VERSION 5.8 ;
BUSBITCHARS "[]" ;
DIVIDERCHAR "/" ;
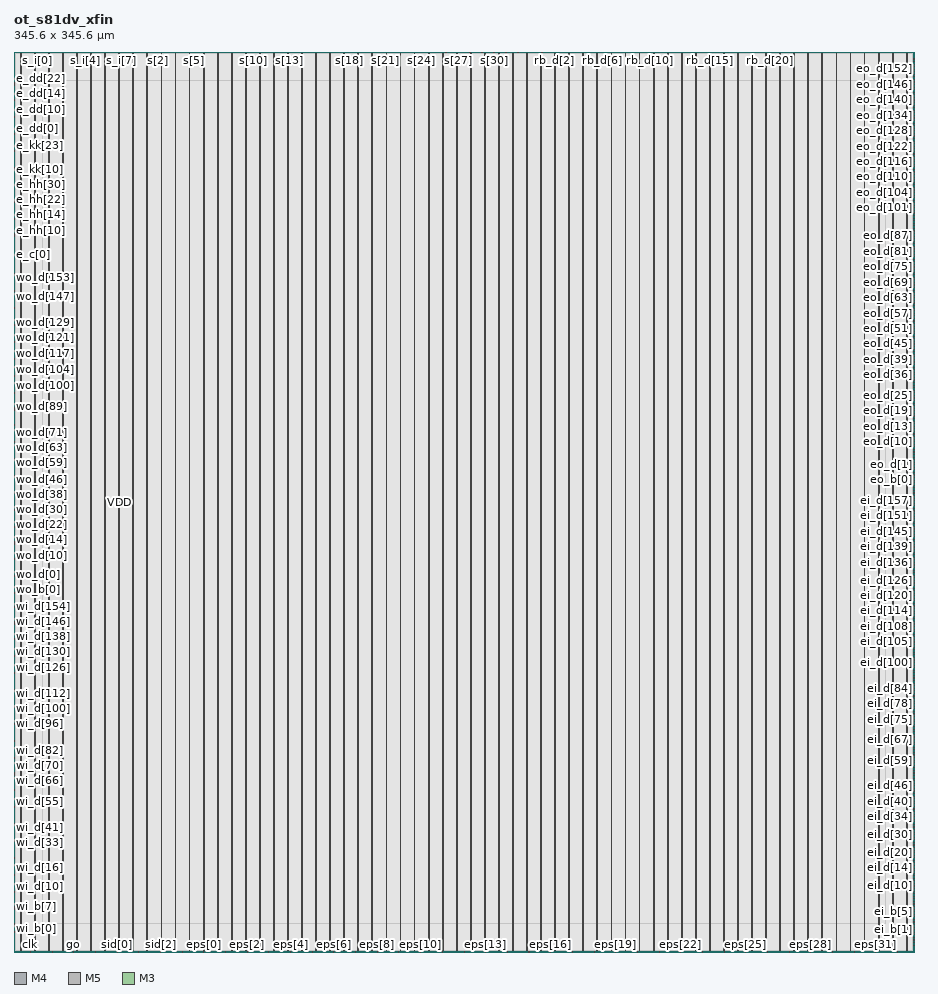
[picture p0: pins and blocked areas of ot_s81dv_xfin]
MACRO ot_s81dv_xfin
  CLASS BLOCK ;
  ORIGIN 0 0 ;
  FOREIGN ot_s81dv_xfin 0 0 ;
  SIZE 345.6 BY 345.6 ;
  SYMMETRY X Y ;
  PIN wi_v
    DIRECTION INPUT ;
    USE SIGNAL ;
    PORT
      LAYER M4 ;
        RECT 0.000 7.680 0.192 7.704 ;
    END
  END wi_v
  PIN wi_h[0]
    DIRECTION INPUT ;
    USE SIGNAL ;
    PORT
      LAYER M4 ;
        RECT 0.000 9.264 0.192 9.288 ;
    END
  END wi_h[0]
  PIN wi_h[1]
    DIRECTION INPUT ;
    USE SIGNAL ;
    PORT
      LAYER M4 ;
        RECT 0.000 10.032 0.192 10.056 ;
    END
  END wi_h[1]
  PIN wi_h[2]
    DIRECTION INPUT ;
    USE SIGNAL ;
    PORT
      LAYER M4 ;
        RECT 0.000 10.752 0.192 10.776 ;
    END
  END wi_h[2]
  PIN wi_h[3]
    DIRECTION INPUT ;
    USE SIGNAL ;
    PORT
      LAYER M4 ;
        RECT 0.000 11.472 0.192 11.496 ;
    END
  END wi_h[3]
  PIN wi_b[0]
    DIRECTION INPUT ;
    USE SIGNAL ;
    PORT
      LAYER M4 ;
        RECT 0.000 12.192 0.192 12.216 ;
    END
  END wi_b[0]
  PIN wi_b[1]
    DIRECTION INPUT ;
    USE SIGNAL ;
    PORT
      LAYER M4 ;
        RECT 0.000 12.912 0.192 12.936 ;
    END
  END wi_b[1]
  PIN wi_b[2]
    DIRECTION INPUT ;
    USE SIGNAL ;
    PORT
      LAYER M4 ;
        RECT 0.000 13.632 0.192 13.656 ;
    END
  END wi_b[2]
  PIN wi_b[3]
    DIRECTION INPUT ;
    USE SIGNAL ;
    PORT
      LAYER M4 ;
        RECT 0.000 14.352 0.192 14.376 ;
    END
  END wi_b[3]
  PIN wi_b[4]
    DIRECTION INPUT ;
    USE SIGNAL ;
    PORT
      LAYER M4 ;
        RECT 0.000 15.072 0.192 15.096 ;
    END
  END wi_b[4]
  PIN wi_b[5]
    DIRECTION INPUT ;
    USE SIGNAL ;
    PORT
      LAYER M4 ;
        RECT 0.000 15.792 0.192 15.816 ;
    END
  END wi_b[5]
  PIN wi_b[6]
    DIRECTION INPUT ;
    USE SIGNAL ;
    PORT
      LAYER M4 ;
        RECT 0.000 16.512 0.192 16.536 ;
    END
  END wi_b[6]
  PIN wi_b[7]
    DIRECTION INPUT ;
    USE SIGNAL ;
    PORT
      LAYER M4 ;
        RECT 0.000 17.280 0.192 17.304 ;
    END
  END wi_b[7]
  PIN wi_d[0]
    DIRECTION INPUT ;
    USE SIGNAL ;
    PORT
      LAYER M4 ;
        RECT 0.000 18.000 0.192 18.024 ;
    END
  END wi_d[0]
  PIN wi_d[1]
    DIRECTION INPUT ;
    USE SIGNAL ;
    PORT
      LAYER M4 ;
        RECT 0.000 18.720 0.192 18.744 ;
    END
  END wi_d[1]
  PIN wi_d[2]
    DIRECTION INPUT ;
    USE SIGNAL ;
    PORT
      LAYER M4 ;
        RECT 0.000 19.440 0.192 19.464 ;
    END
  END wi_d[2]
  PIN wi_d[3]
    DIRECTION INPUT ;
    USE SIGNAL ;
    PORT
      LAYER M4 ;
        RECT 0.000 20.160 0.192 20.184 ;
    END
  END wi_d[3]
  PIN wi_d[4]
    DIRECTION INPUT ;
    USE SIGNAL ;
    PORT
      LAYER M4 ;
        RECT 0.000 20.880 0.192 20.904 ;
    END
  END wi_d[4]
  PIN wi_d[5]
    DIRECTION INPUT ;
    USE SIGNAL ;
    PORT
      LAYER M4 ;
        RECT 0.000 21.600 0.192 21.624 ;
    END
  END wi_d[5]
  PIN wi_d[6]
    DIRECTION INPUT ;
    USE SIGNAL ;
    PORT
      LAYER M4 ;
        RECT 0.000 22.320 0.192 22.344 ;
    END
  END wi_d[6]
  PIN wi_d[7]
    DIRECTION INPUT ;
    USE SIGNAL ;
    PORT
      LAYER M4 ;
        RECT 0.000 23.040 0.192 23.064 ;
    END
  END wi_d[7]
  PIN wi_d[8]
    DIRECTION INPUT ;
    USE SIGNAL ;
    PORT
      LAYER M4 ;
        RECT 0.000 23.760 0.192 23.784 ;
    END
  END wi_d[8]
  PIN wi_d[9]
    DIRECTION INPUT ;
    USE SIGNAL ;
    PORT
      LAYER M4 ;
        RECT 0.000 24.528 0.192 24.552 ;
    END
  END wi_d[9]
  PIN wi_d[10]
    DIRECTION INPUT ;
    USE SIGNAL ;
    PORT
      LAYER M4 ;
        RECT 0.000 25.248 0.192 25.272 ;
    END
  END wi_d[10]
  PIN wi_d[11]
    DIRECTION INPUT ;
    USE SIGNAL ;
    PORT
      LAYER M4 ;
        RECT 0.000 25.968 0.192 25.992 ;
    END
  END wi_d[11]
  PIN wi_d[12]
    DIRECTION INPUT ;
    USE SIGNAL ;
    PORT
      LAYER M4 ;
        RECT 0.000 26.688 0.192 26.712 ;
    END
  END wi_d[12]
  PIN wi_d[13]
    DIRECTION INPUT ;
    USE SIGNAL ;
    PORT
      LAYER M4 ;
        RECT 0.000 27.408 0.192 27.432 ;
    END
  END wi_d[13]
  PIN wi_d[14]
    DIRECTION INPUT ;
    USE SIGNAL ;
    PORT
      LAYER M4 ;
        RECT 0.000 28.128 0.192 28.152 ;
    END
  END wi_d[14]
  PIN wi_d[15]
    DIRECTION INPUT ;
    USE SIGNAL ;
    PORT
      LAYER M4 ;
        RECT 0.000 28.848 0.192 28.872 ;
    END
  END wi_d[15]
  PIN wi_d[16]
    DIRECTION INPUT ;
    USE SIGNAL ;
    PORT
      LAYER M4 ;
        RECT 0.000 29.568 0.192 29.592 ;
    END
  END wi_d[16]
  PIN wi_d[17]
    DIRECTION INPUT ;
    USE SIGNAL ;
    PORT
      LAYER M4 ;
        RECT 0.000 30.288 0.192 30.312 ;
    END
  END wi_d[17]
  PIN wi_d[18]
    DIRECTION INPUT ;
    USE SIGNAL ;
    PORT
      LAYER M4 ;
        RECT 0.000 31.008 0.192 31.032 ;
    END
  END wi_d[18]
  PIN wi_d[19]
    DIRECTION INPUT ;
    USE SIGNAL ;
    PORT
      LAYER M4 ;
        RECT 0.000 31.776 0.192 31.800 ;
    END
  END wi_d[19]
  PIN wi_d[20]
    DIRECTION INPUT ;
    USE SIGNAL ;
    PORT
      LAYER M4 ;
        RECT 0.000 32.496 0.192 32.520 ;
    END
  END wi_d[20]
  PIN wi_d[21]
    DIRECTION INPUT ;
    USE SIGNAL ;
    PORT
      LAYER M4 ;
        RECT 0.000 33.216 0.192 33.240 ;
    END
  END wi_d[21]
  PIN wi_d[22]
    DIRECTION INPUT ;
    USE SIGNAL ;
    PORT
      LAYER M4 ;
        RECT 0.000 33.936 0.192 33.960 ;
    END
  END wi_d[22]
  PIN wi_d[23]
    DIRECTION INPUT ;
    USE SIGNAL ;
    PORT
      LAYER M4 ;
        RECT 0.000 34.656 0.192 34.680 ;
    END
  END wi_d[23]
  PIN wi_d[24]
    DIRECTION INPUT ;
    USE SIGNAL ;
    PORT
      LAYER M4 ;
        RECT 0.000 35.376 0.192 35.400 ;
    END
  END wi_d[24]
  PIN wi_d[25]
    DIRECTION INPUT ;
    USE SIGNAL ;
    PORT
      LAYER M4 ;
        RECT 0.000 36.096 0.192 36.120 ;
    END
  END wi_d[25]
  PIN wi_d[26]
    DIRECTION INPUT ;
    USE SIGNAL ;
    PORT
      LAYER M4 ;
        RECT 0.000 36.816 0.192 36.840 ;
    END
  END wi_d[26]
  PIN wi_d[27]
    DIRECTION INPUT ;
    USE SIGNAL ;
    PORT
      LAYER M4 ;
        RECT 0.000 37.536 0.192 37.560 ;
    END
  END wi_d[27]
  PIN wi_d[28]
    DIRECTION INPUT ;
    USE SIGNAL ;
    PORT
      LAYER M4 ;
        RECT 0.000 38.256 0.192 38.280 ;
    END
  END wi_d[28]
  PIN wi_d[29]
    DIRECTION INPUT ;
    USE SIGNAL ;
    PORT
      LAYER M4 ;
        RECT 0.000 38.976 0.192 39.000 ;
    END
  END wi_d[29]
  PIN wi_d[30]
    DIRECTION INPUT ;
    USE SIGNAL ;
    PORT
      LAYER M4 ;
        RECT 0.000 39.744 0.192 39.768 ;
    END
  END wi_d[30]
  PIN wi_d[31]
    DIRECTION INPUT ;
    USE SIGNAL ;
    PORT
      LAYER M4 ;
        RECT 0.000 40.464 0.192 40.488 ;
    END
  END wi_d[31]
  PIN wi_d[32]
    DIRECTION INPUT ;
    USE SIGNAL ;
    PORT
      LAYER M4 ;
        RECT 0.000 41.184 0.192 41.208 ;
    END
  END wi_d[32]
  PIN wi_d[33]
    DIRECTION INPUT ;
    USE SIGNAL ;
    PORT
      LAYER M4 ;
        RECT 0.000 41.904 0.192 41.928 ;
    END
  END wi_d[33]
  PIN wi_d[34]
    DIRECTION INPUT ;
    USE SIGNAL ;
    PORT
      LAYER M4 ;
        RECT 0.000 42.624 0.192 42.648 ;
    END
  END wi_d[34]
  PIN wi_d[35]
    DIRECTION INPUT ;
    USE SIGNAL ;
    PORT
      LAYER M4 ;
        RECT 0.000 43.344 0.192 43.368 ;
    END
  END wi_d[35]
  PIN wi_d[36]
    DIRECTION INPUT ;
    USE SIGNAL ;
    PORT
      LAYER M4 ;
        RECT 0.000 44.064 0.192 44.088 ;
    END
  END wi_d[36]
  PIN wi_d[37]
    DIRECTION INPUT ;
    USE SIGNAL ;
    PORT
      LAYER M4 ;
        RECT 0.000 44.784 0.192 44.808 ;
    END
  END wi_d[37]
  PIN wi_d[38]
    DIRECTION INPUT ;
    USE SIGNAL ;
    PORT
      LAYER M4 ;
        RECT 0.000 45.504 0.192 45.528 ;
    END
  END wi_d[38]
  PIN wi_d[39]
    DIRECTION INPUT ;
    USE SIGNAL ;
    PORT
      LAYER M4 ;
        RECT 0.000 46.224 0.192 46.248 ;
    END
  END wi_d[39]
  PIN wi_d[40]
    DIRECTION INPUT ;
    USE SIGNAL ;
    PORT
      LAYER M4 ;
        RECT 0.000 46.992 0.192 47.016 ;
    END
  END wi_d[40]
  PIN wi_d[41]
    DIRECTION INPUT ;
    USE SIGNAL ;
    PORT
      LAYER M4 ;
        RECT 0.000 47.712 0.192 47.736 ;
    END
  END wi_d[41]
  PIN wi_d[42]
    DIRECTION INPUT ;
    USE SIGNAL ;
    PORT
      LAYER M4 ;
        RECT 0.000 48.432 0.192 48.456 ;
    END
  END wi_d[42]
  PIN wi_d[43]
    DIRECTION INPUT ;
    USE SIGNAL ;
    PORT
      LAYER M4 ;
        RECT 0.000 49.152 0.192 49.176 ;
    END
  END wi_d[43]
  PIN wi_d[44]
    DIRECTION INPUT ;
    USE SIGNAL ;
    PORT
      LAYER M4 ;
        RECT 0.000 49.872 0.192 49.896 ;
    END
  END wi_d[44]
  PIN wi_d[45]
    DIRECTION INPUT ;
    USE SIGNAL ;
    PORT
      LAYER M4 ;
        RECT 0.000 50.592 0.192 50.616 ;
    END
  END wi_d[45]
  PIN wi_d[46]
    DIRECTION INPUT ;
    USE SIGNAL ;
    PORT
      LAYER M4 ;
        RECT 0.000 51.312 0.192 51.336 ;
    END
  END wi_d[46]
  PIN wi_d[47]
    DIRECTION INPUT ;
    USE SIGNAL ;
    PORT
      LAYER M4 ;
        RECT 0.000 52.032 0.192 52.056 ;
    END
  END wi_d[47]
  PIN wi_d[48]
    DIRECTION INPUT ;
    USE SIGNAL ;
    PORT
      LAYER M4 ;
        RECT 0.000 52.752 0.192 52.776 ;
    END
  END wi_d[48]
  PIN wi_d[49]
    DIRECTION INPUT ;
    USE SIGNAL ;
    PORT
      LAYER M4 ;
        RECT 0.000 53.472 0.192 53.496 ;
    END
  END wi_d[49]
  PIN wi_d[50]
    DIRECTION INPUT ;
    USE SIGNAL ;
    PORT
      LAYER M4 ;
        RECT 0.000 54.240 0.192 54.264 ;
    END
  END wi_d[50]
  PIN wi_d[51]
    DIRECTION INPUT ;
    USE SIGNAL ;
    PORT
      LAYER M4 ;
        RECT 0.000 54.960 0.192 54.984 ;
    END
  END wi_d[51]
  PIN wi_d[52]
    DIRECTION INPUT ;
    USE SIGNAL ;
    PORT
      LAYER M4 ;
        RECT 0.000 55.680 0.192 55.704 ;
    END
  END wi_d[52]
  PIN wi_d[53]
    DIRECTION INPUT ;
    USE SIGNAL ;
    PORT
      LAYER M4 ;
        RECT 0.000 56.400 0.192 56.424 ;
    END
  END wi_d[53]
  PIN wi_d[54]
    DIRECTION INPUT ;
    USE SIGNAL ;
    PORT
      LAYER M4 ;
        RECT 0.000 57.120 0.192 57.144 ;
    END
  END wi_d[54]
  PIN wi_d[55]
    DIRECTION INPUT ;
    USE SIGNAL ;
    PORT
      LAYER M4 ;
        RECT 0.000 57.840 0.192 57.864 ;
    END
  END wi_d[55]
  PIN wi_d[56]
    DIRECTION INPUT ;
    USE SIGNAL ;
    PORT
      LAYER M4 ;
        RECT 0.000 58.560 0.192 58.584 ;
    END
  END wi_d[56]
  PIN wi_d[57]
    DIRECTION INPUT ;
    USE SIGNAL ;
    PORT
      LAYER M4 ;
        RECT 0.000 59.280 0.192 59.304 ;
    END
  END wi_d[57]
  PIN wi_d[58]
    DIRECTION INPUT ;
    USE SIGNAL ;
    PORT
      LAYER M4 ;
        RECT 0.000 60.000 0.192 60.024 ;
    END
  END wi_d[58]
  PIN wi_d[59]
    DIRECTION INPUT ;
    USE SIGNAL ;
    PORT
      LAYER M4 ;
        RECT 0.000 60.720 0.192 60.744 ;
    END
  END wi_d[59]
  PIN wi_d[60]
    DIRECTION INPUT ;
    USE SIGNAL ;
    PORT
      LAYER M4 ;
        RECT 0.000 61.488 0.192 61.512 ;
    END
  END wi_d[60]
  PIN wi_d[61]
    DIRECTION INPUT ;
    USE SIGNAL ;
    PORT
      LAYER M4 ;
        RECT 0.000 62.208 0.192 62.232 ;
    END
  END wi_d[61]
  PIN wi_d[62]
    DIRECTION INPUT ;
    USE SIGNAL ;
    PORT
      LAYER M4 ;
        RECT 0.000 62.928 0.192 62.952 ;
    END
  END wi_d[62]
  PIN wi_d[63]
    DIRECTION INPUT ;
    USE SIGNAL ;
    PORT
      LAYER M4 ;
        RECT 0.000 63.648 0.192 63.672 ;
    END
  END wi_d[63]
  PIN wi_d[64]
    DIRECTION INPUT ;
    USE SIGNAL ;
    PORT
      LAYER M4 ;
        RECT 0.000 64.368 0.192 64.392 ;
    END
  END wi_d[64]
  PIN wi_d[65]
    DIRECTION INPUT ;
    USE SIGNAL ;
    PORT
      LAYER M4 ;
        RECT 0.000 65.088 0.192 65.112 ;
    END
  END wi_d[65]
  PIN wi_d[66]
    DIRECTION INPUT ;
    USE SIGNAL ;
    PORT
      LAYER M4 ;
        RECT 0.000 65.808 0.192 65.832 ;
    END
  END wi_d[66]
  PIN wi_d[67]
    DIRECTION INPUT ;
    USE SIGNAL ;
    PORT
      LAYER M4 ;
        RECT 0.000 66.528 0.192 66.552 ;
    END
  END wi_d[67]
  PIN wi_d[68]
    DIRECTION INPUT ;
    USE SIGNAL ;
    PORT
      LAYER M4 ;
        RECT 0.000 67.248 0.192 67.272 ;
    END
  END wi_d[68]
  PIN wi_d[69]
    DIRECTION INPUT ;
    USE SIGNAL ;
    PORT
      LAYER M4 ;
        RECT 0.000 67.968 0.192 67.992 ;
    END
  END wi_d[69]
  PIN wi_d[70]
    DIRECTION INPUT ;
    USE SIGNAL ;
    PORT
      LAYER M4 ;
        RECT 0.000 68.736 0.192 68.760 ;
    END
  END wi_d[70]
  PIN wi_d[71]
    DIRECTION INPUT ;
    USE SIGNAL ;
    PORT
      LAYER M4 ;
        RECT 0.000 69.456 0.192 69.480 ;
    END
  END wi_d[71]
  PIN wi_d[72]
    DIRECTION INPUT ;
    USE SIGNAL ;
    PORT
      LAYER M4 ;
        RECT 0.000 70.176 0.192 70.200 ;
    END
  END wi_d[72]
  PIN wi_d[73]
    DIRECTION INPUT ;
    USE SIGNAL ;
    PORT
      LAYER M4 ;
        RECT 0.000 70.896 0.192 70.920 ;
    END
  END wi_d[73]
  PIN wi_d[74]
    DIRECTION INPUT ;
    USE SIGNAL ;
    PORT
      LAYER M4 ;
        RECT 0.000 71.616 0.192 71.640 ;
    END
  END wi_d[74]
  PIN wi_d[75]
    DIRECTION INPUT ;
    USE SIGNAL ;
    PORT
      LAYER M4 ;
        RECT 0.000 72.336 0.192 72.360 ;
    END
  END wi_d[75]
  PIN wi_d[76]
    DIRECTION INPUT ;
    USE SIGNAL ;
    PORT
      LAYER M4 ;
        RECT 0.000 73.056 0.192 73.080 ;
    END
  END wi_d[76]
  PIN wi_d[77]
    DIRECTION INPUT ;
    USE SIGNAL ;
    PORT
      LAYER M4 ;
        RECT 0.000 73.776 0.192 73.800 ;
    END
  END wi_d[77]
  PIN wi_d[78]
    DIRECTION INPUT ;
    USE SIGNAL ;
    PORT
      LAYER M4 ;
        RECT 0.000 74.496 0.192 74.520 ;
    END
  END wi_d[78]
  PIN wi_d[79]
    DIRECTION INPUT ;
    USE SIGNAL ;
    PORT
      LAYER M4 ;
        RECT 0.000 75.216 0.192 75.240 ;
    END
  END wi_d[79]
  PIN wi_d[80]
    DIRECTION INPUT ;
    USE SIGNAL ;
    PORT
      LAYER M4 ;
        RECT 0.000 75.984 0.192 76.008 ;
    END
  END wi_d[80]
  PIN wi_d[81]
    DIRECTION INPUT ;
    USE SIGNAL ;
    PORT
      LAYER M4 ;
        RECT 0.000 76.704 0.192 76.728 ;
    END
  END wi_d[81]
  PIN wi_d[82]
    DIRECTION INPUT ;
    USE SIGNAL ;
    PORT
      LAYER M4 ;
        RECT 0.000 77.424 0.192 77.448 ;
    END
  END wi_d[82]
  PIN wi_d[83]
    DIRECTION INPUT ;
    USE SIGNAL ;
    PORT
      LAYER M4 ;
        RECT 0.000 78.144 0.192 78.168 ;
    END
  END wi_d[83]
  PIN wi_d[84]
    DIRECTION INPUT ;
    USE SIGNAL ;
    PORT
      LAYER M4 ;
        RECT 0.000 78.864 0.192 78.888 ;
    END
  END wi_d[84]
  PIN wi_d[85]
    DIRECTION INPUT ;
    USE SIGNAL ;
    PORT
      LAYER M4 ;
        RECT 0.000 79.584 0.192 79.608 ;
    END
  END wi_d[85]
  PIN wi_d[86]
    DIRECTION INPUT ;
    USE SIGNAL ;
    PORT
      LAYER M4 ;
        RECT 0.000 80.304 0.192 80.328 ;
    END
  END wi_d[86]
  PIN wi_d[87]
    DIRECTION INPUT ;
    USE SIGNAL ;
    PORT
      LAYER M4 ;
        RECT 0.000 81.024 0.192 81.048 ;
    END
  END wi_d[87]
  PIN wi_d[88]
    DIRECTION INPUT ;
    USE SIGNAL ;
    PORT
      LAYER M4 ;
        RECT 0.000 81.744 0.192 81.768 ;
    END
  END wi_d[88]
  PIN wi_d[89]
    DIRECTION INPUT ;
    USE SIGNAL ;
    PORT
      LAYER M4 ;
        RECT 0.000 82.464 0.192 82.488 ;
    END
  END wi_d[89]
  PIN wi_d[90]
    DIRECTION INPUT ;
    USE SIGNAL ;
    PORT
      LAYER M4 ;
        RECT 0.000 83.232 0.192 83.256 ;
    END
  END wi_d[90]
  PIN wi_d[91]
    DIRECTION INPUT ;
    USE SIGNAL ;
    PORT
      LAYER M4 ;
        RECT 0.000 83.952 0.192 83.976 ;
    END
  END wi_d[91]
  PIN wi_d[92]
    DIRECTION INPUT ;
    USE SIGNAL ;
    PORT
      LAYER M4 ;
        RECT 0.000 84.672 0.192 84.696 ;
    END
  END wi_d[92]
  PIN wi_d[93]
    DIRECTION INPUT ;
    USE SIGNAL ;
    PORT
      LAYER M4 ;
        RECT 0.000 85.392 0.192 85.416 ;
    END
  END wi_d[93]
  PIN wi_d[94]
    DIRECTION INPUT ;
    USE SIGNAL ;
    PORT
      LAYER M4 ;
        RECT 0.000 86.112 0.192 86.136 ;
    END
  END wi_d[94]
  PIN wi_d[95]
    DIRECTION INPUT ;
    USE SIGNAL ;
    PORT
      LAYER M4 ;
        RECT 0.000 86.832 0.192 86.856 ;
    END
  END wi_d[95]
  PIN wi_d[96]
    DIRECTION INPUT ;
    USE SIGNAL ;
    PORT
      LAYER M4 ;
        RECT 0.000 87.552 0.192 87.576 ;
    END
  END wi_d[96]
  PIN wi_d[97]
    DIRECTION INPUT ;
    USE SIGNAL ;
    PORT
      LAYER M4 ;
        RECT 0.000 88.272 0.192 88.296 ;
    END
  END wi_d[97]
  PIN wi_d[98]
    DIRECTION INPUT ;
    USE SIGNAL ;
    PORT
      LAYER M4 ;
        RECT 0.000 88.992 0.192 89.016 ;
    END
  END wi_d[98]
  PIN wi_d[99]
    DIRECTION INPUT ;
    USE SIGNAL ;
    PORT
      LAYER M4 ;
        RECT 0.000 89.712 0.192 89.736 ;
    END
  END wi_d[99]
  PIN wi_d[100]
    DIRECTION INPUT ;
    USE SIGNAL ;
    PORT
      LAYER M4 ;
        RECT 0.000 90.480 0.192 90.504 ;
    END
  END wi_d[100]
  PIN wi_d[101]
    DIRECTION INPUT ;
    USE SIGNAL ;
    PORT
      LAYER M4 ;
        RECT 0.000 91.200 0.192 91.224 ;
    END
  END wi_d[101]
  PIN wi_d[102]
    DIRECTION INPUT ;
    USE SIGNAL ;
    PORT
      LAYER M4 ;
        RECT 0.000 91.920 0.192 91.944 ;
    END
  END wi_d[102]
  PIN wi_d[103]
    DIRECTION INPUT ;
    USE SIGNAL ;
    PORT
      LAYER M4 ;
        RECT 0.000 92.640 0.192 92.664 ;
    END
  END wi_d[103]
  PIN wi_d[104]
    DIRECTION INPUT ;
    USE SIGNAL ;
    PORT
      LAYER M4 ;
        RECT 0.000 93.360 0.192 93.384 ;
    END
  END wi_d[104]
  PIN wi_d[105]
    DIRECTION INPUT ;
    USE SIGNAL ;
    PORT
      LAYER M4 ;
        RECT 0.000 94.080 0.192 94.104 ;
    END
  END wi_d[105]
  PIN wi_d[106]
    DIRECTION INPUT ;
    USE SIGNAL ;
    PORT
      LAYER M4 ;
        RECT 0.000 94.800 0.192 94.824 ;
    END
  END wi_d[106]
  PIN wi_d[107]
    DIRECTION INPUT ;
    USE SIGNAL ;
    PORT
      LAYER M4 ;
        RECT 0.000 95.520 0.192 95.544 ;
    END
  END wi_d[107]
  PIN wi_d[108]
    DIRECTION INPUT ;
    USE SIGNAL ;
    PORT
      LAYER M4 ;
        RECT 0.000 96.240 0.192 96.264 ;
    END
  END wi_d[108]
  PIN wi_d[109]
    DIRECTION INPUT ;
    USE SIGNAL ;
    PORT
      LAYER M4 ;
        RECT 0.000 96.960 0.192 96.984 ;
    END
  END wi_d[109]
  PIN wi_d[110]
    DIRECTION INPUT ;
    USE SIGNAL ;
    PORT
      LAYER M4 ;
        RECT 0.000 97.728 0.192 97.752 ;
    END
  END wi_d[110]
  PIN wi_d[111]
    DIRECTION INPUT ;
    USE SIGNAL ;
    PORT
      LAYER M4 ;
        RECT 0.000 98.448 0.192 98.472 ;
    END
  END wi_d[111]
  PIN wi_d[112]
    DIRECTION INPUT ;
    USE SIGNAL ;
    PORT
      LAYER M4 ;
        RECT 0.000 99.168 0.192 99.192 ;
    END
  END wi_d[112]
  PIN wi_d[113]
    DIRECTION INPUT ;
    USE SIGNAL ;
    PORT
      LAYER M4 ;
        RECT 0.000 99.888 0.192 99.912 ;
    END
  END wi_d[113]
  PIN wi_d[114]
    DIRECTION INPUT ;
    USE SIGNAL ;
    PORT
      LAYER M4 ;
        RECT 0.000 100.608 0.192 100.632 ;
    END
  END wi_d[114]
  PIN wi_d[115]
    DIRECTION INPUT ;
    USE SIGNAL ;
    PORT
      LAYER M4 ;
        RECT 0.000 101.328 0.192 101.352 ;
    END
  END wi_d[115]
  PIN wi_d[116]
    DIRECTION INPUT ;
    USE SIGNAL ;
    PORT
      LAYER M4 ;
        RECT 0.000 102.048 0.192 102.072 ;
    END
  END wi_d[116]
  PIN wi_d[117]
    DIRECTION INPUT ;
    USE SIGNAL ;
    PORT
      LAYER M4 ;
        RECT 0.000 102.768 0.192 102.792 ;
    END
  END wi_d[117]
  PIN wi_d[118]
    DIRECTION INPUT ;
    USE SIGNAL ;
    PORT
      LAYER M4 ;
        RECT 0.000 103.488 0.192 103.512 ;
    END
  END wi_d[118]
  PIN wi_d[119]
    DIRECTION INPUT ;
    USE SIGNAL ;
    PORT
      LAYER M4 ;
        RECT 0.000 104.208 0.192 104.232 ;
    END
  END wi_d[119]
  PIN wi_d[120]
    DIRECTION INPUT ;
    USE SIGNAL ;
    PORT
      LAYER M4 ;
        RECT 0.000 104.976 0.192 105.000 ;
    END
  END wi_d[120]
  PIN wi_d[121]
    DIRECTION INPUT ;
    USE SIGNAL ;
    PORT
      LAYER M4 ;
        RECT 0.000 105.696 0.192 105.720 ;
    END
  END wi_d[121]
  PIN wi_d[122]
    DIRECTION INPUT ;
    USE SIGNAL ;
    PORT
      LAYER M4 ;
        RECT 0.000 106.416 0.192 106.440 ;
    END
  END wi_d[122]
  PIN wi_d[123]
    DIRECTION INPUT ;
    USE SIGNAL ;
    PORT
      LAYER M4 ;
        RECT 0.000 107.136 0.192 107.160 ;
    END
  END wi_d[123]
  PIN wi_d[124]
    DIRECTION INPUT ;
    USE SIGNAL ;
    PORT
      LAYER M4 ;
        RECT 0.000 107.856 0.192 107.880 ;
    END
  END wi_d[124]
  PIN wi_d[125]
    DIRECTION INPUT ;
    USE SIGNAL ;
    PORT
      LAYER M4 ;
        RECT 0.000 108.576 0.192 108.600 ;
    END
  END wi_d[125]
  PIN wi_d[126]
    DIRECTION INPUT ;
    USE SIGNAL ;
    PORT
      LAYER M4 ;
        RECT 0.000 109.296 0.192 109.320 ;
    END
  END wi_d[126]
  PIN wi_d[127]
    DIRECTION INPUT ;
    USE SIGNAL ;
    PORT
      LAYER M4 ;
        RECT 0.000 110.016 0.192 110.040 ;
    END
  END wi_d[127]
  PIN wi_d[128]
    DIRECTION INPUT ;
    USE SIGNAL ;
    PORT
      LAYER M4 ;
        RECT 0.000 110.736 0.192 110.760 ;
    END
  END wi_d[128]
  PIN wi_d[129]
    DIRECTION INPUT ;
    USE SIGNAL ;
    PORT
      LAYER M4 ;
        RECT 0.000 111.456 0.192 111.480 ;
    END
  END wi_d[129]
  PIN wi_d[130]
    DIRECTION INPUT ;
    USE SIGNAL ;
    PORT
      LAYER M4 ;
        RECT 0.000 112.224 0.192 112.248 ;
    END
  END wi_d[130]
  PIN wi_d[131]
    DIRECTION INPUT ;
    USE SIGNAL ;
    PORT
      LAYER M4 ;
        RECT 0.000 112.944 0.192 112.968 ;
    END
  END wi_d[131]
  PIN wi_d[132]
    DIRECTION INPUT ;
    USE SIGNAL ;
    PORT
      LAYER M4 ;
        RECT 0.000 113.664 0.192 113.688 ;
    END
  END wi_d[132]
  PIN wi_d[133]
    DIRECTION INPUT ;
    USE SIGNAL ;
    PORT
      LAYER M4 ;
        RECT 0.000 114.384 0.192 114.408 ;
    END
  END wi_d[133]
  PIN wi_d[134]
    DIRECTION INPUT ;
    USE SIGNAL ;
    PORT
      LAYER M4 ;
        RECT 0.000 115.104 0.192 115.128 ;
    END
  END wi_d[134]
  PIN wi_d[135]
    DIRECTION INPUT ;
    USE SIGNAL ;
    PORT
      LAYER M4 ;
        RECT 0.000 115.824 0.192 115.848 ;
    END
  END wi_d[135]
  PIN wi_d[136]
    DIRECTION INPUT ;
    USE SIGNAL ;
    PORT
      LAYER M4 ;
        RECT 0.000 116.544 0.192 116.568 ;
    END
  END wi_d[136]
  PIN wi_d[137]
    DIRECTION INPUT ;
    USE SIGNAL ;
    PORT
      LAYER M4 ;
        RECT 0.000 117.264 0.192 117.288 ;
    END
  END wi_d[137]
  PIN wi_d[138]
    DIRECTION INPUT ;
    USE SIGNAL ;
    PORT
      LAYER M4 ;
        RECT 0.000 117.984 0.192 118.008 ;
    END
  END wi_d[138]
  PIN wi_d[139]
    DIRECTION INPUT ;
    USE SIGNAL ;
    PORT
      LAYER M4 ;
        RECT 0.000 118.704 0.192 118.728 ;
    END
  END wi_d[139]
  PIN wi_d[140]
    DIRECTION INPUT ;
    USE SIGNAL ;
    PORT
      LAYER M4 ;
        RECT 0.000 119.472 0.192 119.496 ;
    END
  END wi_d[140]
  PIN wi_d[141]
    DIRECTION INPUT ;
    USE SIGNAL ;
    PORT
      LAYER M4 ;
        RECT 0.000 120.192 0.192 120.216 ;
    END
  END wi_d[141]
  PIN wi_d[142]
    DIRECTION INPUT ;
    USE SIGNAL ;
    PORT
      LAYER M4 ;
        RECT 0.000 120.912 0.192 120.936 ;
    END
  END wi_d[142]
  PIN wi_d[143]
    DIRECTION INPUT ;
    USE SIGNAL ;
    PORT
      LAYER M4 ;
        RECT 0.000 121.632 0.192 121.656 ;
    END
  END wi_d[143]
  PIN wi_d[144]
    DIRECTION INPUT ;
    USE SIGNAL ;
    PORT
      LAYER M4 ;
        RECT 0.000 122.352 0.192 122.376 ;
    END
  END wi_d[144]
  PIN wi_d[145]
    DIRECTION INPUT ;
    USE SIGNAL ;
    PORT
      LAYER M4 ;
        RECT 0.000 123.072 0.192 123.096 ;
    END
  END wi_d[145]
  PIN wi_d[146]
    DIRECTION INPUT ;
    USE SIGNAL ;
    PORT
      LAYER M4 ;
        RECT 0.000 123.792 0.192 123.816 ;
    END
  END wi_d[146]
  PIN wi_d[147]
    DIRECTION INPUT ;
    USE SIGNAL ;
    PORT
      LAYER M4 ;
        RECT 0.000 124.512 0.192 124.536 ;
    END
  END wi_d[147]
  PIN wi_d[148]
    DIRECTION INPUT ;
    USE SIGNAL ;
    PORT
      LAYER M4 ;
        RECT 0.000 125.232 0.192 125.256 ;
    END
  END wi_d[148]
  PIN wi_d[149]
    DIRECTION INPUT ;
    USE SIGNAL ;
    PORT
      LAYER M4 ;
        RECT 0.000 125.952 0.192 125.976 ;
    END
  END wi_d[149]
  PIN wi_d[150]
    DIRECTION INPUT ;
    USE SIGNAL ;
    PORT
      LAYER M4 ;
        RECT 0.000 126.720 0.192 126.744 ;
    END
  END wi_d[150]
  PIN wi_d[151]
    DIRECTION INPUT ;
    USE SIGNAL ;
    PORT
      LAYER M4 ;
        RECT 0.000 127.440 0.192 127.464 ;
    END
  END wi_d[151]
  PIN wi_d[152]
    DIRECTION INPUT ;
    USE SIGNAL ;
    PORT
      LAYER M4 ;
        RECT 0.000 128.160 0.192 128.184 ;
    END
  END wi_d[152]
  PIN wi_d[153]
    DIRECTION INPUT ;
    USE SIGNAL ;
    PORT
      LAYER M4 ;
        RECT 0.000 128.880 0.192 128.904 ;
    END
  END wi_d[153]
  PIN wi_d[154]
    DIRECTION INPUT ;
    USE SIGNAL ;
    PORT
      LAYER M4 ;
        RECT 0.000 129.600 0.192 129.624 ;
    END
  END wi_d[154]
  PIN wi_d[155]
    DIRECTION INPUT ;
    USE SIGNAL ;
    PORT
      LAYER M4 ;
        RECT 0.000 130.320 0.192 130.344 ;
    END
  END wi_d[155]
  PIN wi_d[156]
    DIRECTION INPUT ;
    USE SIGNAL ;
    PORT
      LAYER M4 ;
        RECT 0.000 131.040 0.192 131.064 ;
    END
  END wi_d[156]
  PIN wi_d[157]
    DIRECTION INPUT ;
    USE SIGNAL ;
    PORT
      LAYER M4 ;
        RECT 0.000 131.760 0.192 131.784 ;
    END
  END wi_d[157]
  PIN wi_d[158]
    DIRECTION INPUT ;
    USE SIGNAL ;
    PORT
      LAYER M4 ;
        RECT 0.000 132.480 0.192 132.504 ;
    END
  END wi_d[158]
  PIN wi_d[159]
    DIRECTION INPUT ;
    USE SIGNAL ;
    PORT
      LAYER M4 ;
        RECT 0.000 133.200 0.192 133.224 ;
    END
  END wi_d[159]
  PIN wo_v
    DIRECTION OUTPUT ;
    USE SIGNAL ;
    PORT
      LAYER M4 ;
        RECT 0.000 134.832 0.192 134.856 ;
    END
  END wo_v
  PIN wo_h[0]
    DIRECTION OUTPUT ;
    USE SIGNAL ;
    PORT
      LAYER M4 ;
        RECT 0.000 136.416 0.192 136.440 ;
    END
  END wo_h[0]
  PIN wo_h[1]
    DIRECTION OUTPUT ;
    USE SIGNAL ;
    PORT
      LAYER M4 ;
        RECT 0.000 137.136 0.192 137.160 ;
    END
  END wo_h[1]
  PIN wo_h[2]
    DIRECTION OUTPUT ;
    USE SIGNAL ;
    PORT
      LAYER M4 ;
        RECT 0.000 137.856 0.192 137.880 ;
    END
  END wo_h[2]
  PIN wo_h[3]
    DIRECTION OUTPUT ;
    USE SIGNAL ;
    PORT
      LAYER M4 ;
        RECT 0.000 138.576 0.192 138.600 ;
    END
  END wo_h[3]
  PIN wo_b[0]
    DIRECTION OUTPUT ;
    USE SIGNAL ;
    PORT
      LAYER M4 ;
        RECT 0.000 139.296 0.192 139.320 ;
    END
  END wo_b[0]
  PIN wo_b[1]
    DIRECTION OUTPUT ;
    USE SIGNAL ;
    PORT
      LAYER M4 ;
        RECT 0.000 140.016 0.192 140.040 ;
    END
  END wo_b[1]
  PIN wo_b[2]
    DIRECTION OUTPUT ;
    USE SIGNAL ;
    PORT
      LAYER M4 ;
        RECT 0.000 140.736 0.192 140.760 ;
    END
  END wo_b[2]
  PIN wo_b[3]
    DIRECTION OUTPUT ;
    USE SIGNAL ;
    PORT
      LAYER M4 ;
        RECT 0.000 141.456 0.192 141.480 ;
    END
  END wo_b[3]
  PIN wo_b[4]
    DIRECTION OUTPUT ;
    USE SIGNAL ;
    PORT
      LAYER M4 ;
        RECT 0.000 142.176 0.192 142.200 ;
    END
  END wo_b[4]
  PIN wo_b[5]
    DIRECTION OUTPUT ;
    USE SIGNAL ;
    PORT
      LAYER M4 ;
        RECT 0.000 142.944 0.192 142.968 ;
    END
  END wo_b[5]
  PIN wo_b[6]
    DIRECTION OUTPUT ;
    USE SIGNAL ;
    PORT
      LAYER M4 ;
        RECT 0.000 143.664 0.192 143.688 ;
    END
  END wo_b[6]
  PIN wo_b[7]
    DIRECTION OUTPUT ;
    USE SIGNAL ;
    PORT
      LAYER M4 ;
        RECT 0.000 144.384 0.192 144.408 ;
    END
  END wo_b[7]
  PIN wo_d[0]
    DIRECTION OUTPUT ;
    USE SIGNAL ;
    PORT
      LAYER M4 ;
        RECT 0.000 145.104 0.192 145.128 ;
    END
  END wo_d[0]
  PIN wo_d[1]
    DIRECTION OUTPUT ;
    USE SIGNAL ;
    PORT
      LAYER M4 ;
        RECT 0.000 145.824 0.192 145.848 ;
    END
  END wo_d[1]
  PIN wo_d[2]
    DIRECTION OUTPUT ;
    USE SIGNAL ;
    PORT
      LAYER M4 ;
        RECT 0.000 146.544 0.192 146.568 ;
    END
  END wo_d[2]
  PIN wo_d[3]
    DIRECTION OUTPUT ;
    USE SIGNAL ;
    PORT
      LAYER M4 ;
        RECT 0.000 147.264 0.192 147.288 ;
    END
  END wo_d[3]
  PIN wo_d[4]
    DIRECTION OUTPUT ;
    USE SIGNAL ;
    PORT
      LAYER M4 ;
        RECT 0.000 147.984 0.192 148.008 ;
    END
  END wo_d[4]
  PIN wo_d[5]
    DIRECTION OUTPUT ;
    USE SIGNAL ;
    PORT
      LAYER M4 ;
        RECT 0.000 148.704 0.192 148.728 ;
    END
  END wo_d[5]
  PIN wo_d[6]
    DIRECTION OUTPUT ;
    USE SIGNAL ;
    PORT
      LAYER M4 ;
        RECT 0.000 149.424 0.192 149.448 ;
    END
  END wo_d[6]
  PIN wo_d[7]
    DIRECTION OUTPUT ;
    USE SIGNAL ;
    PORT
      LAYER M4 ;
        RECT 0.000 150.192 0.192 150.216 ;
    END
  END wo_d[7]
  PIN wo_d[8]
    DIRECTION OUTPUT ;
    USE SIGNAL ;
    PORT
      LAYER M4 ;
        RECT 0.000 150.912 0.192 150.936 ;
    END
  END wo_d[8]
  PIN wo_d[9]
    DIRECTION OUTPUT ;
    USE SIGNAL ;
    PORT
      LAYER M4 ;
        RECT 0.000 151.632 0.192 151.656 ;
    END
  END wo_d[9]
  PIN wo_d[10]
    DIRECTION OUTPUT ;
    USE SIGNAL ;
    PORT
      LAYER M4 ;
        RECT 0.000 152.352 0.192 152.376 ;
    END
  END wo_d[10]
  PIN wo_d[11]
    DIRECTION OUTPUT ;
    USE SIGNAL ;
    PORT
      LAYER M4 ;
        RECT 0.000 153.072 0.192 153.096 ;
    END
  END wo_d[11]
  PIN wo_d[12]
    DIRECTION OUTPUT ;
    USE SIGNAL ;
    PORT
      LAYER M4 ;
        RECT 0.000 153.792 0.192 153.816 ;
    END
  END wo_d[12]
  PIN wo_d[13]
    DIRECTION OUTPUT ;
    USE SIGNAL ;
    PORT
      LAYER M4 ;
        RECT 0.000 154.512 0.192 154.536 ;
    END
  END wo_d[13]
  PIN wo_d[14]
    DIRECTION OUTPUT ;
    USE SIGNAL ;
    PORT
      LAYER M4 ;
        RECT 0.000 155.232 0.192 155.256 ;
    END
  END wo_d[14]
  PIN wo_d[15]
    DIRECTION OUTPUT ;
    USE SIGNAL ;
    PORT
      LAYER M4 ;
        RECT 0.000 155.952 0.192 155.976 ;
    END
  END wo_d[15]
  PIN wo_d[16]
    DIRECTION OUTPUT ;
    USE SIGNAL ;
    PORT
      LAYER M4 ;
        RECT 0.000 156.672 0.192 156.696 ;
    END
  END wo_d[16]
  PIN wo_d[17]
    DIRECTION OUTPUT ;
    USE SIGNAL ;
    PORT
      LAYER M4 ;
        RECT 0.000 157.440 0.192 157.464 ;
    END
  END wo_d[17]
  PIN wo_d[18]
    DIRECTION OUTPUT ;
    USE SIGNAL ;
    PORT
      LAYER M4 ;
        RECT 0.000 158.160 0.192 158.184 ;
    END
  END wo_d[18]
  PIN wo_d[19]
    DIRECTION OUTPUT ;
    USE SIGNAL ;
    PORT
      LAYER M4 ;
        RECT 0.000 158.880 0.192 158.904 ;
    END
  END wo_d[19]
  PIN wo_d[20]
    DIRECTION OUTPUT ;
    USE SIGNAL ;
    PORT
      LAYER M4 ;
        RECT 0.000 159.600 0.192 159.624 ;
    END
  END wo_d[20]
  PIN wo_d[21]
    DIRECTION OUTPUT ;
    USE SIGNAL ;
    PORT
      LAYER M4 ;
        RECT 0.000 160.320 0.192 160.344 ;
    END
  END wo_d[21]
  PIN wo_d[22]
    DIRECTION OUTPUT ;
    USE SIGNAL ;
    PORT
      LAYER M4 ;
        RECT 0.000 161.040 0.192 161.064 ;
    END
  END wo_d[22]
  PIN wo_d[23]
    DIRECTION OUTPUT ;
    USE SIGNAL ;
    PORT
      LAYER M4 ;
        RECT 0.000 161.760 0.192 161.784 ;
    END
  END wo_d[23]
  PIN wo_d[24]
    DIRECTION OUTPUT ;
    USE SIGNAL ;
    PORT
      LAYER M4 ;
        RECT 0.000 162.480 0.192 162.504 ;
    END
  END wo_d[24]
  PIN wo_d[25]
    DIRECTION OUTPUT ;
    USE SIGNAL ;
    PORT
      LAYER M4 ;
        RECT 0.000 163.200 0.192 163.224 ;
    END
  END wo_d[25]
  PIN wo_d[26]
    DIRECTION OUTPUT ;
    USE SIGNAL ;
    PORT
      LAYER M4 ;
        RECT 0.000 163.920 0.192 163.944 ;
    END
  END wo_d[26]
  PIN wo_d[27]
    DIRECTION OUTPUT ;
    USE SIGNAL ;
    PORT
      LAYER M4 ;
        RECT 0.000 164.688 0.192 164.712 ;
    END
  END wo_d[27]
  PIN wo_d[28]
    DIRECTION OUTPUT ;
    USE SIGNAL ;
    PORT
      LAYER M4 ;
        RECT 0.000 165.408 0.192 165.432 ;
    END
  END wo_d[28]
  PIN wo_d[29]
    DIRECTION OUTPUT ;
    USE SIGNAL ;
    PORT
      LAYER M4 ;
        RECT 0.000 166.128 0.192 166.152 ;
    END
  END wo_d[29]
  PIN wo_d[30]
    DIRECTION OUTPUT ;
    USE SIGNAL ;
    PORT
      LAYER M4 ;
        RECT 0.000 166.848 0.192 166.872 ;
    END
  END wo_d[30]
  PIN wo_d[31]
    DIRECTION OUTPUT ;
    USE SIGNAL ;
    PORT
      LAYER M4 ;
        RECT 0.000 167.568 0.192 167.592 ;
    END
  END wo_d[31]
  PIN wo_d[32]
    DIRECTION OUTPUT ;
    USE SIGNAL ;
    PORT
      LAYER M4 ;
        RECT 0.000 168.288 0.192 168.312 ;
    END
  END wo_d[32]
  PIN wo_d[33]
    DIRECTION OUTPUT ;
    USE SIGNAL ;
    PORT
      LAYER M4 ;
        RECT 0.000 169.008 0.192 169.032 ;
    END
  END wo_d[33]
  PIN wo_d[34]
    DIRECTION OUTPUT ;
    USE SIGNAL ;
    PORT
      LAYER M4 ;
        RECT 0.000 169.728 0.192 169.752 ;
    END
  END wo_d[34]
  PIN wo_d[35]
    DIRECTION OUTPUT ;
    USE SIGNAL ;
    PORT
      LAYER M4 ;
        RECT 0.000 170.448 0.192 170.472 ;
    END
  END wo_d[35]
  PIN wo_d[36]
    DIRECTION OUTPUT ;
    USE SIGNAL ;
    PORT
      LAYER M4 ;
        RECT 0.000 171.168 0.192 171.192 ;
    END
  END wo_d[36]
  PIN wo_d[37]
    DIRECTION OUTPUT ;
    USE SIGNAL ;
    PORT
      LAYER M4 ;
        RECT 0.000 171.936 0.192 171.960 ;
    END
  END wo_d[37]
  PIN wo_d[38]
    DIRECTION OUTPUT ;
    USE SIGNAL ;
    PORT
      LAYER M4 ;
        RECT 0.000 172.656 0.192 172.680 ;
    END
  END wo_d[38]
  PIN wo_d[39]
    DIRECTION OUTPUT ;
    USE SIGNAL ;
    PORT
      LAYER M4 ;
        RECT 0.000 173.376 0.192 173.400 ;
    END
  END wo_d[39]
  PIN wo_d[40]
    DIRECTION OUTPUT ;
    USE SIGNAL ;
    PORT
      LAYER M4 ;
        RECT 0.000 174.096 0.192 174.120 ;
    END
  END wo_d[40]
  PIN wo_d[41]
    DIRECTION OUTPUT ;
    USE SIGNAL ;
    PORT
      LAYER M4 ;
        RECT 0.000 174.816 0.192 174.840 ;
    END
  END wo_d[41]
  PIN wo_d[42]
    DIRECTION OUTPUT ;
    USE SIGNAL ;
    PORT
      LAYER M4 ;
        RECT 0.000 175.536 0.192 175.560 ;
    END
  END wo_d[42]
  PIN wo_d[43]
    DIRECTION OUTPUT ;
    USE SIGNAL ;
    PORT
      LAYER M4 ;
        RECT 0.000 176.256 0.192 176.280 ;
    END
  END wo_d[43]
  PIN wo_d[44]
    DIRECTION OUTPUT ;
    USE SIGNAL ;
    PORT
      LAYER M4 ;
        RECT 0.000 176.976 0.192 177.000 ;
    END
  END wo_d[44]
  PIN wo_d[45]
    DIRECTION OUTPUT ;
    USE SIGNAL ;
    PORT
      LAYER M4 ;
        RECT 0.000 177.696 0.192 177.720 ;
    END
  END wo_d[45]
  PIN wo_d[46]
    DIRECTION OUTPUT ;
    USE SIGNAL ;
    PORT
      LAYER M4 ;
        RECT 0.000 178.416 0.192 178.440 ;
    END
  END wo_d[46]
  PIN wo_d[47]
    DIRECTION OUTPUT ;
    USE SIGNAL ;
    PORT
      LAYER M4 ;
        RECT 0.000 179.136 0.192 179.160 ;
    END
  END wo_d[47]
  PIN wo_d[48]
    DIRECTION OUTPUT ;
    USE SIGNAL ;
    PORT
      LAYER M4 ;
        RECT 0.000 179.904 0.192 179.928 ;
    END
  END wo_d[48]
  PIN wo_d[49]
    DIRECTION OUTPUT ;
    USE SIGNAL ;
    PORT
      LAYER M4 ;
        RECT 0.000 180.624 0.192 180.648 ;
    END
  END wo_d[49]
  PIN wo_d[50]
    DIRECTION OUTPUT ;
    USE SIGNAL ;
    PORT
      LAYER M4 ;
        RECT 0.000 181.344 0.192 181.368 ;
    END
  END wo_d[50]
  PIN wo_d[51]
    DIRECTION OUTPUT ;
    USE SIGNAL ;
    PORT
      LAYER M4 ;
        RECT 0.000 182.064 0.192 182.088 ;
    END
  END wo_d[51]
  PIN wo_d[52]
    DIRECTION OUTPUT ;
    USE SIGNAL ;
    PORT
      LAYER M4 ;
        RECT 0.000 182.784 0.192 182.808 ;
    END
  END wo_d[52]
  PIN wo_d[53]
    DIRECTION OUTPUT ;
    USE SIGNAL ;
    PORT
      LAYER M4 ;
        RECT 0.000 183.504 0.192 183.528 ;
    END
  END wo_d[53]
  PIN wo_d[54]
    DIRECTION OUTPUT ;
    USE SIGNAL ;
    PORT
      LAYER M4 ;
        RECT 0.000 184.224 0.192 184.248 ;
    END
  END wo_d[54]
  PIN wo_d[55]
    DIRECTION OUTPUT ;
    USE SIGNAL ;
    PORT
      LAYER M4 ;
        RECT 0.000 184.944 0.192 184.968 ;
    END
  END wo_d[55]
  PIN wo_d[56]
    DIRECTION OUTPUT ;
    USE SIGNAL ;
    PORT
      LAYER M4 ;
        RECT 0.000 185.664 0.192 185.688 ;
    END
  END wo_d[56]
  PIN wo_d[57]
    DIRECTION OUTPUT ;
    USE SIGNAL ;
    PORT
      LAYER M4 ;
        RECT 0.000 186.384 0.192 186.408 ;
    END
  END wo_d[57]
  PIN wo_d[58]
    DIRECTION OUTPUT ;
    USE SIGNAL ;
    PORT
      LAYER M4 ;
        RECT 0.000 187.152 0.192 187.176 ;
    END
  END wo_d[58]
  PIN wo_d[59]
    DIRECTION OUTPUT ;
    USE SIGNAL ;
    PORT
      LAYER M4 ;
        RECT 0.000 187.872 0.192 187.896 ;
    END
  END wo_d[59]
  PIN wo_d[60]
    DIRECTION OUTPUT ;
    USE SIGNAL ;
    PORT
      LAYER M4 ;
        RECT 0.000 188.592 0.192 188.616 ;
    END
  END wo_d[60]
  PIN wo_d[61]
    DIRECTION OUTPUT ;
    USE SIGNAL ;
    PORT
      LAYER M4 ;
        RECT 0.000 189.312 0.192 189.336 ;
    END
  END wo_d[61]
  PIN wo_d[62]
    DIRECTION OUTPUT ;
    USE SIGNAL ;
    PORT
      LAYER M4 ;
        RECT 0.000 190.032 0.192 190.056 ;
    END
  END wo_d[62]
  PIN wo_d[63]
    DIRECTION OUTPUT ;
    USE SIGNAL ;
    PORT
      LAYER M4 ;
        RECT 0.000 190.752 0.192 190.776 ;
    END
  END wo_d[63]
  PIN wo_d[64]
    DIRECTION OUTPUT ;
    USE SIGNAL ;
    PORT
      LAYER M4 ;
        RECT 0.000 191.472 0.192 191.496 ;
    END
  END wo_d[64]
  PIN wo_d[65]
    DIRECTION OUTPUT ;
    USE SIGNAL ;
    PORT
      LAYER M4 ;
        RECT 0.000 192.192 0.192 192.216 ;
    END
  END wo_d[65]
  PIN wo_d[66]
    DIRECTION OUTPUT ;
    USE SIGNAL ;
    PORT
      LAYER M4 ;
        RECT 0.000 192.912 0.192 192.936 ;
    END
  END wo_d[66]
  PIN wo_d[67]
    DIRECTION OUTPUT ;
    USE SIGNAL ;
    PORT
      LAYER M4 ;
        RECT 0.000 193.632 0.192 193.656 ;
    END
  END wo_d[67]
  PIN wo_d[68]
    DIRECTION OUTPUT ;
    USE SIGNAL ;
    PORT
      LAYER M4 ;
        RECT 0.000 194.400 0.192 194.424 ;
    END
  END wo_d[68]
  PIN wo_d[69]
    DIRECTION OUTPUT ;
    USE SIGNAL ;
    PORT
      LAYER M4 ;
        RECT 0.000 195.120 0.192 195.144 ;
    END
  END wo_d[69]
  PIN wo_d[70]
    DIRECTION OUTPUT ;
    USE SIGNAL ;
    PORT
      LAYER M4 ;
        RECT 0.000 195.840 0.192 195.864 ;
    END
  END wo_d[70]
  PIN wo_d[71]
    DIRECTION OUTPUT ;
    USE SIGNAL ;
    PORT
      LAYER M4 ;
        RECT 0.000 196.560 0.192 196.584 ;
    END
  END wo_d[71]
  PIN wo_d[72]
    DIRECTION OUTPUT ;
    USE SIGNAL ;
    PORT
      LAYER M4 ;
        RECT 0.000 197.280 0.192 197.304 ;
    END
  END wo_d[72]
  PIN wo_d[73]
    DIRECTION OUTPUT ;
    USE SIGNAL ;
    PORT
      LAYER M4 ;
        RECT 0.000 198.000 0.192 198.024 ;
    END
  END wo_d[73]
  PIN wo_d[74]
    DIRECTION OUTPUT ;
    USE SIGNAL ;
    PORT
      LAYER M4 ;
        RECT 0.000 198.720 0.192 198.744 ;
    END
  END wo_d[74]
  PIN wo_d[75]
    DIRECTION OUTPUT ;
    USE SIGNAL ;
    PORT
      LAYER M4 ;
        RECT 0.000 199.440 0.192 199.464 ;
    END
  END wo_d[75]
  PIN wo_d[76]
    DIRECTION OUTPUT ;
    USE SIGNAL ;
    PORT
      LAYER M4 ;
        RECT 0.000 200.160 0.192 200.184 ;
    END
  END wo_d[76]
  PIN wo_d[77]
    DIRECTION OUTPUT ;
    USE SIGNAL ;
    PORT
      LAYER M4 ;
        RECT 0.000 200.880 0.192 200.904 ;
    END
  END wo_d[77]
  PIN wo_d[78]
    DIRECTION OUTPUT ;
    USE SIGNAL ;
    PORT
      LAYER M4 ;
        RECT 0.000 201.648 0.192 201.672 ;
    END
  END wo_d[78]
  PIN wo_d[79]
    DIRECTION OUTPUT ;
    USE SIGNAL ;
    PORT
      LAYER M4 ;
        RECT 0.000 202.368 0.192 202.392 ;
    END
  END wo_d[79]
  PIN wo_d[80]
    DIRECTION OUTPUT ;
    USE SIGNAL ;
    PORT
      LAYER M4 ;
        RECT 0.000 203.088 0.192 203.112 ;
    END
  END wo_d[80]
  PIN wo_d[81]
    DIRECTION OUTPUT ;
    USE SIGNAL ;
    PORT
      LAYER M4 ;
        RECT 0.000 203.808 0.192 203.832 ;
    END
  END wo_d[81]
  PIN wo_d[82]
    DIRECTION OUTPUT ;
    USE SIGNAL ;
    PORT
      LAYER M4 ;
        RECT 0.000 204.528 0.192 204.552 ;
    END
  END wo_d[82]
  PIN wo_d[83]
    DIRECTION OUTPUT ;
    USE SIGNAL ;
    PORT
      LAYER M4 ;
        RECT 0.000 205.248 0.192 205.272 ;
    END
  END wo_d[83]
  PIN wo_d[84]
    DIRECTION OUTPUT ;
    USE SIGNAL ;
    PORT
      LAYER M4 ;
        RECT 0.000 205.968 0.192 205.992 ;
    END
  END wo_d[84]
  PIN wo_d[85]
    DIRECTION OUTPUT ;
    USE SIGNAL ;
    PORT
      LAYER M4 ;
        RECT 0.000 206.688 0.192 206.712 ;
    END
  END wo_d[85]
  PIN wo_d[86]
    DIRECTION OUTPUT ;
    USE SIGNAL ;
    PORT
      LAYER M4 ;
        RECT 0.000 207.408 0.192 207.432 ;
    END
  END wo_d[86]
  PIN wo_d[87]
    DIRECTION OUTPUT ;
    USE SIGNAL ;
    PORT
      LAYER M4 ;
        RECT 0.000 208.128 0.192 208.152 ;
    END
  END wo_d[87]
  PIN wo_d[88]
    DIRECTION OUTPUT ;
    USE SIGNAL ;
    PORT
      LAYER M4 ;
        RECT 0.000 208.896 0.192 208.920 ;
    END
  END wo_d[88]
  PIN wo_d[89]
    DIRECTION OUTPUT ;
    USE SIGNAL ;
    PORT
      LAYER M4 ;
        RECT 0.000 209.616 0.192 209.640 ;
    END
  END wo_d[89]
  PIN wo_d[90]
    DIRECTION OUTPUT ;
    USE SIGNAL ;
    PORT
      LAYER M4 ;
        RECT 0.000 210.336 0.192 210.360 ;
    END
  END wo_d[90]
  PIN wo_d[91]
    DIRECTION OUTPUT ;
    USE SIGNAL ;
    PORT
      LAYER M4 ;
        RECT 0.000 211.056 0.192 211.080 ;
    END
  END wo_d[91]
  PIN wo_d[92]
    DIRECTION OUTPUT ;
    USE SIGNAL ;
    PORT
      LAYER M4 ;
        RECT 0.000 211.776 0.192 211.800 ;
    END
  END wo_d[92]
  PIN wo_d[93]
    DIRECTION OUTPUT ;
    USE SIGNAL ;
    PORT
      LAYER M4 ;
        RECT 0.000 212.496 0.192 212.520 ;
    END
  END wo_d[93]
  PIN wo_d[94]
    DIRECTION OUTPUT ;
    USE SIGNAL ;
    PORT
      LAYER M4 ;
        RECT 0.000 213.216 0.192 213.240 ;
    END
  END wo_d[94]
  PIN wo_d[95]
    DIRECTION OUTPUT ;
    USE SIGNAL ;
    PORT
      LAYER M4 ;
        RECT 0.000 213.936 0.192 213.960 ;
    END
  END wo_d[95]
  PIN wo_d[96]
    DIRECTION OUTPUT ;
    USE SIGNAL ;
    PORT
      LAYER M4 ;
        RECT 0.000 214.656 0.192 214.680 ;
    END
  END wo_d[96]
  PIN wo_d[97]
    DIRECTION OUTPUT ;
    USE SIGNAL ;
    PORT
      LAYER M4 ;
        RECT 0.000 215.376 0.192 215.400 ;
    END
  END wo_d[97]
  PIN wo_d[98]
    DIRECTION OUTPUT ;
    USE SIGNAL ;
    PORT
      LAYER M4 ;
        RECT 0.000 216.144 0.192 216.168 ;
    END
  END wo_d[98]
  PIN wo_d[99]
    DIRECTION OUTPUT ;
    USE SIGNAL ;
    PORT
      LAYER M4 ;
        RECT 0.000 216.864 0.192 216.888 ;
    END
  END wo_d[99]
  PIN wo_d[100]
    DIRECTION OUTPUT ;
    USE SIGNAL ;
    PORT
      LAYER M4 ;
        RECT 0.000 217.584 0.192 217.608 ;
    END
  END wo_d[100]
  PIN wo_d[101]
    DIRECTION OUTPUT ;
    USE SIGNAL ;
    PORT
      LAYER M4 ;
        RECT 0.000 218.304 0.192 218.328 ;
    END
  END wo_d[101]
  PIN wo_d[102]
    DIRECTION OUTPUT ;
    USE SIGNAL ;
    PORT
      LAYER M4 ;
        RECT 0.000 219.024 0.192 219.048 ;
    END
  END wo_d[102]
  PIN wo_d[103]
    DIRECTION OUTPUT ;
    USE SIGNAL ;
    PORT
      LAYER M4 ;
        RECT 0.000 219.744 0.192 219.768 ;
    END
  END wo_d[103]
  PIN wo_d[104]
    DIRECTION OUTPUT ;
    USE SIGNAL ;
    PORT
      LAYER M4 ;
        RECT 0.000 220.464 0.192 220.488 ;
    END
  END wo_d[104]
  PIN wo_d[105]
    DIRECTION OUTPUT ;
    USE SIGNAL ;
    PORT
      LAYER M4 ;
        RECT 0.000 221.184 0.192 221.208 ;
    END
  END wo_d[105]
  PIN wo_d[106]
    DIRECTION OUTPUT ;
    USE SIGNAL ;
    PORT
      LAYER M4 ;
        RECT 0.000 221.904 0.192 221.928 ;
    END
  END wo_d[106]
  PIN wo_d[107]
    DIRECTION OUTPUT ;
    USE SIGNAL ;
    PORT
      LAYER M4 ;
        RECT 0.000 222.624 0.192 222.648 ;
    END
  END wo_d[107]
  PIN wo_d[108]
    DIRECTION OUTPUT ;
    USE SIGNAL ;
    PORT
      LAYER M4 ;
        RECT 0.000 223.392 0.192 223.416 ;
    END
  END wo_d[108]
  PIN wo_d[109]
    DIRECTION OUTPUT ;
    USE SIGNAL ;
    PORT
      LAYER M4 ;
        RECT 0.000 224.112 0.192 224.136 ;
    END
  END wo_d[109]
  PIN wo_d[110]
    DIRECTION OUTPUT ;
    USE SIGNAL ;
    PORT
      LAYER M4 ;
        RECT 0.000 224.832 0.192 224.856 ;
    END
  END wo_d[110]
  PIN wo_d[111]
    DIRECTION OUTPUT ;
    USE SIGNAL ;
    PORT
      LAYER M4 ;
        RECT 0.000 225.552 0.192 225.576 ;
    END
  END wo_d[111]
  PIN wo_d[112]
    DIRECTION OUTPUT ;
    USE SIGNAL ;
    PORT
      LAYER M4 ;
        RECT 0.000 226.272 0.192 226.296 ;
    END
  END wo_d[112]
  PIN wo_d[113]
    DIRECTION OUTPUT ;
    USE SIGNAL ;
    PORT
      LAYER M4 ;
        RECT 0.000 226.992 0.192 227.016 ;
    END
  END wo_d[113]
  PIN wo_d[114]
    DIRECTION OUTPUT ;
    USE SIGNAL ;
    PORT
      LAYER M4 ;
        RECT 0.000 227.712 0.192 227.736 ;
    END
  END wo_d[114]
  PIN wo_d[115]
    DIRECTION OUTPUT ;
    USE SIGNAL ;
    PORT
      LAYER M4 ;
        RECT 0.000 228.432 0.192 228.456 ;
    END
  END wo_d[115]
  PIN wo_d[116]
    DIRECTION OUTPUT ;
    USE SIGNAL ;
    PORT
      LAYER M4 ;
        RECT 0.000 229.152 0.192 229.176 ;
    END
  END wo_d[116]
  PIN wo_d[117]
    DIRECTION OUTPUT ;
    USE SIGNAL ;
    PORT
      LAYER M4 ;
        RECT 0.000 229.872 0.192 229.896 ;
    END
  END wo_d[117]
  PIN wo_d[118]
    DIRECTION OUTPUT ;
    USE SIGNAL ;
    PORT
      LAYER M4 ;
        RECT 0.000 230.640 0.192 230.664 ;
    END
  END wo_d[118]
  PIN wo_d[119]
    DIRECTION OUTPUT ;
    USE SIGNAL ;
    PORT
      LAYER M4 ;
        RECT 0.000 231.360 0.192 231.384 ;
    END
  END wo_d[119]
  PIN wo_d[120]
    DIRECTION OUTPUT ;
    USE SIGNAL ;
    PORT
      LAYER M4 ;
        RECT 0.000 232.080 0.192 232.104 ;
    END
  END wo_d[120]
  PIN wo_d[121]
    DIRECTION OUTPUT ;
    USE SIGNAL ;
    PORT
      LAYER M4 ;
        RECT 0.000 232.800 0.192 232.824 ;
    END
  END wo_d[121]
  PIN wo_d[122]
    DIRECTION OUTPUT ;
    USE SIGNAL ;
    PORT
      LAYER M4 ;
        RECT 0.000 233.520 0.192 233.544 ;
    END
  END wo_d[122]
  PIN wo_d[123]
    DIRECTION OUTPUT ;
    USE SIGNAL ;
    PORT
      LAYER M4 ;
        RECT 0.000 234.240 0.192 234.264 ;
    END
  END wo_d[123]
  PIN wo_d[124]
    DIRECTION OUTPUT ;
    USE SIGNAL ;
    PORT
      LAYER M4 ;
        RECT 0.000 234.960 0.192 234.984 ;
    END
  END wo_d[124]
  PIN wo_d[125]
    DIRECTION OUTPUT ;
    USE SIGNAL ;
    PORT
      LAYER M4 ;
        RECT 0.000 235.680 0.192 235.704 ;
    END
  END wo_d[125]
  PIN wo_d[126]
    DIRECTION OUTPUT ;
    USE SIGNAL ;
    PORT
      LAYER M4 ;
        RECT 0.000 236.400 0.192 236.424 ;
    END
  END wo_d[126]
  PIN wo_d[127]
    DIRECTION OUTPUT ;
    USE SIGNAL ;
    PORT
      LAYER M4 ;
        RECT 0.000 237.120 0.192 237.144 ;
    END
  END wo_d[127]
  PIN wo_d[128]
    DIRECTION OUTPUT ;
    USE SIGNAL ;
    PORT
      LAYER M4 ;
        RECT 0.000 237.888 0.192 237.912 ;
    END
  END wo_d[128]
  PIN wo_d[129]
    DIRECTION OUTPUT ;
    USE SIGNAL ;
    PORT
      LAYER M4 ;
        RECT 0.000 238.608 0.192 238.632 ;
    END
  END wo_d[129]
  PIN wo_d[130]
    DIRECTION OUTPUT ;
    USE SIGNAL ;
    PORT
      LAYER M4 ;
        RECT 0.000 239.328 0.192 239.352 ;
    END
  END wo_d[130]
  PIN wo_d[131]
    DIRECTION OUTPUT ;
    USE SIGNAL ;
    PORT
      LAYER M4 ;
        RECT 0.000 240.048 0.192 240.072 ;
    END
  END wo_d[131]
  PIN wo_d[132]
    DIRECTION OUTPUT ;
    USE SIGNAL ;
    PORT
      LAYER M4 ;
        RECT 0.000 240.768 0.192 240.792 ;
    END
  END wo_d[132]
  PIN wo_d[133]
    DIRECTION OUTPUT ;
    USE SIGNAL ;
    PORT
      LAYER M4 ;
        RECT 0.000 241.488 0.192 241.512 ;
    END
  END wo_d[133]
  PIN wo_d[134]
    DIRECTION OUTPUT ;
    USE SIGNAL ;
    PORT
      LAYER M4 ;
        RECT 0.000 242.208 0.192 242.232 ;
    END
  END wo_d[134]
  PIN wo_d[135]
    DIRECTION OUTPUT ;
    USE SIGNAL ;
    PORT
      LAYER M4 ;
        RECT 0.000 242.928 0.192 242.952 ;
    END
  END wo_d[135]
  PIN wo_d[136]
    DIRECTION OUTPUT ;
    USE SIGNAL ;
    PORT
      LAYER M4 ;
        RECT 0.000 243.648 0.192 243.672 ;
    END
  END wo_d[136]
  PIN wo_d[137]
    DIRECTION OUTPUT ;
    USE SIGNAL ;
    PORT
      LAYER M4 ;
        RECT 0.000 244.368 0.192 244.392 ;
    END
  END wo_d[137]
  PIN wo_d[138]
    DIRECTION OUTPUT ;
    USE SIGNAL ;
    PORT
      LAYER M4 ;
        RECT 0.000 245.136 0.192 245.160 ;
    END
  END wo_d[138]
  PIN wo_d[139]
    DIRECTION OUTPUT ;
    USE SIGNAL ;
    PORT
      LAYER M4 ;
        RECT 0.000 245.856 0.192 245.880 ;
    END
  END wo_d[139]
  PIN wo_d[140]
    DIRECTION OUTPUT ;
    USE SIGNAL ;
    PORT
      LAYER M4 ;
        RECT 0.000 246.576 0.192 246.600 ;
    END
  END wo_d[140]
  PIN wo_d[141]
    DIRECTION OUTPUT ;
    USE SIGNAL ;
    PORT
      LAYER M4 ;
        RECT 0.000 247.296 0.192 247.320 ;
    END
  END wo_d[141]
  PIN wo_d[142]
    DIRECTION OUTPUT ;
    USE SIGNAL ;
    PORT
      LAYER M4 ;
        RECT 0.000 248.016 0.192 248.040 ;
    END
  END wo_d[142]
  PIN wo_d[143]
    DIRECTION OUTPUT ;
    USE SIGNAL ;
    PORT
      LAYER M4 ;
        RECT 0.000 248.736 0.192 248.760 ;
    END
  END wo_d[143]
  PIN wo_d[144]
    DIRECTION OUTPUT ;
    USE SIGNAL ;
    PORT
      LAYER M4 ;
        RECT 0.000 249.456 0.192 249.480 ;
    END
  END wo_d[144]
  PIN wo_d[145]
    DIRECTION OUTPUT ;
    USE SIGNAL ;
    PORT
      LAYER M4 ;
        RECT 0.000 250.176 0.192 250.200 ;
    END
  END wo_d[145]
  PIN wo_d[146]
    DIRECTION OUTPUT ;
    USE SIGNAL ;
    PORT
      LAYER M4 ;
        RECT 0.000 250.896 0.192 250.920 ;
    END
  END wo_d[146]
  PIN wo_d[147]
    DIRECTION OUTPUT ;
    USE SIGNAL ;
    PORT
      LAYER M4 ;
        RECT 0.000 251.616 0.192 251.640 ;
    END
  END wo_d[147]
  PIN wo_d[148]
    DIRECTION OUTPUT ;
    USE SIGNAL ;
    PORT
      LAYER M4 ;
        RECT 0.000 252.384 0.192 252.408 ;
    END
  END wo_d[148]
  PIN wo_d[149]
    DIRECTION OUTPUT ;
    USE SIGNAL ;
    PORT
      LAYER M4 ;
        RECT 0.000 253.104 0.192 253.128 ;
    END
  END wo_d[149]
  PIN wo_d[150]
    DIRECTION OUTPUT ;
    USE SIGNAL ;
    PORT
      LAYER M4 ;
        RECT 0.000 253.824 0.192 253.848 ;
    END
  END wo_d[150]
  PIN wo_d[151]
    DIRECTION OUTPUT ;
    USE SIGNAL ;
    PORT
      LAYER M4 ;
        RECT 0.000 254.544 0.192 254.568 ;
    END
  END wo_d[151]
  PIN wo_d[152]
    DIRECTION OUTPUT ;
    USE SIGNAL ;
    PORT
      LAYER M4 ;
        RECT 0.000 255.264 0.192 255.288 ;
    END
  END wo_d[152]
  PIN wo_d[153]
    DIRECTION OUTPUT ;
    USE SIGNAL ;
    PORT
      LAYER M4 ;
        RECT 0.000 255.984 0.192 256.008 ;
    END
  END wo_d[153]
  PIN wo_d[154]
    DIRECTION OUTPUT ;
    USE SIGNAL ;
    PORT
      LAYER M4 ;
        RECT 0.000 256.704 0.192 256.728 ;
    END
  END wo_d[154]
  PIN wo_d[155]
    DIRECTION OUTPUT ;
    USE SIGNAL ;
    PORT
      LAYER M4 ;
        RECT 0.000 257.424 0.192 257.448 ;
    END
  END wo_d[155]
  PIN wo_d[156]
    DIRECTION OUTPUT ;
    USE SIGNAL ;
    PORT
      LAYER M4 ;
        RECT 0.000 258.144 0.192 258.168 ;
    END
  END wo_d[156]
  PIN wo_d[157]
    DIRECTION OUTPUT ;
    USE SIGNAL ;
    PORT
      LAYER M4 ;
        RECT 0.000 258.864 0.192 258.888 ;
    END
  END wo_d[157]
  PIN wo_d[158]
    DIRECTION OUTPUT ;
    USE SIGNAL ;
    PORT
      LAYER M4 ;
        RECT 0.000 259.632 0.192 259.656 ;
    END
  END wo_d[158]
  PIN wo_d[159]
    DIRECTION OUTPUT ;
    USE SIGNAL ;
    PORT
      LAYER M4 ;
        RECT 0.000 260.352 0.192 260.376 ;
    END
  END wo_d[159]
  PIN e_v
    DIRECTION OUTPUT ;
    USE SIGNAL ;
    PORT
      LAYER M4 ;
        RECT 0.000 265.872 0.192 265.896 ;
    END
  END e_v
  PIN e_c[0]
    DIRECTION OUTPUT ;
    USE SIGNAL ;
    PORT
      LAYER M4 ;
        RECT 0.000 267.696 0.192 267.720 ;
    END
  END e_c[0]
  PIN e_c[1]
    DIRECTION OUTPUT ;
    USE SIGNAL ;
    PORT
      LAYER M4 ;
        RECT 0.000 268.896 0.192 268.920 ;
    END
  END e_c[1]
  PIN e_hh[0]
    DIRECTION OUTPUT ;
    USE SIGNAL ;
    PORT
      LAYER M4 ;
        RECT 0.000 269.904 0.192 269.928 ;
    END
  END e_hh[0]
  PIN e_hh[1]
    DIRECTION OUTPUT ;
    USE SIGNAL ;
    PORT
      LAYER M4 ;
        RECT 0.000 270.624 0.192 270.648 ;
    END
  END e_hh[1]
  PIN e_hh[2]
    DIRECTION OUTPUT ;
    USE SIGNAL ;
    PORT
      LAYER M4 ;
        RECT 0.000 271.344 0.192 271.368 ;
    END
  END e_hh[2]
  PIN e_hh[3]
    DIRECTION OUTPUT ;
    USE SIGNAL ;
    PORT
      LAYER M4 ;
        RECT 0.000 272.064 0.192 272.088 ;
    END
  END e_hh[3]
  PIN e_hh[4]
    DIRECTION OUTPUT ;
    USE SIGNAL ;
    PORT
      LAYER M4 ;
        RECT 0.000 272.784 0.192 272.808 ;
    END
  END e_hh[4]
  PIN e_hh[5]
    DIRECTION OUTPUT ;
    USE SIGNAL ;
    PORT
      LAYER M4 ;
        RECT 0.000 273.504 0.192 273.528 ;
    END
  END e_hh[5]
  PIN e_hh[6]
    DIRECTION OUTPUT ;
    USE SIGNAL ;
    PORT
      LAYER M4 ;
        RECT 0.000 274.224 0.192 274.248 ;
    END
  END e_hh[6]
  PIN e_hh[7]
    DIRECTION OUTPUT ;
    USE SIGNAL ;
    PORT
      LAYER M4 ;
        RECT 0.000 274.944 0.192 274.968 ;
    END
  END e_hh[7]
  PIN e_hh[8]
    DIRECTION OUTPUT ;
    USE SIGNAL ;
    PORT
      LAYER M4 ;
        RECT 0.000 275.712 0.192 275.736 ;
    END
  END e_hh[8]
  PIN e_hh[9]
    DIRECTION OUTPUT ;
    USE SIGNAL ;
    PORT
      LAYER M4 ;
        RECT 0.000 276.432 0.192 276.456 ;
    END
  END e_hh[9]
  PIN e_hh[10]
    DIRECTION OUTPUT ;
    USE SIGNAL ;
    PORT
      LAYER M4 ;
        RECT 0.000 277.152 0.192 277.176 ;
    END
  END e_hh[10]
  PIN e_hh[11]
    DIRECTION OUTPUT ;
    USE SIGNAL ;
    PORT
      LAYER M4 ;
        RECT 0.000 277.872 0.192 277.896 ;
    END
  END e_hh[11]
  PIN e_hh[12]
    DIRECTION OUTPUT ;
    USE SIGNAL ;
    PORT
      LAYER M4 ;
        RECT 0.000 278.592 0.192 278.616 ;
    END
  END e_hh[12]
  PIN e_hh[13]
    DIRECTION OUTPUT ;
    USE SIGNAL ;
    PORT
      LAYER M4 ;
        RECT 0.000 279.312 0.192 279.336 ;
    END
  END e_hh[13]
  PIN e_hh[14]
    DIRECTION OUTPUT ;
    USE SIGNAL ;
    PORT
      LAYER M4 ;
        RECT 0.000 280.032 0.192 280.056 ;
    END
  END e_hh[14]
  PIN e_hh[15]
    DIRECTION OUTPUT ;
    USE SIGNAL ;
    PORT
      LAYER M4 ;
        RECT 0.000 280.752 0.192 280.776 ;
    END
  END e_hh[15]
  PIN e_hh[16]
    DIRECTION OUTPUT ;
    USE SIGNAL ;
    PORT
      LAYER M4 ;
        RECT 0.000 281.472 0.192 281.496 ;
    END
  END e_hh[16]
  PIN e_hh[17]
    DIRECTION OUTPUT ;
    USE SIGNAL ;
    PORT
      LAYER M4 ;
        RECT 0.000 282.192 0.192 282.216 ;
    END
  END e_hh[17]
  PIN e_hh[18]
    DIRECTION OUTPUT ;
    USE SIGNAL ;
    PORT
      LAYER M4 ;
        RECT 0.000 282.960 0.192 282.984 ;
    END
  END e_hh[18]
  PIN e_hh[19]
    DIRECTION OUTPUT ;
    USE SIGNAL ;
    PORT
      LAYER M4 ;
        RECT 0.000 283.680 0.192 283.704 ;
    END
  END e_hh[19]
  PIN e_hh[20]
    DIRECTION OUTPUT ;
    USE SIGNAL ;
    PORT
      LAYER M4 ;
        RECT 0.000 284.400 0.192 284.424 ;
    END
  END e_hh[20]
  PIN e_hh[21]
    DIRECTION OUTPUT ;
    USE SIGNAL ;
    PORT
      LAYER M4 ;
        RECT 0.000 285.120 0.192 285.144 ;
    END
  END e_hh[21]
  PIN e_hh[22]
    DIRECTION OUTPUT ;
    USE SIGNAL ;
    PORT
      LAYER M4 ;
        RECT 0.000 285.840 0.192 285.864 ;
    END
  END e_hh[22]
  PIN e_hh[23]
    DIRECTION OUTPUT ;
    USE SIGNAL ;
    PORT
      LAYER M4 ;
        RECT 0.000 286.560 0.192 286.584 ;
    END
  END e_hh[23]
  PIN e_hh[24]
    DIRECTION OUTPUT ;
    USE SIGNAL ;
    PORT
      LAYER M4 ;
        RECT 0.000 287.280 0.192 287.304 ;
    END
  END e_hh[24]
  PIN e_hh[25]
    DIRECTION OUTPUT ;
    USE SIGNAL ;
    PORT
      LAYER M4 ;
        RECT 0.000 288.000 0.192 288.024 ;
    END
  END e_hh[25]
  PIN e_hh[26]
    DIRECTION OUTPUT ;
    USE SIGNAL ;
    PORT
      LAYER M4 ;
        RECT 0.000 288.720 0.192 288.744 ;
    END
  END e_hh[26]
  PIN e_hh[27]
    DIRECTION OUTPUT ;
    USE SIGNAL ;
    PORT
      LAYER M4 ;
        RECT 0.000 289.440 0.192 289.464 ;
    END
  END e_hh[27]
  PIN e_hh[28]
    DIRECTION OUTPUT ;
    USE SIGNAL ;
    PORT
      LAYER M4 ;
        RECT 0.000 290.208 0.192 290.232 ;
    END
  END e_hh[28]
  PIN e_hh[29]
    DIRECTION OUTPUT ;
    USE SIGNAL ;
    PORT
      LAYER M4 ;
        RECT 0.000 290.928 0.192 290.952 ;
    END
  END e_hh[29]
  PIN e_hh[30]
    DIRECTION OUTPUT ;
    USE SIGNAL ;
    PORT
      LAYER M4 ;
        RECT 0.000 291.648 0.192 291.672 ;
    END
  END e_hh[30]
  PIN e_hh[31]
    DIRECTION OUTPUT ;
    USE SIGNAL ;
    PORT
      LAYER M4 ;
        RECT 0.000 292.368 0.192 292.392 ;
    END
  END e_hh[31]
  PIN e_kk[0]
    DIRECTION OUTPUT ;
    USE SIGNAL ;
    PORT
      LAYER M4 ;
        RECT 0.000 293.088 0.192 293.112 ;
    END
  END e_kk[0]
  PIN e_kk[1]
    DIRECTION OUTPUT ;
    USE SIGNAL ;
    PORT
      LAYER M4 ;
        RECT 0.000 293.808 0.192 293.832 ;
    END
  END e_kk[1]
  PIN e_kk[2]
    DIRECTION OUTPUT ;
    USE SIGNAL ;
    PORT
      LAYER M4 ;
        RECT 0.000 294.528 0.192 294.552 ;
    END
  END e_kk[2]
  PIN e_kk[3]
    DIRECTION OUTPUT ;
    USE SIGNAL ;
    PORT
      LAYER M4 ;
        RECT 0.000 295.248 0.192 295.272 ;
    END
  END e_kk[3]
  PIN e_kk[4]
    DIRECTION OUTPUT ;
    USE SIGNAL ;
    PORT
      LAYER M4 ;
        RECT 0.000 295.968 0.192 295.992 ;
    END
  END e_kk[4]
  PIN e_kk[5]
    DIRECTION OUTPUT ;
    USE SIGNAL ;
    PORT
      LAYER M4 ;
        RECT 0.000 296.688 0.192 296.712 ;
    END
  END e_kk[5]
  PIN e_kk[6]
    DIRECTION OUTPUT ;
    USE SIGNAL ;
    PORT
      LAYER M4 ;
        RECT 0.000 297.456 0.192 297.480 ;
    END
  END e_kk[6]
  PIN e_kk[7]
    DIRECTION OUTPUT ;
    USE SIGNAL ;
    PORT
      LAYER M4 ;
        RECT 0.000 298.176 0.192 298.200 ;
    END
  END e_kk[7]
  PIN e_kk[8]
    DIRECTION OUTPUT ;
    USE SIGNAL ;
    PORT
      LAYER M4 ;
        RECT 0.000 298.896 0.192 298.920 ;
    END
  END e_kk[8]
  PIN e_kk[9]
    DIRECTION OUTPUT ;
    USE SIGNAL ;
    PORT
      LAYER M4 ;
        RECT 0.000 299.616 0.192 299.640 ;
    END
  END e_kk[9]
  PIN e_kk[10]
    DIRECTION OUTPUT ;
    USE SIGNAL ;
    PORT
      LAYER M4 ;
        RECT 0.000 300.336 0.192 300.360 ;
    END
  END e_kk[10]
  PIN e_kk[11]
    DIRECTION OUTPUT ;
    USE SIGNAL ;
    PORT
      LAYER M4 ;
        RECT 0.000 301.056 0.192 301.080 ;
    END
  END e_kk[11]
  PIN e_kk[12]
    DIRECTION OUTPUT ;
    USE SIGNAL ;
    PORT
      LAYER M4 ;
        RECT 0.000 301.776 0.192 301.800 ;
    END
  END e_kk[12]
  PIN e_kk[13]
    DIRECTION OUTPUT ;
    USE SIGNAL ;
    PORT
      LAYER M4 ;
        RECT 0.000 302.496 0.192 302.520 ;
    END
  END e_kk[13]
  PIN e_kk[14]
    DIRECTION OUTPUT ;
    USE SIGNAL ;
    PORT
      LAYER M4 ;
        RECT 0.000 303.216 0.192 303.240 ;
    END
  END e_kk[14]
  PIN e_kk[15]
    DIRECTION OUTPUT ;
    USE SIGNAL ;
    PORT
      LAYER M4 ;
        RECT 0.000 303.936 0.192 303.960 ;
    END
  END e_kk[15]
  PIN e_kk[16]
    DIRECTION OUTPUT ;
    USE SIGNAL ;
    PORT
      LAYER M4 ;
        RECT 0.000 304.704 0.192 304.728 ;
    END
  END e_kk[16]
  PIN e_kk[17]
    DIRECTION OUTPUT ;
    USE SIGNAL ;
    PORT
      LAYER M4 ;
        RECT 0.000 305.424 0.192 305.448 ;
    END
  END e_kk[17]
  PIN e_kk[18]
    DIRECTION OUTPUT ;
    USE SIGNAL ;
    PORT
      LAYER M4 ;
        RECT 0.000 306.144 0.192 306.168 ;
    END
  END e_kk[18]
  PIN e_kk[19]
    DIRECTION OUTPUT ;
    USE SIGNAL ;
    PORT
      LAYER M4 ;
        RECT 0.000 306.864 0.192 306.888 ;
    END
  END e_kk[19]
  PIN e_kk[20]
    DIRECTION OUTPUT ;
    USE SIGNAL ;
    PORT
      LAYER M4 ;
        RECT 0.000 307.584 0.192 307.608 ;
    END
  END e_kk[20]
  PIN e_kk[21]
    DIRECTION OUTPUT ;
    USE SIGNAL ;
    PORT
      LAYER M4 ;
        RECT 0.000 308.304 0.192 308.328 ;
    END
  END e_kk[21]
  PIN e_kk[22]
    DIRECTION OUTPUT ;
    USE SIGNAL ;
    PORT
      LAYER M4 ;
        RECT 0.000 309.024 0.192 309.048 ;
    END
  END e_kk[22]
  PIN e_kk[23]
    DIRECTION OUTPUT ;
    USE SIGNAL ;
    PORT
      LAYER M4 ;
        RECT 0.000 309.744 0.192 309.768 ;
    END
  END e_kk[23]
  PIN e_kk[24]
    DIRECTION OUTPUT ;
    USE SIGNAL ;
    PORT
      LAYER M4 ;
        RECT 0.000 310.464 0.192 310.488 ;
    END
  END e_kk[24]
  PIN e_kk[25]
    DIRECTION OUTPUT ;
    USE SIGNAL ;
    PORT
      LAYER M4 ;
        RECT 0.000 311.184 0.192 311.208 ;
    END
  END e_kk[25]
  PIN e_kk[26]
    DIRECTION OUTPUT ;
    USE SIGNAL ;
    PORT
      LAYER M4 ;
        RECT 0.000 311.952 0.192 311.976 ;
    END
  END e_kk[26]
  PIN e_kk[27]
    DIRECTION OUTPUT ;
    USE SIGNAL ;
    PORT
      LAYER M4 ;
        RECT 0.000 312.672 0.192 312.696 ;
    END
  END e_kk[27]
  PIN e_kk[28]
    DIRECTION OUTPUT ;
    USE SIGNAL ;
    PORT
      LAYER M4 ;
        RECT 0.000 313.392 0.192 313.416 ;
    END
  END e_kk[28]
  PIN e_kk[29]
    DIRECTION OUTPUT ;
    USE SIGNAL ;
    PORT
      LAYER M4 ;
        RECT 0.000 314.112 0.192 314.136 ;
    END
  END e_kk[29]
  PIN e_kk[30]
    DIRECTION OUTPUT ;
    USE SIGNAL ;
    PORT
      LAYER M4 ;
        RECT 0.000 314.832 0.192 314.856 ;
    END
  END e_kk[30]
  PIN e_kk[31]
    DIRECTION OUTPUT ;
    USE SIGNAL ;
    PORT
      LAYER M4 ;
        RECT 0.000 315.552 0.192 315.576 ;
    END
  END e_kk[31]
  PIN e_dd[0]
    DIRECTION OUTPUT ;
    USE SIGNAL ;
    PORT
      LAYER M4 ;
        RECT 0.000 316.272 0.192 316.296 ;
    END
  END e_dd[0]
  PIN e_dd[1]
    DIRECTION OUTPUT ;
    USE SIGNAL ;
    PORT
      LAYER M4 ;
        RECT 0.000 316.992 0.192 317.016 ;
    END
  END e_dd[1]
  PIN e_dd[2]
    DIRECTION OUTPUT ;
    USE SIGNAL ;
    PORT
      LAYER M4 ;
        RECT 0.000 317.712 0.192 317.736 ;
    END
  END e_dd[2]
  PIN e_dd[3]
    DIRECTION OUTPUT ;
    USE SIGNAL ;
    PORT
      LAYER M4 ;
        RECT 0.000 318.432 0.192 318.456 ;
    END
  END e_dd[3]
  PIN e_dd[4]
    DIRECTION OUTPUT ;
    USE SIGNAL ;
    PORT
      LAYER M4 ;
        RECT 0.000 319.200 0.192 319.224 ;
    END
  END e_dd[4]
  PIN e_dd[5]
    DIRECTION OUTPUT ;
    USE SIGNAL ;
    PORT
      LAYER M4 ;
        RECT 0.000 319.920 0.192 319.944 ;
    END
  END e_dd[5]
  PIN e_dd[6]
    DIRECTION OUTPUT ;
    USE SIGNAL ;
    PORT
      LAYER M4 ;
        RECT 0.000 320.640 0.192 320.664 ;
    END
  END e_dd[6]
  PIN e_dd[7]
    DIRECTION OUTPUT ;
    USE SIGNAL ;
    PORT
      LAYER M4 ;
        RECT 0.000 321.360 0.192 321.384 ;
    END
  END e_dd[7]
  PIN e_dd[8]
    DIRECTION OUTPUT ;
    USE SIGNAL ;
    PORT
      LAYER M4 ;
        RECT 0.000 322.080 0.192 322.104 ;
    END
  END e_dd[8]
  PIN e_dd[9]
    DIRECTION OUTPUT ;
    USE SIGNAL ;
    PORT
      LAYER M4 ;
        RECT 0.000 322.800 0.192 322.824 ;
    END
  END e_dd[9]
  PIN e_dd[10]
    DIRECTION OUTPUT ;
    USE SIGNAL ;
    PORT
      LAYER M4 ;
        RECT 0.000 323.520 0.192 323.544 ;
    END
  END e_dd[10]
  PIN e_dd[11]
    DIRECTION OUTPUT ;
    USE SIGNAL ;
    PORT
      LAYER M4 ;
        RECT 0.000 324.240 0.192 324.264 ;
    END
  END e_dd[11]
  PIN e_dd[12]
    DIRECTION OUTPUT ;
    USE SIGNAL ;
    PORT
      LAYER M4 ;
        RECT 0.000 324.960 0.192 324.984 ;
    END
  END e_dd[12]
  PIN e_dd[13]
    DIRECTION OUTPUT ;
    USE SIGNAL ;
    PORT
      LAYER M4 ;
        RECT 0.000 325.680 0.192 325.704 ;
    END
  END e_dd[13]
  PIN e_dd[14]
    DIRECTION OUTPUT ;
    USE SIGNAL ;
    PORT
      LAYER M4 ;
        RECT 0.000 326.448 0.192 326.472 ;
    END
  END e_dd[14]
  PIN e_dd[15]
    DIRECTION OUTPUT ;
    USE SIGNAL ;
    PORT
      LAYER M4 ;
        RECT 0.000 327.168 0.192 327.192 ;
    END
  END e_dd[15]
  PIN e_dd[16]
    DIRECTION OUTPUT ;
    USE SIGNAL ;
    PORT
      LAYER M4 ;
        RECT 0.000 327.888 0.192 327.912 ;
    END
  END e_dd[16]
  PIN e_dd[17]
    DIRECTION OUTPUT ;
    USE SIGNAL ;
    PORT
      LAYER M4 ;
        RECT 0.000 328.608 0.192 328.632 ;
    END
  END e_dd[17]
  PIN e_dd[18]
    DIRECTION OUTPUT ;
    USE SIGNAL ;
    PORT
      LAYER M4 ;
        RECT 0.000 329.328 0.192 329.352 ;
    END
  END e_dd[18]
  PIN e_dd[19]
    DIRECTION OUTPUT ;
    USE SIGNAL ;
    PORT
      LAYER M4 ;
        RECT 0.000 330.048 0.192 330.072 ;
    END
  END e_dd[19]
  PIN e_dd[20]
    DIRECTION OUTPUT ;
    USE SIGNAL ;
    PORT
      LAYER M4 ;
        RECT 0.000 330.768 0.192 330.792 ;
    END
  END e_dd[20]
  PIN e_dd[21]
    DIRECTION OUTPUT ;
    USE SIGNAL ;
    PORT
      LAYER M4 ;
        RECT 0.000 331.488 0.192 331.512 ;
    END
  END e_dd[21]
  PIN e_dd[22]
    DIRECTION OUTPUT ;
    USE SIGNAL ;
    PORT
      LAYER M4 ;
        RECT 0.000 332.208 0.192 332.232 ;
    END
  END e_dd[22]
  PIN e_dd[23]
    DIRECTION OUTPUT ;
    USE SIGNAL ;
    PORT
      LAYER M4 ;
        RECT 0.000 332.928 0.192 332.952 ;
    END
  END e_dd[23]
  PIN e_dd[24]
    DIRECTION OUTPUT ;
    USE SIGNAL ;
    PORT
      LAYER M4 ;
        RECT 0.000 333.696 0.192 333.720 ;
    END
  END e_dd[24]
  PIN e_dd[25]
    DIRECTION OUTPUT ;
    USE SIGNAL ;
    PORT
      LAYER M4 ;
        RECT 0.000 334.416 0.192 334.440 ;
    END
  END e_dd[25]
  PIN e_dd[26]
    DIRECTION OUTPUT ;
    USE SIGNAL ;
    PORT
      LAYER M4 ;
        RECT 0.000 335.136 0.192 335.160 ;
    END
  END e_dd[26]
  PIN e_dd[27]
    DIRECTION OUTPUT ;
    USE SIGNAL ;
    PORT
      LAYER M4 ;
        RECT 0.000 335.856 0.192 335.880 ;
    END
  END e_dd[27]
  PIN e_dd[28]
    DIRECTION OUTPUT ;
    USE SIGNAL ;
    PORT
      LAYER M4 ;
        RECT 0.000 336.576 0.192 336.600 ;
    END
  END e_dd[28]
  PIN e_dd[29]
    DIRECTION OUTPUT ;
    USE SIGNAL ;
    PORT
      LAYER M4 ;
        RECT 0.000 337.296 0.192 337.320 ;
    END
  END e_dd[29]
  PIN e_dd[30]
    DIRECTION OUTPUT ;
    USE SIGNAL ;
    PORT
      LAYER M4 ;
        RECT 0.000 338.016 0.192 338.040 ;
    END
  END e_dd[30]
  PIN e_dd[31]
    DIRECTION OUTPUT ;
    USE SIGNAL ;
    PORT
      LAYER M4 ;
        RECT 0.000 338.736 0.192 338.760 ;
    END
  END e_dd[31]
  PIN ei_v
    DIRECTION INPUT ;
    USE SIGNAL ;
    PORT
      LAYER M4 ;
        RECT 345.408 2.640 345.600 2.664 ;
    END
  END ei_v
  PIN ei_h[0]
    DIRECTION INPUT ;
    USE SIGNAL ;
    PORT
      LAYER M4 ;
        RECT 345.408 3.648 345.600 3.672 ;
    END
  END ei_h[0]
  PIN ei_h[1]
    DIRECTION INPUT ;
    USE SIGNAL ;
    PORT
      LAYER M4 ;
        RECT 345.408 4.608 345.600 4.632 ;
    END
  END ei_h[1]
  PIN ei_h[2]
    DIRECTION INPUT ;
    USE SIGNAL ;
    PORT
      LAYER M4 ;
        RECT 345.408 5.616 345.600 5.640 ;
    END
  END ei_h[2]
  PIN ei_h[3]
    DIRECTION INPUT ;
    USE SIGNAL ;
    PORT
      LAYER M4 ;
        RECT 345.408 6.576 345.600 6.600 ;
    END
  END ei_h[3]
  PIN ei_b[0]
    DIRECTION INPUT ;
    USE SIGNAL ;
    PORT
      LAYER M4 ;
        RECT 345.408 7.584 345.600 7.608 ;
    END
  END ei_b[0]
  PIN ei_b[1]
    DIRECTION INPUT ;
    USE SIGNAL ;
    PORT
      LAYER M4 ;
        RECT 345.408 8.544 345.600 8.568 ;
    END
  END ei_b[1]
  PIN ei_b[2]
    DIRECTION INPUT ;
    USE SIGNAL ;
    PORT
      LAYER M4 ;
        RECT 345.408 9.552 345.600 9.576 ;
    END
  END ei_b[2]
  PIN ei_b[3]
    DIRECTION INPUT ;
    USE SIGNAL ;
    PORT
      LAYER M4 ;
        RECT 345.408 10.512 345.600 10.536 ;
    END
  END ei_b[3]
  PIN ei_b[4]
    DIRECTION INPUT ;
    USE SIGNAL ;
    PORT
      LAYER M4 ;
        RECT 345.408 11.520 345.600 11.544 ;
    END
  END ei_b[4]
  PIN ei_b[5]
    DIRECTION INPUT ;
    USE SIGNAL ;
    PORT
      LAYER M4 ;
        RECT 345.408 12.528 345.600 12.552 ;
    END
  END ei_b[5]
  PIN ei_b[6]
    DIRECTION INPUT ;
    USE SIGNAL ;
    PORT
      LAYER M4 ;
        RECT 345.408 13.488 345.600 13.512 ;
    END
  END ei_b[6]
  PIN ei_b[7]
    DIRECTION INPUT ;
    USE SIGNAL ;
    PORT
      LAYER M4 ;
        RECT 345.408 14.496 345.600 14.520 ;
    END
  END ei_b[7]
  PIN ei_d[0]
    DIRECTION INPUT ;
    USE SIGNAL ;
    PORT
      LAYER M4 ;
        RECT 345.408 15.456 345.600 15.480 ;
    END
  END ei_d[0]
  PIN ei_d[1]
    DIRECTION INPUT ;
    USE SIGNAL ;
    PORT
      LAYER M4 ;
        RECT 345.408 16.464 345.600 16.488 ;
    END
  END ei_d[1]
  PIN ei_d[2]
    DIRECTION INPUT ;
    USE SIGNAL ;
    PORT
      LAYER M4 ;
        RECT 345.408 17.424 345.600 17.448 ;
    END
  END ei_d[2]
  PIN ei_d[3]
    DIRECTION INPUT ;
    USE SIGNAL ;
    PORT
      LAYER M4 ;
        RECT 345.408 18.432 345.600 18.456 ;
    END
  END ei_d[3]
  PIN ei_d[4]
    DIRECTION INPUT ;
    USE SIGNAL ;
    PORT
      LAYER M4 ;
        RECT 345.408 19.392 345.600 19.416 ;
    END
  END ei_d[4]
  PIN ei_d[5]
    DIRECTION INPUT ;
    USE SIGNAL ;
    PORT
      LAYER M4 ;
        RECT 345.408 20.400 345.600 20.424 ;
    END
  END ei_d[5]
  PIN ei_d[6]
    DIRECTION INPUT ;
    USE SIGNAL ;
    PORT
      LAYER M4 ;
        RECT 345.408 21.360 345.600 21.384 ;
    END
  END ei_d[6]
  PIN ei_d[7]
    DIRECTION INPUT ;
    USE SIGNAL ;
    PORT
      LAYER M4 ;
        RECT 345.408 22.368 345.600 22.392 ;
    END
  END ei_d[7]
  PIN ei_d[8]
    DIRECTION INPUT ;
    USE SIGNAL ;
    PORT
      LAYER M4 ;
        RECT 345.408 23.376 345.600 23.400 ;
    END
  END ei_d[8]
  PIN ei_d[9]
    DIRECTION INPUT ;
    USE SIGNAL ;
    PORT
      LAYER M4 ;
        RECT 345.408 24.336 345.600 24.360 ;
    END
  END ei_d[9]
  PIN ei_d[10]
    DIRECTION INPUT ;
    USE SIGNAL ;
    PORT
      LAYER M4 ;
        RECT 345.408 25.344 345.600 25.368 ;
    END
  END ei_d[10]
  PIN ei_d[11]
    DIRECTION INPUT ;
    USE SIGNAL ;
    PORT
      LAYER M4 ;
        RECT 345.408 26.304 345.600 26.328 ;
    END
  END ei_d[11]
  PIN ei_d[12]
    DIRECTION INPUT ;
    USE SIGNAL ;
    PORT
      LAYER M4 ;
        RECT 345.408 27.312 345.600 27.336 ;
    END
  END ei_d[12]
  PIN ei_d[13]
    DIRECTION INPUT ;
    USE SIGNAL ;
    PORT
      LAYER M4 ;
        RECT 345.408 28.272 345.600 28.296 ;
    END
  END ei_d[13]
  PIN ei_d[14]
    DIRECTION INPUT ;
    USE SIGNAL ;
    PORT
      LAYER M4 ;
        RECT 345.408 29.280 345.600 29.304 ;
    END
  END ei_d[14]
  PIN ei_d[15]
    DIRECTION INPUT ;
    USE SIGNAL ;
    PORT
      LAYER M4 ;
        RECT 345.408 30.240 345.600 30.264 ;
    END
  END ei_d[15]
  PIN ei_d[16]
    DIRECTION INPUT ;
    USE SIGNAL ;
    PORT
      LAYER M4 ;
        RECT 345.408 31.248 345.600 31.272 ;
    END
  END ei_d[16]
  PIN ei_d[17]
    DIRECTION INPUT ;
    USE SIGNAL ;
    PORT
      LAYER M4 ;
        RECT 345.408 32.208 345.600 32.232 ;
    END
  END ei_d[17]
  PIN ei_d[18]
    DIRECTION INPUT ;
    USE SIGNAL ;
    PORT
      LAYER M4 ;
        RECT 345.408 33.216 345.600 33.240 ;
    END
  END ei_d[18]
  PIN ei_d[19]
    DIRECTION INPUT ;
    USE SIGNAL ;
    PORT
      LAYER M4 ;
        RECT 345.408 34.224 345.600 34.248 ;
    END
  END ei_d[19]
  PIN ei_d[20]
    DIRECTION INPUT ;
    USE SIGNAL ;
    PORT
      LAYER M4 ;
        RECT 345.408 35.184 345.600 35.208 ;
    END
  END ei_d[20]
  PIN ei_d[21]
    DIRECTION INPUT ;
    USE SIGNAL ;
    PORT
      LAYER M4 ;
        RECT 345.408 36.192 345.600 36.216 ;
    END
  END ei_d[21]
  PIN ei_d[22]
    DIRECTION INPUT ;
    USE SIGNAL ;
    PORT
      LAYER M4 ;
        RECT 345.408 37.152 345.600 37.176 ;
    END
  END ei_d[22]
  PIN ei_d[23]
    DIRECTION INPUT ;
    USE SIGNAL ;
    PORT
      LAYER M4 ;
        RECT 345.408 38.160 345.600 38.184 ;
    END
  END ei_d[23]
  PIN ei_d[24]
    DIRECTION INPUT ;
    USE SIGNAL ;
    PORT
      LAYER M4 ;
        RECT 345.408 39.120 345.600 39.144 ;
    END
  END ei_d[24]
  PIN ei_d[25]
    DIRECTION INPUT ;
    USE SIGNAL ;
    PORT
      LAYER M4 ;
        RECT 345.408 40.128 345.600 40.152 ;
    END
  END ei_d[25]
  PIN ei_d[26]
    DIRECTION INPUT ;
    USE SIGNAL ;
    PORT
      LAYER M4 ;
        RECT 345.408 41.088 345.600 41.112 ;
    END
  END ei_d[26]
  PIN ei_d[27]
    DIRECTION INPUT ;
    USE SIGNAL ;
    PORT
      LAYER M4 ;
        RECT 345.408 42.096 345.600 42.120 ;
    END
  END ei_d[27]
  PIN ei_d[28]
    DIRECTION INPUT ;
    USE SIGNAL ;
    PORT
      LAYER M4 ;
        RECT 345.408 43.104 345.600 43.128 ;
    END
  END ei_d[28]
  PIN ei_d[29]
    DIRECTION INPUT ;
    USE SIGNAL ;
    PORT
      LAYER M4 ;
        RECT 345.408 44.064 345.600 44.088 ;
    END
  END ei_d[29]
  PIN ei_d[30]
    DIRECTION INPUT ;
    USE SIGNAL ;
    PORT
      LAYER M4 ;
        RECT 345.408 45.072 345.600 45.096 ;
    END
  END ei_d[30]
  PIN ei_d[31]
    DIRECTION INPUT ;
    USE SIGNAL ;
    PORT
      LAYER M4 ;
        RECT 345.408 46.032 345.600 46.056 ;
    END
  END ei_d[31]
  PIN ei_d[32]
    DIRECTION INPUT ;
    USE SIGNAL ;
    PORT
      LAYER M4 ;
        RECT 345.408 47.040 345.600 47.064 ;
    END
  END ei_d[32]
  PIN ei_d[33]
    DIRECTION INPUT ;
    USE SIGNAL ;
    PORT
      LAYER M4 ;
        RECT 345.408 48.000 345.600 48.024 ;
    END
  END ei_d[33]
  PIN ei_d[34]
    DIRECTION INPUT ;
    USE SIGNAL ;
    PORT
      LAYER M4 ;
        RECT 345.408 49.008 345.600 49.032 ;
    END
  END ei_d[34]
  PIN ei_d[35]
    DIRECTION INPUT ;
    USE SIGNAL ;
    PORT
      LAYER M4 ;
        RECT 345.408 49.968 345.600 49.992 ;
    END
  END ei_d[35]
  PIN ei_d[36]
    DIRECTION INPUT ;
    USE SIGNAL ;
    PORT
      LAYER M4 ;
        RECT 345.408 50.976 345.600 51.000 ;
    END
  END ei_d[36]
  PIN ei_d[37]
    DIRECTION INPUT ;
    USE SIGNAL ;
    PORT
      LAYER M4 ;
        RECT 345.408 51.936 345.600 51.960 ;
    END
  END ei_d[37]
  PIN ei_d[38]
    DIRECTION INPUT ;
    USE SIGNAL ;
    PORT
      LAYER M4 ;
        RECT 345.408 52.944 345.600 52.968 ;
    END
  END ei_d[38]
  PIN ei_d[39]
    DIRECTION INPUT ;
    USE SIGNAL ;
    PORT
      LAYER M4 ;
        RECT 345.408 53.952 345.600 53.976 ;
    END
  END ei_d[39]
  PIN ei_d[40]
    DIRECTION INPUT ;
    USE SIGNAL ;
    PORT
      LAYER M4 ;
        RECT 345.408 54.912 345.600 54.936 ;
    END
  END ei_d[40]
  PIN ei_d[41]
    DIRECTION INPUT ;
    USE SIGNAL ;
    PORT
      LAYER M4 ;
        RECT 345.408 55.920 345.600 55.944 ;
    END
  END ei_d[41]
  PIN ei_d[42]
    DIRECTION INPUT ;
    USE SIGNAL ;
    PORT
      LAYER M4 ;
        RECT 345.408 56.880 345.600 56.904 ;
    END
  END ei_d[42]
  PIN ei_d[43]
    DIRECTION INPUT ;
    USE SIGNAL ;
    PORT
      LAYER M4 ;
        RECT 345.408 57.888 345.600 57.912 ;
    END
  END ei_d[43]
  PIN ei_d[44]
    DIRECTION INPUT ;
    USE SIGNAL ;
    PORT
      LAYER M4 ;
        RECT 345.408 58.848 345.600 58.872 ;
    END
  END ei_d[44]
  PIN ei_d[45]
    DIRECTION INPUT ;
    USE SIGNAL ;
    PORT
      LAYER M4 ;
        RECT 345.408 59.856 345.600 59.880 ;
    END
  END ei_d[45]
  PIN ei_d[46]
    DIRECTION INPUT ;
    USE SIGNAL ;
    PORT
      LAYER M4 ;
        RECT 345.408 60.816 345.600 60.840 ;
    END
  END ei_d[46]
  PIN ei_d[47]
    DIRECTION INPUT ;
    USE SIGNAL ;
    PORT
      LAYER M4 ;
        RECT 345.408 61.824 345.600 61.848 ;
    END
  END ei_d[47]
  PIN ei_d[48]
    DIRECTION INPUT ;
    USE SIGNAL ;
    PORT
      LAYER M4 ;
        RECT 345.408 62.832 345.600 62.856 ;
    END
  END ei_d[48]
  PIN ei_d[49]
    DIRECTION INPUT ;
    USE SIGNAL ;
    PORT
      LAYER M4 ;
        RECT 345.408 63.792 345.600 63.816 ;
    END
  END ei_d[49]
  PIN ei_d[50]
    DIRECTION INPUT ;
    USE SIGNAL ;
    PORT
      LAYER M4 ;
        RECT 345.408 64.800 345.600 64.824 ;
    END
  END ei_d[50]
  PIN ei_d[51]
    DIRECTION INPUT ;
    USE SIGNAL ;
    PORT
      LAYER M4 ;
        RECT 345.408 65.760 345.600 65.784 ;
    END
  END ei_d[51]
  PIN ei_d[52]
    DIRECTION INPUT ;
    USE SIGNAL ;
    PORT
      LAYER M4 ;
        RECT 345.408 66.768 345.600 66.792 ;
    END
  END ei_d[52]
  PIN ei_d[53]
    DIRECTION INPUT ;
    USE SIGNAL ;
    PORT
      LAYER M4 ;
        RECT 345.408 67.728 345.600 67.752 ;
    END
  END ei_d[53]
  PIN ei_d[54]
    DIRECTION INPUT ;
    USE SIGNAL ;
    PORT
      LAYER M4 ;
        RECT 345.408 68.736 345.600 68.760 ;
    END
  END ei_d[54]
  PIN ei_d[55]
    DIRECTION INPUT ;
    USE SIGNAL ;
    PORT
      LAYER M4 ;
        RECT 345.408 69.696 345.600 69.720 ;
    END
  END ei_d[55]
  PIN ei_d[56]
    DIRECTION INPUT ;
    USE SIGNAL ;
    PORT
      LAYER M4 ;
        RECT 345.408 70.704 345.600 70.728 ;
    END
  END ei_d[56]
  PIN ei_d[57]
    DIRECTION INPUT ;
    USE SIGNAL ;
    PORT
      LAYER M4 ;
        RECT 345.408 71.664 345.600 71.688 ;
    END
  END ei_d[57]
  PIN ei_d[58]
    DIRECTION INPUT ;
    USE SIGNAL ;
    PORT
      LAYER M4 ;
        RECT 345.408 72.672 345.600 72.696 ;
    END
  END ei_d[58]
  PIN ei_d[59]
    DIRECTION INPUT ;
    USE SIGNAL ;
    PORT
      LAYER M4 ;
        RECT 345.408 73.680 345.600 73.704 ;
    END
  END ei_d[59]
  PIN ei_d[60]
    DIRECTION INPUT ;
    USE SIGNAL ;
    PORT
      LAYER M4 ;
        RECT 345.408 74.640 345.600 74.664 ;
    END
  END ei_d[60]
  PIN ei_d[61]
    DIRECTION INPUT ;
    USE SIGNAL ;
    PORT
      LAYER M4 ;
        RECT 345.408 75.648 345.600 75.672 ;
    END
  END ei_d[61]
  PIN ei_d[62]
    DIRECTION INPUT ;
    USE SIGNAL ;
    PORT
      LAYER M4 ;
        RECT 345.408 76.608 345.600 76.632 ;
    END
  END ei_d[62]
  PIN ei_d[63]
    DIRECTION INPUT ;
    USE SIGNAL ;
    PORT
      LAYER M4 ;
        RECT 345.408 77.616 345.600 77.640 ;
    END
  END ei_d[63]
  PIN ei_d[64]
    DIRECTION INPUT ;
    USE SIGNAL ;
    PORT
      LAYER M4 ;
        RECT 345.408 78.576 345.600 78.600 ;
    END
  END ei_d[64]
  PIN ei_d[65]
    DIRECTION INPUT ;
    USE SIGNAL ;
    PORT
      LAYER M4 ;
        RECT 345.408 79.584 345.600 79.608 ;
    END
  END ei_d[65]
  PIN ei_d[66]
    DIRECTION INPUT ;
    USE SIGNAL ;
    PORT
      LAYER M4 ;
        RECT 345.408 80.544 345.600 80.568 ;
    END
  END ei_d[66]
  PIN ei_d[67]
    DIRECTION INPUT ;
    USE SIGNAL ;
    PORT
      LAYER M4 ;
        RECT 345.408 81.552 345.600 81.576 ;
    END
  END ei_d[67]
  PIN ei_d[68]
    DIRECTION INPUT ;
    USE SIGNAL ;
    PORT
      LAYER M4 ;
        RECT 345.408 82.560 345.600 82.584 ;
    END
  END ei_d[68]
  PIN ei_d[69]
    DIRECTION INPUT ;
    USE SIGNAL ;
    PORT
      LAYER M4 ;
        RECT 345.408 83.520 345.600 83.544 ;
    END
  END ei_d[69]
  PIN ei_d[70]
    DIRECTION INPUT ;
    USE SIGNAL ;
    PORT
      LAYER M4 ;
        RECT 345.408 84.528 345.600 84.552 ;
    END
  END ei_d[70]
  PIN ei_d[71]
    DIRECTION INPUT ;
    USE SIGNAL ;
    PORT
      LAYER M4 ;
        RECT 345.408 85.488 345.600 85.512 ;
    END
  END ei_d[71]
  PIN ei_d[72]
    DIRECTION INPUT ;
    USE SIGNAL ;
    PORT
      LAYER M4 ;
        RECT 345.408 86.496 345.600 86.520 ;
    END
  END ei_d[72]
  PIN ei_d[73]
    DIRECTION INPUT ;
    USE SIGNAL ;
    PORT
      LAYER M4 ;
        RECT 345.408 87.456 345.600 87.480 ;
    END
  END ei_d[73]
  PIN ei_d[74]
    DIRECTION INPUT ;
    USE SIGNAL ;
    PORT
      LAYER M4 ;
        RECT 345.408 88.464 345.600 88.488 ;
    END
  END ei_d[74]
  PIN ei_d[75]
    DIRECTION INPUT ;
    USE SIGNAL ;
    PORT
      LAYER M4 ;
        RECT 345.408 89.424 345.600 89.448 ;
    END
  END ei_d[75]
  PIN ei_d[76]
    DIRECTION INPUT ;
    USE SIGNAL ;
    PORT
      LAYER M4 ;
        RECT 345.408 90.432 345.600 90.456 ;
    END
  END ei_d[76]
  PIN ei_d[77]
    DIRECTION INPUT ;
    USE SIGNAL ;
    PORT
      LAYER M4 ;
        RECT 345.408 91.392 345.600 91.416 ;
    END
  END ei_d[77]
  PIN ei_d[78]
    DIRECTION INPUT ;
    USE SIGNAL ;
    PORT
      LAYER M4 ;
        RECT 345.408 92.400 345.600 92.424 ;
    END
  END ei_d[78]
  PIN ei_d[79]
    DIRECTION INPUT ;
    USE SIGNAL ;
    PORT
      LAYER M4 ;
        RECT 345.408 93.408 345.600 93.432 ;
    END
  END ei_d[79]
  PIN ei_d[80]
    DIRECTION INPUT ;
    USE SIGNAL ;
    PORT
      LAYER M4 ;
        RECT 345.408 94.368 345.600 94.392 ;
    END
  END ei_d[80]
  PIN ei_d[81]
    DIRECTION INPUT ;
    USE SIGNAL ;
    PORT
      LAYER M4 ;
        RECT 345.408 95.376 345.600 95.400 ;
    END
  END ei_d[81]
  PIN ei_d[82]
    DIRECTION INPUT ;
    USE SIGNAL ;
    PORT
      LAYER M4 ;
        RECT 345.408 96.336 345.600 96.360 ;
    END
  END ei_d[82]
  PIN ei_d[83]
    DIRECTION INPUT ;
    USE SIGNAL ;
    PORT
      LAYER M4 ;
        RECT 345.408 97.344 345.600 97.368 ;
    END
  END ei_d[83]
  PIN ei_d[84]
    DIRECTION INPUT ;
    USE SIGNAL ;
    PORT
      LAYER M4 ;
        RECT 345.408 98.304 345.600 98.328 ;
    END
  END ei_d[84]
  PIN ei_d[85]
    DIRECTION INPUT ;
    USE SIGNAL ;
    PORT
      LAYER M4 ;
        RECT 345.408 99.312 345.600 99.336 ;
    END
  END ei_d[85]
  PIN ei_d[86]
    DIRECTION INPUT ;
    USE SIGNAL ;
    PORT
      LAYER M4 ;
        RECT 345.408 100.272 345.600 100.296 ;
    END
  END ei_d[86]
  PIN ei_d[87]
    DIRECTION INPUT ;
    USE SIGNAL ;
    PORT
      LAYER M4 ;
        RECT 345.408 101.280 345.600 101.304 ;
    END
  END ei_d[87]
  PIN ei_d[88]
    DIRECTION INPUT ;
    USE SIGNAL ;
    PORT
      LAYER M4 ;
        RECT 345.408 102.240 345.600 102.264 ;
    END
  END ei_d[88]
  PIN ei_d[89]
    DIRECTION INPUT ;
    USE SIGNAL ;
    PORT
      LAYER M4 ;
        RECT 345.408 103.248 345.600 103.272 ;
    END
  END ei_d[89]
  PIN ei_d[90]
    DIRECTION INPUT ;
    USE SIGNAL ;
    PORT
      LAYER M4 ;
        RECT 345.408 104.256 345.600 104.280 ;
    END
  END ei_d[90]
  PIN ei_d[91]
    DIRECTION INPUT ;
    USE SIGNAL ;
    PORT
      LAYER M4 ;
        RECT 345.408 105.216 345.600 105.240 ;
    END
  END ei_d[91]
  PIN ei_d[92]
    DIRECTION INPUT ;
    USE SIGNAL ;
    PORT
      LAYER M4 ;
        RECT 345.408 106.224 345.600 106.248 ;
    END
  END ei_d[92]
  PIN ei_d[93]
    DIRECTION INPUT ;
    USE SIGNAL ;
    PORT
      LAYER M4 ;
        RECT 345.408 107.184 345.600 107.208 ;
    END
  END ei_d[93]
  PIN ei_d[94]
    DIRECTION INPUT ;
    USE SIGNAL ;
    PORT
      LAYER M4 ;
        RECT 345.408 108.192 345.600 108.216 ;
    END
  END ei_d[94]
  PIN ei_d[95]
    DIRECTION INPUT ;
    USE SIGNAL ;
    PORT
      LAYER M4 ;
        RECT 345.408 109.152 345.600 109.176 ;
    END
  END ei_d[95]
  PIN ei_d[96]
    DIRECTION INPUT ;
    USE SIGNAL ;
    PORT
      LAYER M4 ;
        RECT 345.408 110.160 345.600 110.184 ;
    END
  END ei_d[96]
  PIN ei_d[97]
    DIRECTION INPUT ;
    USE SIGNAL ;
    PORT
      LAYER M4 ;
        RECT 345.408 111.120 345.600 111.144 ;
    END
  END ei_d[97]
  PIN ei_d[98]
    DIRECTION INPUT ;
    USE SIGNAL ;
    PORT
      LAYER M4 ;
        RECT 345.408 112.128 345.600 112.152 ;
    END
  END ei_d[98]
  PIN ei_d[99]
    DIRECTION INPUT ;
    USE SIGNAL ;
    PORT
      LAYER M4 ;
        RECT 345.408 113.136 345.600 113.160 ;
    END
  END ei_d[99]
  PIN ei_d[100]
    DIRECTION INPUT ;
    USE SIGNAL ;
    PORT
      LAYER M4 ;
        RECT 345.408 114.096 345.600 114.120 ;
    END
  END ei_d[100]
  PIN ei_d[101]
    DIRECTION INPUT ;
    USE SIGNAL ;
    PORT
      LAYER M4 ;
        RECT 345.408 115.104 345.600 115.128 ;
    END
  END ei_d[101]
  PIN ei_d[102]
    DIRECTION INPUT ;
    USE SIGNAL ;
    PORT
      LAYER M4 ;
        RECT 345.408 116.064 345.600 116.088 ;
    END
  END ei_d[102]
  PIN ei_d[103]
    DIRECTION INPUT ;
    USE SIGNAL ;
    PORT
      LAYER M4 ;
        RECT 345.408 117.072 345.600 117.096 ;
    END
  END ei_d[103]
  PIN ei_d[104]
    DIRECTION INPUT ;
    USE SIGNAL ;
    PORT
      LAYER M4 ;
        RECT 345.408 118.032 345.600 118.056 ;
    END
  END ei_d[104]
  PIN ei_d[105]
    DIRECTION INPUT ;
    USE SIGNAL ;
    PORT
      LAYER M4 ;
        RECT 345.408 119.040 345.600 119.064 ;
    END
  END ei_d[105]
  PIN ei_d[106]
    DIRECTION INPUT ;
    USE SIGNAL ;
    PORT
      LAYER M4 ;
        RECT 345.408 120.000 345.600 120.024 ;
    END
  END ei_d[106]
  PIN ei_d[107]
    DIRECTION INPUT ;
    USE SIGNAL ;
    PORT
      LAYER M4 ;
        RECT 345.408 121.008 345.600 121.032 ;
    END
  END ei_d[107]
  PIN ei_d[108]
    DIRECTION INPUT ;
    USE SIGNAL ;
    PORT
      LAYER M4 ;
        RECT 345.408 121.968 345.600 121.992 ;
    END
  END ei_d[108]
  PIN ei_d[109]
    DIRECTION INPUT ;
    USE SIGNAL ;
    PORT
      LAYER M4 ;
        RECT 345.408 122.976 345.600 123.000 ;
    END
  END ei_d[109]
  PIN ei_d[110]
    DIRECTION INPUT ;
    USE SIGNAL ;
    PORT
      LAYER M4 ;
        RECT 345.408 123.984 345.600 124.008 ;
    END
  END ei_d[110]
  PIN ei_d[111]
    DIRECTION INPUT ;
    USE SIGNAL ;
    PORT
      LAYER M4 ;
        RECT 345.408 124.944 345.600 124.968 ;
    END
  END ei_d[111]
  PIN ei_d[112]
    DIRECTION INPUT ;
    USE SIGNAL ;
    PORT
      LAYER M4 ;
        RECT 345.408 125.952 345.600 125.976 ;
    END
  END ei_d[112]
  PIN ei_d[113]
    DIRECTION INPUT ;
    USE SIGNAL ;
    PORT
      LAYER M4 ;
        RECT 345.408 126.912 345.600 126.936 ;
    END
  END ei_d[113]
  PIN ei_d[114]
    DIRECTION INPUT ;
    USE SIGNAL ;
    PORT
      LAYER M4 ;
        RECT 345.408 127.920 345.600 127.944 ;
    END
  END ei_d[114]
  PIN ei_d[115]
    DIRECTION INPUT ;
    USE SIGNAL ;
    PORT
      LAYER M4 ;
        RECT 345.408 128.880 345.600 128.904 ;
    END
  END ei_d[115]
  PIN ei_d[116]
    DIRECTION INPUT ;
    USE SIGNAL ;
    PORT
      LAYER M4 ;
        RECT 345.408 129.888 345.600 129.912 ;
    END
  END ei_d[116]
  PIN ei_d[117]
    DIRECTION INPUT ;
    USE SIGNAL ;
    PORT
      LAYER M4 ;
        RECT 345.408 130.848 345.600 130.872 ;
    END
  END ei_d[117]
  PIN ei_d[118]
    DIRECTION INPUT ;
    USE SIGNAL ;
    PORT
      LAYER M4 ;
        RECT 345.408 131.856 345.600 131.880 ;
    END
  END ei_d[118]
  PIN ei_d[119]
    DIRECTION INPUT ;
    USE SIGNAL ;
    PORT
      LAYER M4 ;
        RECT 345.408 132.864 345.600 132.888 ;
    END
  END ei_d[119]
  PIN ei_d[120]
    DIRECTION INPUT ;
    USE SIGNAL ;
    PORT
      LAYER M4 ;
        RECT 345.408 133.824 345.600 133.848 ;
    END
  END ei_d[120]
  PIN ei_d[121]
    DIRECTION INPUT ;
    USE SIGNAL ;
    PORT
      LAYER M4 ;
        RECT 345.408 134.832 345.600 134.856 ;
    END
  END ei_d[121]
  PIN ei_d[122]
    DIRECTION INPUT ;
    USE SIGNAL ;
    PORT
      LAYER M4 ;
        RECT 345.408 135.792 345.600 135.816 ;
    END
  END ei_d[122]
  PIN ei_d[123]
    DIRECTION INPUT ;
    USE SIGNAL ;
    PORT
      LAYER M4 ;
        RECT 345.408 136.800 345.600 136.824 ;
    END
  END ei_d[123]
  PIN ei_d[124]
    DIRECTION INPUT ;
    USE SIGNAL ;
    PORT
      LAYER M4 ;
        RECT 345.408 137.760 345.600 137.784 ;
    END
  END ei_d[124]
  PIN ei_d[125]
    DIRECTION INPUT ;
    USE SIGNAL ;
    PORT
      LAYER M4 ;
        RECT 345.408 138.768 345.600 138.792 ;
    END
  END ei_d[125]
  PIN ei_d[126]
    DIRECTION INPUT ;
    USE SIGNAL ;
    PORT
      LAYER M4 ;
        RECT 345.408 139.728 345.600 139.752 ;
    END
  END ei_d[126]
  PIN ei_d[127]
    DIRECTION INPUT ;
    USE SIGNAL ;
    PORT
      LAYER M4 ;
        RECT 345.408 140.736 345.600 140.760 ;
    END
  END ei_d[127]
  PIN ei_d[128]
    DIRECTION INPUT ;
    USE SIGNAL ;
    PORT
      LAYER M4 ;
        RECT 345.408 141.696 345.600 141.720 ;
    END
  END ei_d[128]
  PIN ei_d[129]
    DIRECTION INPUT ;
    USE SIGNAL ;
    PORT
      LAYER M4 ;
        RECT 345.408 142.704 345.600 142.728 ;
    END
  END ei_d[129]
  PIN ei_d[130]
    DIRECTION INPUT ;
    USE SIGNAL ;
    PORT
      LAYER M4 ;
        RECT 345.408 143.712 345.600 143.736 ;
    END
  END ei_d[130]
  PIN ei_d[131]
    DIRECTION INPUT ;
    USE SIGNAL ;
    PORT
      LAYER M4 ;
        RECT 345.408 144.672 345.600 144.696 ;
    END
  END ei_d[131]
  PIN ei_d[132]
    DIRECTION INPUT ;
    USE SIGNAL ;
    PORT
      LAYER M4 ;
        RECT 345.408 145.680 345.600 145.704 ;
    END
  END ei_d[132]
  PIN ei_d[133]
    DIRECTION INPUT ;
    USE SIGNAL ;
    PORT
      LAYER M4 ;
        RECT 345.408 146.640 345.600 146.664 ;
    END
  END ei_d[133]
  PIN ei_d[134]
    DIRECTION INPUT ;
    USE SIGNAL ;
    PORT
      LAYER M4 ;
        RECT 345.408 147.648 345.600 147.672 ;
    END
  END ei_d[134]
  PIN ei_d[135]
    DIRECTION INPUT ;
    USE SIGNAL ;
    PORT
      LAYER M4 ;
        RECT 345.408 148.608 345.600 148.632 ;
    END
  END ei_d[135]
  PIN ei_d[136]
    DIRECTION INPUT ;
    USE SIGNAL ;
    PORT
      LAYER M4 ;
        RECT 345.408 149.616 345.600 149.640 ;
    END
  END ei_d[136]
  PIN ei_d[137]
    DIRECTION INPUT ;
    USE SIGNAL ;
    PORT
      LAYER M4 ;
        RECT 345.408 150.576 345.600 150.600 ;
    END
  END ei_d[137]
  PIN ei_d[138]
    DIRECTION INPUT ;
    USE SIGNAL ;
    PORT
      LAYER M4 ;
        RECT 345.408 151.584 345.600 151.608 ;
    END
  END ei_d[138]
  PIN ei_d[139]
    DIRECTION INPUT ;
    USE SIGNAL ;
    PORT
      LAYER M4 ;
        RECT 345.408 152.544 345.600 152.568 ;
    END
  END ei_d[139]
  PIN ei_d[140]
    DIRECTION INPUT ;
    USE SIGNAL ;
    PORT
      LAYER M4 ;
        RECT 345.408 153.552 345.600 153.576 ;
    END
  END ei_d[140]
  PIN ei_d[141]
    DIRECTION INPUT ;
    USE SIGNAL ;
    PORT
      LAYER M4 ;
        RECT 345.408 154.560 345.600 154.584 ;
    END
  END ei_d[141]
  PIN ei_d[142]
    DIRECTION INPUT ;
    USE SIGNAL ;
    PORT
      LAYER M4 ;
        RECT 345.408 155.520 345.600 155.544 ;
    END
  END ei_d[142]
  PIN ei_d[143]
    DIRECTION INPUT ;
    USE SIGNAL ;
    PORT
      LAYER M4 ;
        RECT 345.408 156.528 345.600 156.552 ;
    END
  END ei_d[143]
  PIN ei_d[144]
    DIRECTION INPUT ;
    USE SIGNAL ;
    PORT
      LAYER M4 ;
        RECT 345.408 157.488 345.600 157.512 ;
    END
  END ei_d[144]
  PIN ei_d[145]
    DIRECTION INPUT ;
    USE SIGNAL ;
    PORT
      LAYER M4 ;
        RECT 345.408 158.496 345.600 158.520 ;
    END
  END ei_d[145]
  PIN ei_d[146]
    DIRECTION INPUT ;
    USE SIGNAL ;
    PORT
      LAYER M4 ;
        RECT 345.408 159.456 345.600 159.480 ;
    END
  END ei_d[146]
  PIN ei_d[147]
    DIRECTION INPUT ;
    USE SIGNAL ;
    PORT
      LAYER M4 ;
        RECT 345.408 160.464 345.600 160.488 ;
    END
  END ei_d[147]
  PIN ei_d[148]
    DIRECTION INPUT ;
    USE SIGNAL ;
    PORT
      LAYER M4 ;
        RECT 345.408 161.424 345.600 161.448 ;
    END
  END ei_d[148]
  PIN ei_d[149]
    DIRECTION INPUT ;
    USE SIGNAL ;
    PORT
      LAYER M4 ;
        RECT 345.408 162.432 345.600 162.456 ;
    END
  END ei_d[149]
  PIN ei_d[150]
    DIRECTION INPUT ;
    USE SIGNAL ;
    PORT
      LAYER M4 ;
        RECT 345.408 163.440 345.600 163.464 ;
    END
  END ei_d[150]
  PIN ei_d[151]
    DIRECTION INPUT ;
    USE SIGNAL ;
    PORT
      LAYER M4 ;
        RECT 345.408 164.400 345.600 164.424 ;
    END
  END ei_d[151]
  PIN ei_d[152]
    DIRECTION INPUT ;
    USE SIGNAL ;
    PORT
      LAYER M4 ;
        RECT 345.408 165.408 345.600 165.432 ;
    END
  END ei_d[152]
  PIN ei_d[153]
    DIRECTION INPUT ;
    USE SIGNAL ;
    PORT
      LAYER M4 ;
        RECT 345.408 166.368 345.600 166.392 ;
    END
  END ei_d[153]
  PIN ei_d[154]
    DIRECTION INPUT ;
    USE SIGNAL ;
    PORT
      LAYER M4 ;
        RECT 345.408 167.376 345.600 167.400 ;
    END
  END ei_d[154]
  PIN ei_d[155]
    DIRECTION INPUT ;
    USE SIGNAL ;
    PORT
      LAYER M4 ;
        RECT 345.408 168.336 345.600 168.360 ;
    END
  END ei_d[155]
  PIN ei_d[156]
    DIRECTION INPUT ;
    USE SIGNAL ;
    PORT
      LAYER M4 ;
        RECT 345.408 169.344 345.600 169.368 ;
    END
  END ei_d[156]
  PIN ei_d[157]
    DIRECTION INPUT ;
    USE SIGNAL ;
    PORT
      LAYER M4 ;
        RECT 345.408 170.304 345.600 170.328 ;
    END
  END ei_d[157]
  PIN ei_d[158]
    DIRECTION INPUT ;
    USE SIGNAL ;
    PORT
      LAYER M4 ;
        RECT 345.408 171.312 345.600 171.336 ;
    END
  END ei_d[158]
  PIN ei_d[159]
    DIRECTION INPUT ;
    USE SIGNAL ;
    PORT
      LAYER M4 ;
        RECT 345.408 172.272 345.600 172.296 ;
    END
  END ei_d[159]
  PIN eo_v
    DIRECTION OUTPUT ;
    USE SIGNAL ;
    PORT
      LAYER M4 ;
        RECT 345.408 173.280 345.600 173.304 ;
    END
  END eo_v
  PIN eo_h[0]
    DIRECTION OUTPUT ;
    USE SIGNAL ;
    PORT
      LAYER M4 ;
        RECT 345.408 174.288 345.600 174.312 ;
    END
  END eo_h[0]
  PIN eo_h[1]
    DIRECTION OUTPUT ;
    USE SIGNAL ;
    PORT
      LAYER M4 ;
        RECT 345.408 175.248 345.600 175.272 ;
    END
  END eo_h[1]
  PIN eo_h[2]
    DIRECTION OUTPUT ;
    USE SIGNAL ;
    PORT
      LAYER M4 ;
        RECT 345.408 176.256 345.600 176.280 ;
    END
  END eo_h[2]
  PIN eo_h[3]
    DIRECTION OUTPUT ;
    USE SIGNAL ;
    PORT
      LAYER M4 ;
        RECT 345.408 177.216 345.600 177.240 ;
    END
  END eo_h[3]
  PIN eo_b[0]
    DIRECTION OUTPUT ;
    USE SIGNAL ;
    PORT
      LAYER M4 ;
        RECT 345.408 178.224 345.600 178.248 ;
    END
  END eo_b[0]
  PIN eo_b[1]
    DIRECTION OUTPUT ;
    USE SIGNAL ;
    PORT
      LAYER M4 ;
        RECT 345.408 179.184 345.600 179.208 ;
    END
  END eo_b[1]
  PIN eo_b[2]
    DIRECTION OUTPUT ;
    USE SIGNAL ;
    PORT
      LAYER M4 ;
        RECT 345.408 180.192 345.600 180.216 ;
    END
  END eo_b[2]
  PIN eo_b[3]
    DIRECTION OUTPUT ;
    USE SIGNAL ;
    PORT
      LAYER M4 ;
        RECT 345.408 181.152 345.600 181.176 ;
    END
  END eo_b[3]
  PIN eo_b[4]
    DIRECTION OUTPUT ;
    USE SIGNAL ;
    PORT
      LAYER M4 ;
        RECT 345.408 182.160 345.600 182.184 ;
    END
  END eo_b[4]
  PIN eo_b[5]
    DIRECTION OUTPUT ;
    USE SIGNAL ;
    PORT
      LAYER M4 ;
        RECT 345.408 183.168 345.600 183.192 ;
    END
  END eo_b[5]
  PIN eo_b[6]
    DIRECTION OUTPUT ;
    USE SIGNAL ;
    PORT
      LAYER M4 ;
        RECT 345.408 184.128 345.600 184.152 ;
    END
  END eo_b[6]
  PIN eo_b[7]
    DIRECTION OUTPUT ;
    USE SIGNAL ;
    PORT
      LAYER M4 ;
        RECT 345.408 185.136 345.600 185.160 ;
    END
  END eo_b[7]
  PIN eo_d[0]
    DIRECTION OUTPUT ;
    USE SIGNAL ;
    PORT
      LAYER M4 ;
        RECT 345.408 186.096 345.600 186.120 ;
    END
  END eo_d[0]
  PIN eo_d[1]
    DIRECTION OUTPUT ;
    USE SIGNAL ;
    PORT
      LAYER M4 ;
        RECT 345.408 187.104 345.600 187.128 ;
    END
  END eo_d[1]
  PIN eo_d[2]
    DIRECTION OUTPUT ;
    USE SIGNAL ;
    PORT
      LAYER M4 ;
        RECT 345.408 188.064 345.600 188.088 ;
    END
  END eo_d[2]
  PIN eo_d[3]
    DIRECTION OUTPUT ;
    USE SIGNAL ;
    PORT
      LAYER M4 ;
        RECT 345.408 189.072 345.600 189.096 ;
    END
  END eo_d[3]
  PIN eo_d[4]
    DIRECTION OUTPUT ;
    USE SIGNAL ;
    PORT
      LAYER M4 ;
        RECT 345.408 190.032 345.600 190.056 ;
    END
  END eo_d[4]
  PIN eo_d[5]
    DIRECTION OUTPUT ;
    USE SIGNAL ;
    PORT
      LAYER M4 ;
        RECT 345.408 191.040 345.600 191.064 ;
    END
  END eo_d[5]
  PIN eo_d[6]
    DIRECTION OUTPUT ;
    USE SIGNAL ;
    PORT
      LAYER M4 ;
        RECT 345.408 192.000 345.600 192.024 ;
    END
  END eo_d[6]
  PIN eo_d[7]
    DIRECTION OUTPUT ;
    USE SIGNAL ;
    PORT
      LAYER M4 ;
        RECT 345.408 193.008 345.600 193.032 ;
    END
  END eo_d[7]
  PIN eo_d[8]
    DIRECTION OUTPUT ;
    USE SIGNAL ;
    PORT
      LAYER M4 ;
        RECT 345.408 194.016 345.600 194.040 ;
    END
  END eo_d[8]
  PIN eo_d[9]
    DIRECTION OUTPUT ;
    USE SIGNAL ;
    PORT
      LAYER M4 ;
        RECT 345.408 194.976 345.600 195.000 ;
    END
  END eo_d[9]
  PIN eo_d[10]
    DIRECTION OUTPUT ;
    USE SIGNAL ;
    PORT
      LAYER M4 ;
        RECT 345.408 195.984 345.600 196.008 ;
    END
  END eo_d[10]
  PIN eo_d[11]
    DIRECTION OUTPUT ;
    USE SIGNAL ;
    PORT
      LAYER M4 ;
        RECT 345.408 196.944 345.600 196.968 ;
    END
  END eo_d[11]
  PIN eo_d[12]
    DIRECTION OUTPUT ;
    USE SIGNAL ;
    PORT
      LAYER M4 ;
        RECT 345.408 197.952 345.600 197.976 ;
    END
  END eo_d[12]
  PIN eo_d[13]
    DIRECTION OUTPUT ;
    USE SIGNAL ;
    PORT
      LAYER M4 ;
        RECT 345.408 198.912 345.600 198.936 ;
    END
  END eo_d[13]
  PIN eo_d[14]
    DIRECTION OUTPUT ;
    USE SIGNAL ;
    PORT
      LAYER M4 ;
        RECT 345.408 199.920 345.600 199.944 ;
    END
  END eo_d[14]
  PIN eo_d[15]
    DIRECTION OUTPUT ;
    USE SIGNAL ;
    PORT
      LAYER M4 ;
        RECT 345.408 200.880 345.600 200.904 ;
    END
  END eo_d[15]
  PIN eo_d[16]
    DIRECTION OUTPUT ;
    USE SIGNAL ;
    PORT
      LAYER M4 ;
        RECT 345.408 201.888 345.600 201.912 ;
    END
  END eo_d[16]
  PIN eo_d[17]
    DIRECTION OUTPUT ;
    USE SIGNAL ;
    PORT
      LAYER M4 ;
        RECT 345.408 202.848 345.600 202.872 ;
    END
  END eo_d[17]
  PIN eo_d[18]
    DIRECTION OUTPUT ;
    USE SIGNAL ;
    PORT
      LAYER M4 ;
        RECT 345.408 203.856 345.600 203.880 ;
    END
  END eo_d[18]
  PIN eo_d[19]
    DIRECTION OUTPUT ;
    USE SIGNAL ;
    PORT
      LAYER M4 ;
        RECT 345.408 204.864 345.600 204.888 ;
    END
  END eo_d[19]
  PIN eo_d[20]
    DIRECTION OUTPUT ;
    USE SIGNAL ;
    PORT
      LAYER M4 ;
        RECT 345.408 205.824 345.600 205.848 ;
    END
  END eo_d[20]
  PIN eo_d[21]
    DIRECTION OUTPUT ;
    USE SIGNAL ;
    PORT
      LAYER M4 ;
        RECT 345.408 206.832 345.600 206.856 ;
    END
  END eo_d[21]
  PIN eo_d[22]
    DIRECTION OUTPUT ;
    USE SIGNAL ;
    PORT
      LAYER M4 ;
        RECT 345.408 207.792 345.600 207.816 ;
    END
  END eo_d[22]
  PIN eo_d[23]
    DIRECTION OUTPUT ;
    USE SIGNAL ;
    PORT
      LAYER M4 ;
        RECT 345.408 208.800 345.600 208.824 ;
    END
  END eo_d[23]
  PIN eo_d[24]
    DIRECTION OUTPUT ;
    USE SIGNAL ;
    PORT
      LAYER M4 ;
        RECT 345.408 209.760 345.600 209.784 ;
    END
  END eo_d[24]
  PIN eo_d[25]
    DIRECTION OUTPUT ;
    USE SIGNAL ;
    PORT
      LAYER M4 ;
        RECT 345.408 210.768 345.600 210.792 ;
    END
  END eo_d[25]
  PIN eo_d[26]
    DIRECTION OUTPUT ;
    USE SIGNAL ;
    PORT
      LAYER M4 ;
        RECT 345.408 211.728 345.600 211.752 ;
    END
  END eo_d[26]
  PIN eo_d[27]
    DIRECTION OUTPUT ;
    USE SIGNAL ;
    PORT
      LAYER M4 ;
        RECT 345.408 212.736 345.600 212.760 ;
    END
  END eo_d[27]
  PIN eo_d[28]
    DIRECTION OUTPUT ;
    USE SIGNAL ;
    PORT
      LAYER M4 ;
        RECT 345.408 213.744 345.600 213.768 ;
    END
  END eo_d[28]
  PIN eo_d[29]
    DIRECTION OUTPUT ;
    USE SIGNAL ;
    PORT
      LAYER M4 ;
        RECT 345.408 214.704 345.600 214.728 ;
    END
  END eo_d[29]
  PIN eo_d[30]
    DIRECTION OUTPUT ;
    USE SIGNAL ;
    PORT
      LAYER M4 ;
        RECT 345.408 215.712 345.600 215.736 ;
    END
  END eo_d[30]
  PIN eo_d[31]
    DIRECTION OUTPUT ;
    USE SIGNAL ;
    PORT
      LAYER M4 ;
        RECT 345.408 216.672 345.600 216.696 ;
    END
  END eo_d[31]
  PIN eo_d[32]
    DIRECTION OUTPUT ;
    USE SIGNAL ;
    PORT
      LAYER M4 ;
        RECT 345.408 217.680 345.600 217.704 ;
    END
  END eo_d[32]
  PIN eo_d[33]
    DIRECTION OUTPUT ;
    USE SIGNAL ;
    PORT
      LAYER M4 ;
        RECT 345.408 218.640 345.600 218.664 ;
    END
  END eo_d[33]
  PIN eo_d[34]
    DIRECTION OUTPUT ;
    USE SIGNAL ;
    PORT
      LAYER M4 ;
        RECT 345.408 219.648 345.600 219.672 ;
    END
  END eo_d[34]
  PIN eo_d[35]
    DIRECTION OUTPUT ;
    USE SIGNAL ;
    PORT
      LAYER M4 ;
        RECT 345.408 220.608 345.600 220.632 ;
    END
  END eo_d[35]
  PIN eo_d[36]
    DIRECTION OUTPUT ;
    USE SIGNAL ;
    PORT
      LAYER M4 ;
        RECT 345.408 221.616 345.600 221.640 ;
    END
  END eo_d[36]
  PIN eo_d[37]
    DIRECTION OUTPUT ;
    USE SIGNAL ;
    PORT
      LAYER M4 ;
        RECT 345.408 222.576 345.600 222.600 ;
    END
  END eo_d[37]
  PIN eo_d[38]
    DIRECTION OUTPUT ;
    USE SIGNAL ;
    PORT
      LAYER M4 ;
        RECT 345.408 223.584 345.600 223.608 ;
    END
  END eo_d[38]
  PIN eo_d[39]
    DIRECTION OUTPUT ;
    USE SIGNAL ;
    PORT
      LAYER M4 ;
        RECT 345.408 224.592 345.600 224.616 ;
    END
  END eo_d[39]
  PIN eo_d[40]
    DIRECTION OUTPUT ;
    USE SIGNAL ;
    PORT
      LAYER M4 ;
        RECT 345.408 225.552 345.600 225.576 ;
    END
  END eo_d[40]
  PIN eo_d[41]
    DIRECTION OUTPUT ;
    USE SIGNAL ;
    PORT
      LAYER M4 ;
        RECT 345.408 226.560 345.600 226.584 ;
    END
  END eo_d[41]
  PIN eo_d[42]
    DIRECTION OUTPUT ;
    USE SIGNAL ;
    PORT
      LAYER M4 ;
        RECT 345.408 227.520 345.600 227.544 ;
    END
  END eo_d[42]
  PIN eo_d[43]
    DIRECTION OUTPUT ;
    USE SIGNAL ;
    PORT
      LAYER M4 ;
        RECT 345.408 228.528 345.600 228.552 ;
    END
  END eo_d[43]
  PIN eo_d[44]
    DIRECTION OUTPUT ;
    USE SIGNAL ;
    PORT
      LAYER M4 ;
        RECT 345.408 229.488 345.600 229.512 ;
    END
  END eo_d[44]
  PIN eo_d[45]
    DIRECTION OUTPUT ;
    USE SIGNAL ;
    PORT
      LAYER M4 ;
        RECT 345.408 230.496 345.600 230.520 ;
    END
  END eo_d[45]
  PIN eo_d[46]
    DIRECTION OUTPUT ;
    USE SIGNAL ;
    PORT
      LAYER M4 ;
        RECT 345.408 231.456 345.600 231.480 ;
    END
  END eo_d[46]
  PIN eo_d[47]
    DIRECTION OUTPUT ;
    USE SIGNAL ;
    PORT
      LAYER M4 ;
        RECT 345.408 232.464 345.600 232.488 ;
    END
  END eo_d[47]
  PIN eo_d[48]
    DIRECTION OUTPUT ;
    USE SIGNAL ;
    PORT
      LAYER M4 ;
        RECT 345.408 233.472 345.600 233.496 ;
    END
  END eo_d[48]
  PIN eo_d[49]
    DIRECTION OUTPUT ;
    USE SIGNAL ;
    PORT
      LAYER M4 ;
        RECT 345.408 234.432 345.600 234.456 ;
    END
  END eo_d[49]
  PIN eo_d[50]
    DIRECTION OUTPUT ;
    USE SIGNAL ;
    PORT
      LAYER M4 ;
        RECT 345.408 235.440 345.600 235.464 ;
    END
  END eo_d[50]
  PIN eo_d[51]
    DIRECTION OUTPUT ;
    USE SIGNAL ;
    PORT
      LAYER M4 ;
        RECT 345.408 236.400 345.600 236.424 ;
    END
  END eo_d[51]
  PIN eo_d[52]
    DIRECTION OUTPUT ;
    USE SIGNAL ;
    PORT
      LAYER M4 ;
        RECT 345.408 237.408 345.600 237.432 ;
    END
  END eo_d[52]
  PIN eo_d[53]
    DIRECTION OUTPUT ;
    USE SIGNAL ;
    PORT
      LAYER M4 ;
        RECT 345.408 238.368 345.600 238.392 ;
    END
  END eo_d[53]
  PIN eo_d[54]
    DIRECTION OUTPUT ;
    USE SIGNAL ;
    PORT
      LAYER M4 ;
        RECT 345.408 239.376 345.600 239.400 ;
    END
  END eo_d[54]
  PIN eo_d[55]
    DIRECTION OUTPUT ;
    USE SIGNAL ;
    PORT
      LAYER M4 ;
        RECT 345.408 240.336 345.600 240.360 ;
    END
  END eo_d[55]
  PIN eo_d[56]
    DIRECTION OUTPUT ;
    USE SIGNAL ;
    PORT
      LAYER M4 ;
        RECT 345.408 241.344 345.600 241.368 ;
    END
  END eo_d[56]
  PIN eo_d[57]
    DIRECTION OUTPUT ;
    USE SIGNAL ;
    PORT
      LAYER M4 ;
        RECT 345.408 242.304 345.600 242.328 ;
    END
  END eo_d[57]
  PIN eo_d[58]
    DIRECTION OUTPUT ;
    USE SIGNAL ;
    PORT
      LAYER M4 ;
        RECT 345.408 243.312 345.600 243.336 ;
    END
  END eo_d[58]
  PIN eo_d[59]
    DIRECTION OUTPUT ;
    USE SIGNAL ;
    PORT
      LAYER M4 ;
        RECT 345.408 244.320 345.600 244.344 ;
    END
  END eo_d[59]
  PIN eo_d[60]
    DIRECTION OUTPUT ;
    USE SIGNAL ;
    PORT
      LAYER M4 ;
        RECT 345.408 245.280 345.600 245.304 ;
    END
  END eo_d[60]
  PIN eo_d[61]
    DIRECTION OUTPUT ;
    USE SIGNAL ;
    PORT
      LAYER M4 ;
        RECT 345.408 246.288 345.600 246.312 ;
    END
  END eo_d[61]
  PIN eo_d[62]
    DIRECTION OUTPUT ;
    USE SIGNAL ;
    PORT
      LAYER M4 ;
        RECT 345.408 247.248 345.600 247.272 ;
    END
  END eo_d[62]
  PIN eo_d[63]
    DIRECTION OUTPUT ;
    USE SIGNAL ;
    PORT
      LAYER M4 ;
        RECT 345.408 248.256 345.600 248.280 ;
    END
  END eo_d[63]
  PIN eo_d[64]
    DIRECTION OUTPUT ;
    USE SIGNAL ;
    PORT
      LAYER M4 ;
        RECT 345.408 249.216 345.600 249.240 ;
    END
  END eo_d[64]
  PIN eo_d[65]
    DIRECTION OUTPUT ;
    USE SIGNAL ;
    PORT
      LAYER M4 ;
        RECT 345.408 250.224 345.600 250.248 ;
    END
  END eo_d[65]
  PIN eo_d[66]
    DIRECTION OUTPUT ;
    USE SIGNAL ;
    PORT
      LAYER M4 ;
        RECT 345.408 251.184 345.600 251.208 ;
    END
  END eo_d[66]
  PIN eo_d[67]
    DIRECTION OUTPUT ;
    USE SIGNAL ;
    PORT
      LAYER M4 ;
        RECT 345.408 252.192 345.600 252.216 ;
    END
  END eo_d[67]
  PIN eo_d[68]
    DIRECTION OUTPUT ;
    USE SIGNAL ;
    PORT
      LAYER M4 ;
        RECT 345.408 253.200 345.600 253.224 ;
    END
  END eo_d[68]
  PIN eo_d[69]
    DIRECTION OUTPUT ;
    USE SIGNAL ;
    PORT
      LAYER M4 ;
        RECT 345.408 254.160 345.600 254.184 ;
    END
  END eo_d[69]
  PIN eo_d[70]
    DIRECTION OUTPUT ;
    USE SIGNAL ;
    PORT
      LAYER M4 ;
        RECT 345.408 255.168 345.600 255.192 ;
    END
  END eo_d[70]
  PIN eo_d[71]
    DIRECTION OUTPUT ;
    USE SIGNAL ;
    PORT
      LAYER M4 ;
        RECT 345.408 256.128 345.600 256.152 ;
    END
  END eo_d[71]
  PIN eo_d[72]
    DIRECTION OUTPUT ;
    USE SIGNAL ;
    PORT
      LAYER M4 ;
        RECT 345.408 257.136 345.600 257.160 ;
    END
  END eo_d[72]
  PIN eo_d[73]
    DIRECTION OUTPUT ;
    USE SIGNAL ;
    PORT
      LAYER M4 ;
        RECT 345.408 258.096 345.600 258.120 ;
    END
  END eo_d[73]
  PIN eo_d[74]
    DIRECTION OUTPUT ;
    USE SIGNAL ;
    PORT
      LAYER M4 ;
        RECT 345.408 259.104 345.600 259.128 ;
    END
  END eo_d[74]
  PIN eo_d[75]
    DIRECTION OUTPUT ;
    USE SIGNAL ;
    PORT
      LAYER M4 ;
        RECT 345.408 260.064 345.600 260.088 ;
    END
  END eo_d[75]
  PIN eo_d[76]
    DIRECTION OUTPUT ;
    USE SIGNAL ;
    PORT
      LAYER M4 ;
        RECT 345.408 261.072 345.600 261.096 ;
    END
  END eo_d[76]
  PIN eo_d[77]
    DIRECTION OUTPUT ;
    USE SIGNAL ;
    PORT
      LAYER M4 ;
        RECT 345.408 262.032 345.600 262.056 ;
    END
  END eo_d[77]
  PIN eo_d[78]
    DIRECTION OUTPUT ;
    USE SIGNAL ;
    PORT
      LAYER M4 ;
        RECT 345.408 263.040 345.600 263.064 ;
    END
  END eo_d[78]
  PIN eo_d[79]
    DIRECTION OUTPUT ;
    USE SIGNAL ;
    PORT
      LAYER M4 ;
        RECT 345.408 264.048 345.600 264.072 ;
    END
  END eo_d[79]
  PIN eo_d[80]
    DIRECTION OUTPUT ;
    USE SIGNAL ;
    PORT
      LAYER M4 ;
        RECT 345.408 265.008 345.600 265.032 ;
    END
  END eo_d[80]
  PIN eo_d[81]
    DIRECTION OUTPUT ;
    USE SIGNAL ;
    PORT
      LAYER M4 ;
        RECT 345.408 266.016 345.600 266.040 ;
    END
  END eo_d[81]
  PIN eo_d[82]
    DIRECTION OUTPUT ;
    USE SIGNAL ;
    PORT
      LAYER M4 ;
        RECT 345.408 266.976 345.600 267.000 ;
    END
  END eo_d[82]
  PIN eo_d[83]
    DIRECTION OUTPUT ;
    USE SIGNAL ;
    PORT
      LAYER M4 ;
        RECT 345.408 267.984 345.600 268.008 ;
    END
  END eo_d[83]
  PIN eo_d[84]
    DIRECTION OUTPUT ;
    USE SIGNAL ;
    PORT
      LAYER M4 ;
        RECT 345.408 268.944 345.600 268.968 ;
    END
  END eo_d[84]
  PIN eo_d[85]
    DIRECTION OUTPUT ;
    USE SIGNAL ;
    PORT
      LAYER M4 ;
        RECT 345.408 269.952 345.600 269.976 ;
    END
  END eo_d[85]
  PIN eo_d[86]
    DIRECTION OUTPUT ;
    USE SIGNAL ;
    PORT
      LAYER M4 ;
        RECT 345.408 270.912 345.600 270.936 ;
    END
  END eo_d[86]
  PIN eo_d[87]
    DIRECTION OUTPUT ;
    USE SIGNAL ;
    PORT
      LAYER M4 ;
        RECT 345.408 271.920 345.600 271.944 ;
    END
  END eo_d[87]
  PIN eo_d[88]
    DIRECTION OUTPUT ;
    USE SIGNAL ;
    PORT
      LAYER M4 ;
        RECT 345.408 272.880 345.600 272.904 ;
    END
  END eo_d[88]
  PIN eo_d[89]
    DIRECTION OUTPUT ;
    USE SIGNAL ;
    PORT
      LAYER M4 ;
        RECT 345.408 273.888 345.600 273.912 ;
    END
  END eo_d[89]
  PIN eo_d[90]
    DIRECTION OUTPUT ;
    USE SIGNAL ;
    PORT
      LAYER M4 ;
        RECT 345.408 274.896 345.600 274.920 ;
    END
  END eo_d[90]
  PIN eo_d[91]
    DIRECTION OUTPUT ;
    USE SIGNAL ;
    PORT
      LAYER M4 ;
        RECT 345.408 275.856 345.600 275.880 ;
    END
  END eo_d[91]
  PIN eo_d[92]
    DIRECTION OUTPUT ;
    USE SIGNAL ;
    PORT
      LAYER M4 ;
        RECT 345.408 276.864 345.600 276.888 ;
    END
  END eo_d[92]
  PIN eo_d[93]
    DIRECTION OUTPUT ;
    USE SIGNAL ;
    PORT
      LAYER M4 ;
        RECT 345.408 277.824 345.600 277.848 ;
    END
  END eo_d[93]
  PIN eo_d[94]
    DIRECTION OUTPUT ;
    USE SIGNAL ;
    PORT
      LAYER M4 ;
        RECT 345.408 278.832 345.600 278.856 ;
    END
  END eo_d[94]
  PIN eo_d[95]
    DIRECTION OUTPUT ;
    USE SIGNAL ;
    PORT
      LAYER M4 ;
        RECT 345.408 279.792 345.600 279.816 ;
    END
  END eo_d[95]
  PIN eo_d[96]
    DIRECTION OUTPUT ;
    USE SIGNAL ;
    PORT
      LAYER M4 ;
        RECT 345.408 280.800 345.600 280.824 ;
    END
  END eo_d[96]
  PIN eo_d[97]
    DIRECTION OUTPUT ;
    USE SIGNAL ;
    PORT
      LAYER M4 ;
        RECT 345.408 281.760 345.600 281.784 ;
    END
  END eo_d[97]
  PIN eo_d[98]
    DIRECTION OUTPUT ;
    USE SIGNAL ;
    PORT
      LAYER M4 ;
        RECT 345.408 282.768 345.600 282.792 ;
    END
  END eo_d[98]
  PIN eo_d[99]
    DIRECTION OUTPUT ;
    USE SIGNAL ;
    PORT
      LAYER M4 ;
        RECT 345.408 283.776 345.600 283.800 ;
    END
  END eo_d[99]
  PIN eo_d[100]
    DIRECTION OUTPUT ;
    USE SIGNAL ;
    PORT
      LAYER M4 ;
        RECT 345.408 284.736 345.600 284.760 ;
    END
  END eo_d[100]
  PIN eo_d[101]
    DIRECTION OUTPUT ;
    USE SIGNAL ;
    PORT
      LAYER M4 ;
        RECT 345.408 285.744 345.600 285.768 ;
    END
  END eo_d[101]
  PIN eo_d[102]
    DIRECTION OUTPUT ;
    USE SIGNAL ;
    PORT
      LAYER M4 ;
        RECT 345.408 286.704 345.600 286.728 ;
    END
  END eo_d[102]
  PIN eo_d[103]
    DIRECTION OUTPUT ;
    USE SIGNAL ;
    PORT
      LAYER M4 ;
        RECT 345.408 287.712 345.600 287.736 ;
    END
  END eo_d[103]
  PIN eo_d[104]
    DIRECTION OUTPUT ;
    USE SIGNAL ;
    PORT
      LAYER M4 ;
        RECT 345.408 288.672 345.600 288.696 ;
    END
  END eo_d[104]
  PIN eo_d[105]
    DIRECTION OUTPUT ;
    USE SIGNAL ;
    PORT
      LAYER M4 ;
        RECT 345.408 289.680 345.600 289.704 ;
    END
  END eo_d[105]
  PIN eo_d[106]
    DIRECTION OUTPUT ;
    USE SIGNAL ;
    PORT
      LAYER M4 ;
        RECT 345.408 290.640 345.600 290.664 ;
    END
  END eo_d[106]
  PIN eo_d[107]
    DIRECTION OUTPUT ;
    USE SIGNAL ;
    PORT
      LAYER M4 ;
        RECT 345.408 291.648 345.600 291.672 ;
    END
  END eo_d[107]
  PIN eo_d[108]
    DIRECTION OUTPUT ;
    USE SIGNAL ;
    PORT
      LAYER M4 ;
        RECT 345.408 292.608 345.600 292.632 ;
    END
  END eo_d[108]
  PIN eo_d[109]
    DIRECTION OUTPUT ;
    USE SIGNAL ;
    PORT
      LAYER M4 ;
        RECT 345.408 293.616 345.600 293.640 ;
    END
  END eo_d[109]
  PIN eo_d[110]
    DIRECTION OUTPUT ;
    USE SIGNAL ;
    PORT
      LAYER M4 ;
        RECT 345.408 294.624 345.600 294.648 ;
    END
  END eo_d[110]
  PIN eo_d[111]
    DIRECTION OUTPUT ;
    USE SIGNAL ;
    PORT
      LAYER M4 ;
        RECT 345.408 295.584 345.600 295.608 ;
    END
  END eo_d[111]
  PIN eo_d[112]
    DIRECTION OUTPUT ;
    USE SIGNAL ;
    PORT
      LAYER M4 ;
        RECT 345.408 296.592 345.600 296.616 ;
    END
  END eo_d[112]
  PIN eo_d[113]
    DIRECTION OUTPUT ;
    USE SIGNAL ;
    PORT
      LAYER M4 ;
        RECT 345.408 297.552 345.600 297.576 ;
    END
  END eo_d[113]
  PIN eo_d[114]
    DIRECTION OUTPUT ;
    USE SIGNAL ;
    PORT
      LAYER M4 ;
        RECT 345.408 298.560 345.600 298.584 ;
    END
  END eo_d[114]
  PIN eo_d[115]
    DIRECTION OUTPUT ;
    USE SIGNAL ;
    PORT
      LAYER M4 ;
        RECT 345.408 299.520 345.600 299.544 ;
    END
  END eo_d[115]
  PIN eo_d[116]
    DIRECTION OUTPUT ;
    USE SIGNAL ;
    PORT
      LAYER M4 ;
        RECT 345.408 300.528 345.600 300.552 ;
    END
  END eo_d[116]
  PIN eo_d[117]
    DIRECTION OUTPUT ;
    USE SIGNAL ;
    PORT
      LAYER M4 ;
        RECT 345.408 301.488 345.600 301.512 ;
    END
  END eo_d[117]
  PIN eo_d[118]
    DIRECTION OUTPUT ;
    USE SIGNAL ;
    PORT
      LAYER M4 ;
        RECT 345.408 302.496 345.600 302.520 ;
    END
  END eo_d[118]
  PIN eo_d[119]
    DIRECTION OUTPUT ;
    USE SIGNAL ;
    PORT
      LAYER M4 ;
        RECT 345.408 303.504 345.600 303.528 ;
    END
  END eo_d[119]
  PIN eo_d[120]
    DIRECTION OUTPUT ;
    USE SIGNAL ;
    PORT
      LAYER M4 ;
        RECT 345.408 304.464 345.600 304.488 ;
    END
  END eo_d[120]
  PIN eo_d[121]
    DIRECTION OUTPUT ;
    USE SIGNAL ;
    PORT
      LAYER M4 ;
        RECT 345.408 305.472 345.600 305.496 ;
    END
  END eo_d[121]
  PIN eo_d[122]
    DIRECTION OUTPUT ;
    USE SIGNAL ;
    PORT
      LAYER M4 ;
        RECT 345.408 306.432 345.600 306.456 ;
    END
  END eo_d[122]
  PIN eo_d[123]
    DIRECTION OUTPUT ;
    USE SIGNAL ;
    PORT
      LAYER M4 ;
        RECT 345.408 307.440 345.600 307.464 ;
    END
  END eo_d[123]
  PIN eo_d[124]
    DIRECTION OUTPUT ;
    USE SIGNAL ;
    PORT
      LAYER M4 ;
        RECT 345.408 308.400 345.600 308.424 ;
    END
  END eo_d[124]
  PIN eo_d[125]
    DIRECTION OUTPUT ;
    USE SIGNAL ;
    PORT
      LAYER M4 ;
        RECT 345.408 309.408 345.600 309.432 ;
    END
  END eo_d[125]
  PIN eo_d[126]
    DIRECTION OUTPUT ;
    USE SIGNAL ;
    PORT
      LAYER M4 ;
        RECT 345.408 310.368 345.600 310.392 ;
    END
  END eo_d[126]
  PIN eo_d[127]
    DIRECTION OUTPUT ;
    USE SIGNAL ;
    PORT
      LAYER M4 ;
        RECT 345.408 311.376 345.600 311.400 ;
    END
  END eo_d[127]
  PIN eo_d[128]
    DIRECTION OUTPUT ;
    USE SIGNAL ;
    PORT
      LAYER M4 ;
        RECT 345.408 312.336 345.600 312.360 ;
    END
  END eo_d[128]
  PIN eo_d[129]
    DIRECTION OUTPUT ;
    USE SIGNAL ;
    PORT
      LAYER M4 ;
        RECT 345.408 313.344 345.600 313.368 ;
    END
  END eo_d[129]
  PIN eo_d[130]
    DIRECTION OUTPUT ;
    USE SIGNAL ;
    PORT
      LAYER M4 ;
        RECT 345.408 314.352 345.600 314.376 ;
    END
  END eo_d[130]
  PIN eo_d[131]
    DIRECTION OUTPUT ;
    USE SIGNAL ;
    PORT
      LAYER M4 ;
        RECT 345.408 315.312 345.600 315.336 ;
    END
  END eo_d[131]
  PIN eo_d[132]
    DIRECTION OUTPUT ;
    USE SIGNAL ;
    PORT
      LAYER M4 ;
        RECT 345.408 316.320 345.600 316.344 ;
    END
  END eo_d[132]
  PIN eo_d[133]
    DIRECTION OUTPUT ;
    USE SIGNAL ;
    PORT
      LAYER M4 ;
        RECT 345.408 317.280 345.600 317.304 ;
    END
  END eo_d[133]
  PIN eo_d[134]
    DIRECTION OUTPUT ;
    USE SIGNAL ;
    PORT
      LAYER M4 ;
        RECT 345.408 318.288 345.600 318.312 ;
    END
  END eo_d[134]
  PIN eo_d[135]
    DIRECTION OUTPUT ;
    USE SIGNAL ;
    PORT
      LAYER M4 ;
        RECT 345.408 319.248 345.600 319.272 ;
    END
  END eo_d[135]
  PIN eo_d[136]
    DIRECTION OUTPUT ;
    USE SIGNAL ;
    PORT
      LAYER M4 ;
        RECT 345.408 320.256 345.600 320.280 ;
    END
  END eo_d[136]
  PIN eo_d[137]
    DIRECTION OUTPUT ;
    USE SIGNAL ;
    PORT
      LAYER M4 ;
        RECT 345.408 321.216 345.600 321.240 ;
    END
  END eo_d[137]
  PIN eo_d[138]
    DIRECTION OUTPUT ;
    USE SIGNAL ;
    PORT
      LAYER M4 ;
        RECT 345.408 322.224 345.600 322.248 ;
    END
  END eo_d[138]
  PIN eo_d[139]
    DIRECTION OUTPUT ;
    USE SIGNAL ;
    PORT
      LAYER M4 ;
        RECT 345.408 323.184 345.600 323.208 ;
    END
  END eo_d[139]
  PIN eo_d[140]
    DIRECTION OUTPUT ;
    USE SIGNAL ;
    PORT
      LAYER M4 ;
        RECT 345.408 324.192 345.600 324.216 ;
    END
  END eo_d[140]
  PIN eo_d[141]
    DIRECTION OUTPUT ;
    USE SIGNAL ;
    PORT
      LAYER M4 ;
        RECT 345.408 325.200 345.600 325.224 ;
    END
  END eo_d[141]
  PIN eo_d[142]
    DIRECTION OUTPUT ;
    USE SIGNAL ;
    PORT
      LAYER M4 ;
        RECT 345.408 326.160 345.600 326.184 ;
    END
  END eo_d[142]
  PIN eo_d[143]
    DIRECTION OUTPUT ;
    USE SIGNAL ;
    PORT
      LAYER M4 ;
        RECT 345.408 327.168 345.600 327.192 ;
    END
  END eo_d[143]
  PIN eo_d[144]
    DIRECTION OUTPUT ;
    USE SIGNAL ;
    PORT
      LAYER M4 ;
        RECT 345.408 328.128 345.600 328.152 ;
    END
  END eo_d[144]
  PIN eo_d[145]
    DIRECTION OUTPUT ;
    USE SIGNAL ;
    PORT
      LAYER M4 ;
        RECT 345.408 329.136 345.600 329.160 ;
    END
  END eo_d[145]
  PIN eo_d[146]
    DIRECTION OUTPUT ;
    USE SIGNAL ;
    PORT
      LAYER M4 ;
        RECT 345.408 330.096 345.600 330.120 ;
    END
  END eo_d[146]
  PIN eo_d[147]
    DIRECTION OUTPUT ;
    USE SIGNAL ;
    PORT
      LAYER M4 ;
        RECT 345.408 331.104 345.600 331.128 ;
    END
  END eo_d[147]
  PIN eo_d[148]
    DIRECTION OUTPUT ;
    USE SIGNAL ;
    PORT
      LAYER M4 ;
        RECT 345.408 332.064 345.600 332.088 ;
    END
  END eo_d[148]
  PIN eo_d[149]
    DIRECTION OUTPUT ;
    USE SIGNAL ;
    PORT
      LAYER M4 ;
        RECT 345.408 333.072 345.600 333.096 ;
    END
  END eo_d[149]
  PIN eo_d[150]
    DIRECTION OUTPUT ;
    USE SIGNAL ;
    PORT
      LAYER M4 ;
        RECT 345.408 334.080 345.600 334.104 ;
    END
  END eo_d[150]
  PIN eo_d[151]
    DIRECTION OUTPUT ;
    USE SIGNAL ;
    PORT
      LAYER M4 ;
        RECT 345.408 335.040 345.600 335.064 ;
    END
  END eo_d[151]
  PIN eo_d[152]
    DIRECTION OUTPUT ;
    USE SIGNAL ;
    PORT
      LAYER M4 ;
        RECT 345.408 336.048 345.600 336.072 ;
    END
  END eo_d[152]
  PIN eo_d[153]
    DIRECTION OUTPUT ;
    USE SIGNAL ;
    PORT
      LAYER M4 ;
        RECT 345.408 337.008 345.600 337.032 ;
    END
  END eo_d[153]
  PIN eo_d[154]
    DIRECTION OUTPUT ;
    USE SIGNAL ;
    PORT
      LAYER M4 ;
        RECT 345.408 338.016 345.600 338.040 ;
    END
  END eo_d[154]
  PIN eo_d[155]
    DIRECTION OUTPUT ;
    USE SIGNAL ;
    PORT
      LAYER M4 ;
        RECT 345.408 338.976 345.600 339.000 ;
    END
  END eo_d[155]
  PIN eo_d[156]
    DIRECTION OUTPUT ;
    USE SIGNAL ;
    PORT
      LAYER M4 ;
        RECT 345.408 339.984 345.600 340.008 ;
    END
  END eo_d[156]
  PIN eo_d[157]
    DIRECTION OUTPUT ;
    USE SIGNAL ;
    PORT
      LAYER M4 ;
        RECT 345.408 340.944 345.600 340.968 ;
    END
  END eo_d[157]
  PIN eo_d[158]
    DIRECTION OUTPUT ;
    USE SIGNAL ;
    PORT
      LAYER M4 ;
        RECT 345.408 341.952 345.600 341.976 ;
    END
  END eo_d[158]
  PIN eo_d[159]
    DIRECTION OUTPUT ;
    USE SIGNAL ;
    PORT
      LAYER M4 ;
        RECT 345.408 342.912 345.600 342.936 ;
    END
  END eo_d[159]
  PIN s_v
    DIRECTION INPUT ;
    USE SIGNAL ;
    PORT
      LAYER M5 ;
        RECT 4.464 345.408 4.488 345.600 ;
    END
  END s_v
  PIN s_i[0]
    DIRECTION INPUT ;
    USE SIGNAL ;
    PORT
      LAYER M3 ;
        RECT 9.069 345.408 9.093 345.600 ;
    END
  END s_i[0]
  PIN s_i[1]
    DIRECTION INPUT ;
    USE SIGNAL ;
    PORT
      LAYER M5 ;
        RECT 13.680 345.408 13.704 345.600 ;
    END
  END s_i[1]
  PIN s_i[2]
    DIRECTION INPUT ;
    USE SIGNAL ;
    PORT
      LAYER M3 ;
        RECT 18.285 345.408 18.309 345.600 ;
    END
  END s_i[2]
  PIN s_i[3]
    DIRECTION INPUT ;
    USE SIGNAL ;
    PORT
      LAYER M5 ;
        RECT 22.896 345.408 22.920 345.600 ;
    END
  END s_i[3]
  PIN s_i[4]
    DIRECTION INPUT ;
    USE SIGNAL ;
    PORT
      LAYER M3 ;
        RECT 27.501 345.408 27.525 345.600 ;
    END
  END s_i[4]
  PIN s_i[5]
    DIRECTION INPUT ;
    USE SIGNAL ;
    PORT
      LAYER M5 ;
        RECT 32.112 345.408 32.136 345.600 ;
    END
  END s_i[5]
  PIN s_i[6]
    DIRECTION INPUT ;
    USE SIGNAL ;
    PORT
      LAYER M3 ;
        RECT 36.753 345.408 36.777 345.600 ;
    END
  END s_i[6]
  PIN s_i[7]
    DIRECTION INPUT ;
    USE SIGNAL ;
    PORT
      LAYER M5 ;
        RECT 41.328 345.408 41.352 345.600 ;
    END
  END s_i[7]
  PIN s[0]
    DIRECTION INPUT ;
    USE SIGNAL ;
    PORT
      LAYER M3 ;
        RECT 45.969 345.408 45.993 345.600 ;
    END
  END s[0]
  PIN s[1]
    DIRECTION INPUT ;
    USE SIGNAL ;
    PORT
      LAYER M5 ;
        RECT 50.592 345.408 50.616 345.600 ;
    END
  END s[1]
  PIN s[2]
    DIRECTION INPUT ;
    USE SIGNAL ;
    PORT
      LAYER M3 ;
        RECT 55.185 345.408 55.209 345.600 ;
    END
  END s[2]
  PIN s[3]
    DIRECTION INPUT ;
    USE SIGNAL ;
    PORT
      LAYER M5 ;
        RECT 59.808 345.408 59.832 345.600 ;
    END
  END s[3]
  PIN s[4]
    DIRECTION INPUT ;
    USE SIGNAL ;
    PORT
      LAYER M3 ;
        RECT 64.401 345.408 64.425 345.600 ;
    END
  END s[4]
  PIN s[5]
    DIRECTION INPUT ;
    USE SIGNAL ;
    PORT
      LAYER M5 ;
        RECT 69.024 345.408 69.048 345.600 ;
    END
  END s[5]
  PIN s[6]
    DIRECTION INPUT ;
    USE SIGNAL ;
    PORT
      LAYER M3 ;
        RECT 73.617 345.408 73.641 345.600 ;
    END
  END s[6]
  PIN s[7]
    DIRECTION INPUT ;
    USE SIGNAL ;
    PORT
      LAYER M5 ;
        RECT 78.240 345.408 78.264 345.600 ;
    END
  END s[7]
  PIN s[8]
    DIRECTION INPUT ;
    USE SIGNAL ;
    PORT
      LAYER M3 ;
        RECT 82.869 345.408 82.893 345.600 ;
    END
  END s[8]
  PIN s[9]
    DIRECTION INPUT ;
    USE SIGNAL ;
    PORT
      LAYER M5 ;
        RECT 87.456 345.408 87.480 345.600 ;
    END
  END s[9]
  PIN s[10]
    DIRECTION INPUT ;
    USE SIGNAL ;
    PORT
      LAYER M3 ;
        RECT 92.085 345.408 92.109 345.600 ;
    END
  END s[10]
  PIN s[11]
    DIRECTION INPUT ;
    USE SIGNAL ;
    PORT
      LAYER M5 ;
        RECT 96.672 345.408 96.696 345.600 ;
    END
  END s[11]
  PIN s[12]
    DIRECTION INPUT ;
    USE SIGNAL ;
    PORT
      LAYER M3 ;
        RECT 101.301 345.408 101.325 345.600 ;
    END
  END s[12]
  PIN s[13]
    DIRECTION INPUT ;
    USE SIGNAL ;
    PORT
      LAYER M5 ;
        RECT 105.936 345.408 105.960 345.600 ;
    END
  END s[13]
  PIN s[14]
    DIRECTION INPUT ;
    USE SIGNAL ;
    PORT
      LAYER M3 ;
        RECT 110.517 345.408 110.541 345.600 ;
    END
  END s[14]
  PIN s[15]
    DIRECTION INPUT ;
    USE SIGNAL ;
    PORT
      LAYER M5 ;
        RECT 115.152 345.408 115.176 345.600 ;
    END
  END s[15]
  PIN s[16]
    DIRECTION INPUT ;
    USE SIGNAL ;
    PORT
      LAYER M3 ;
        RECT 119.769 345.408 119.793 345.600 ;
    END
  END s[16]
  PIN s[17]
    DIRECTION INPUT ;
    USE SIGNAL ;
    PORT
      LAYER M5 ;
        RECT 124.368 345.408 124.392 345.600 ;
    END
  END s[17]
  PIN s[18]
    DIRECTION INPUT ;
    USE SIGNAL ;
    PORT
      LAYER M3 ;
        RECT 128.985 345.408 129.009 345.600 ;
    END
  END s[18]
  PIN s[19]
    DIRECTION INPUT ;
    USE SIGNAL ;
    PORT
      LAYER M5 ;
        RECT 133.584 345.408 133.608 345.600 ;
    END
  END s[19]
  PIN s[20]
    DIRECTION INPUT ;
    USE SIGNAL ;
    PORT
      LAYER M3 ;
        RECT 138.201 345.408 138.225 345.600 ;
    END
  END s[20]
  PIN s[21]
    DIRECTION INPUT ;
    USE SIGNAL ;
    PORT
      LAYER M5 ;
        RECT 142.800 345.408 142.824 345.600 ;
    END
  END s[21]
  PIN s[22]
    DIRECTION INPUT ;
    USE SIGNAL ;
    PORT
      LAYER M3 ;
        RECT 147.417 345.408 147.441 345.600 ;
    END
  END s[22]
  PIN s[23]
    DIRECTION INPUT ;
    USE SIGNAL ;
    PORT
      LAYER M5 ;
        RECT 152.016 345.408 152.040 345.600 ;
    END
  END s[23]
  PIN s[24]
    DIRECTION INPUT ;
    USE SIGNAL ;
    PORT
      LAYER M3 ;
        RECT 156.633 345.408 156.657 345.600 ;
    END
  END s[24]
  PIN s[25]
    DIRECTION INPUT ;
    USE SIGNAL ;
    PORT
      LAYER M5 ;
        RECT 161.280 345.408 161.304 345.600 ;
    END
  END s[25]
  PIN s[26]
    DIRECTION INPUT ;
    USE SIGNAL ;
    PORT
      LAYER M3 ;
        RECT 165.885 345.408 165.909 345.600 ;
    END
  END s[26]
  PIN s[27]
    DIRECTION INPUT ;
    USE SIGNAL ;
    PORT
      LAYER M5 ;
        RECT 170.496 345.408 170.520 345.600 ;
    END
  END s[27]
  PIN s[28]
    DIRECTION INPUT ;
    USE SIGNAL ;
    PORT
      LAYER M3 ;
        RECT 175.101 345.408 175.125 345.600 ;
    END
  END s[28]
  PIN s[29]
    DIRECTION INPUT ;
    USE SIGNAL ;
    PORT
      LAYER M5 ;
        RECT 179.712 345.408 179.736 345.600 ;
    END
  END s[29]
  PIN s[30]
    DIRECTION INPUT ;
    USE SIGNAL ;
    PORT
      LAYER M3 ;
        RECT 184.317 345.408 184.341 345.600 ;
    END
  END s[30]
  PIN s[31]
    DIRECTION INPUT ;
    USE SIGNAL ;
    PORT
      LAYER M5 ;
        RECT 188.928 345.408 188.952 345.600 ;
    END
  END s[31]
  PIN rb_v
    DIRECTION OUTPUT ;
    USE SIGNAL ;
    PORT
      LAYER M3 ;
        RECT 193.533 345.408 193.557 345.600 ;
    END
  END rb_v
  PIN rb_d[0]
    DIRECTION OUTPUT ;
    USE SIGNAL ;
    PORT
      LAYER M5 ;
        RECT 198.144 345.408 198.168 345.600 ;
    END
  END rb_d[0]
  PIN rb_d[1]
    DIRECTION OUTPUT ;
    USE SIGNAL ;
    PORT
      LAYER M3 ;
        RECT 202.749 345.408 202.773 345.600 ;
    END
  END rb_d[1]
  PIN rb_d[2]
    DIRECTION OUTPUT ;
    USE SIGNAL ;
    PORT
      LAYER M5 ;
        RECT 207.360 345.408 207.384 345.600 ;
    END
  END rb_d[2]
  PIN rb_d[3]
    DIRECTION OUTPUT ;
    USE SIGNAL ;
    PORT
      LAYER M3 ;
        RECT 212.001 345.408 212.025 345.600 ;
    END
  END rb_d[3]
  PIN rb_d[4]
    DIRECTION OUTPUT ;
    USE SIGNAL ;
    PORT
      LAYER M5 ;
        RECT 216.624 345.408 216.648 345.600 ;
    END
  END rb_d[4]
  PIN rb_d[5]
    DIRECTION OUTPUT ;
    USE SIGNAL ;
    PORT
      LAYER M3 ;
        RECT 221.217 345.408 221.241 345.600 ;
    END
  END rb_d[5]
  PIN rb_d[6]
    DIRECTION OUTPUT ;
    USE SIGNAL ;
    PORT
      LAYER M5 ;
        RECT 225.840 345.408 225.864 345.600 ;
    END
  END rb_d[6]
  PIN rb_d[7]
    DIRECTION OUTPUT ;
    USE SIGNAL ;
    PORT
      LAYER M3 ;
        RECT 230.433 345.408 230.457 345.600 ;
    END
  END rb_d[7]
  PIN rb_d[8]
    DIRECTION OUTPUT ;
    USE SIGNAL ;
    PORT
      LAYER M5 ;
        RECT 235.056 345.408 235.080 345.600 ;
    END
  END rb_d[8]
  PIN rb_d[9]
    DIRECTION OUTPUT ;
    USE SIGNAL ;
    PORT
      LAYER M3 ;
        RECT 239.649 345.408 239.673 345.600 ;
    END
  END rb_d[9]
  PIN rb_d[10]
    DIRECTION OUTPUT ;
    USE SIGNAL ;
    PORT
      LAYER M5 ;
        RECT 244.272 345.408 244.296 345.600 ;
    END
  END rb_d[10]
  PIN rb_d[11]
    DIRECTION OUTPUT ;
    USE SIGNAL ;
    PORT
      LAYER M3 ;
        RECT 248.901 345.408 248.925 345.600 ;
    END
  END rb_d[11]
  PIN rb_d[12]
    DIRECTION OUTPUT ;
    USE SIGNAL ;
    PORT
      LAYER M5 ;
        RECT 253.488 345.408 253.512 345.600 ;
    END
  END rb_d[12]
  PIN rb_d[13]
    DIRECTION OUTPUT ;
    USE SIGNAL ;
    PORT
      LAYER M3 ;
        RECT 258.117 345.408 258.141 345.600 ;
    END
  END rb_d[13]
  PIN rb_d[14]
    DIRECTION OUTPUT ;
    USE SIGNAL ;
    PORT
      LAYER M5 ;
        RECT 262.704 345.408 262.728 345.600 ;
    END
  END rb_d[14]
  PIN rb_d[15]
    DIRECTION OUTPUT ;
    USE SIGNAL ;
    PORT
      LAYER M3 ;
        RECT 267.333 345.408 267.357 345.600 ;
    END
  END rb_d[15]
  PIN rb_d[16]
    DIRECTION OUTPUT ;
    USE SIGNAL ;
    PORT
      LAYER M5 ;
        RECT 271.920 345.408 271.944 345.600 ;
    END
  END rb_d[16]
  PIN rb_d[17]
    DIRECTION OUTPUT ;
    USE SIGNAL ;
    PORT
      LAYER M3 ;
        RECT 276.549 345.408 276.573 345.600 ;
    END
  END rb_d[17]
  PIN rb_d[18]
    DIRECTION OUTPUT ;
    USE SIGNAL ;
    PORT
      LAYER M5 ;
        RECT 281.184 345.408 281.208 345.600 ;
    END
  END rb_d[18]
  PIN rb_d[19]
    DIRECTION OUTPUT ;
    USE SIGNAL ;
    PORT
      LAYER M3 ;
        RECT 285.765 345.408 285.789 345.600 ;
    END
  END rb_d[19]
  PIN rb_d[20]
    DIRECTION OUTPUT ;
    USE SIGNAL ;
    PORT
      LAYER M5 ;
        RECT 290.400 345.408 290.424 345.600 ;
    END
  END rb_d[20]
  PIN rb_d[21]
    DIRECTION OUTPUT ;
    USE SIGNAL ;
    PORT
      LAYER M3 ;
        RECT 295.017 345.408 295.041 345.600 ;
    END
  END rb_d[21]
  PIN rb_d[22]
    DIRECTION OUTPUT ;
    USE SIGNAL ;
    PORT
      LAYER M5 ;
        RECT 299.616 345.408 299.640 345.600 ;
    END
  END rb_d[22]
  PIN rb_d[23]
    DIRECTION OUTPUT ;
    USE SIGNAL ;
    PORT
      LAYER M3 ;
        RECT 304.233 345.408 304.257 345.600 ;
    END
  END rb_d[23]
  PIN rb_d[24]
    DIRECTION OUTPUT ;
    USE SIGNAL ;
    PORT
      LAYER M5 ;
        RECT 308.832 345.408 308.856 345.600 ;
    END
  END rb_d[24]
  PIN rb_d[25]
    DIRECTION OUTPUT ;
    USE SIGNAL ;
    PORT
      LAYER M3 ;
        RECT 313.449 345.408 313.473 345.600 ;
    END
  END rb_d[25]
  PIN rb_d[26]
    DIRECTION OUTPUT ;
    USE SIGNAL ;
    PORT
      LAYER M5 ;
        RECT 318.048 345.408 318.072 345.600 ;
    END
  END rb_d[26]
  PIN rb_d[27]
    DIRECTION OUTPUT ;
    USE SIGNAL ;
    PORT
      LAYER M3 ;
        RECT 322.665 345.408 322.689 345.600 ;
    END
  END rb_d[27]
  PIN rb_d[28]
    DIRECTION OUTPUT ;
    USE SIGNAL ;
    PORT
      LAYER M5 ;
        RECT 327.264 345.408 327.288 345.600 ;
    END
  END rb_d[28]
  PIN rb_d[29]
    DIRECTION OUTPUT ;
    USE SIGNAL ;
    PORT
      LAYER M3 ;
        RECT 331.881 345.408 331.905 345.600 ;
    END
  END rb_d[29]
  PIN rb_d[30]
    DIRECTION OUTPUT ;
    USE SIGNAL ;
    PORT
      LAYER M5 ;
        RECT 336.528 345.408 336.552 345.600 ;
    END
  END rb_d[30]
  PIN rb_d[31]
    DIRECTION OUTPUT ;
    USE SIGNAL ;
    PORT
      LAYER M3 ;
        RECT 341.133 345.408 341.157 345.600 ;
    END
  END rb_d[31]
  PIN clk
    DIRECTION INPUT ;
    USE CLOCK ;
    PORT
      LAYER M5 ;
        RECT 6.288 0.000 6.312 0.192 ;
    END
  END clk
  PIN rst_n
    DIRECTION INPUT ;
    USE SIGNAL ;
    PORT
      LAYER M3 ;
        RECT 14.649 0.000 14.673 0.192 ;
    END
  END rst_n
  PIN go
    DIRECTION INPUT ;
    USE SIGNAL ;
    PORT
      LAYER M5 ;
        RECT 22.944 0.000 22.968 0.192 ;
    END
  END go
  PIN mode
    DIRECTION INPUT ;
    USE SIGNAL ;
    PORT
      LAYER M3 ;
        RECT 31.281 0.000 31.305 0.192 ;
    END
  END mode
  PIN sid[0]
    DIRECTION INPUT ;
    USE SIGNAL ;
    PORT
      LAYER M5 ;
        RECT 39.600 0.000 39.624 0.192 ;
    END
  END sid[0]
  PIN sid[1]
    DIRECTION INPUT ;
    USE SIGNAL ;
    PORT
      LAYER M3 ;
        RECT 47.913 0.000 47.937 0.192 ;
    END
  END sid[1]
  PIN sid[2]
    DIRECTION INPUT ;
    USE SIGNAL ;
    PORT
      LAYER M5 ;
        RECT 56.256 0.000 56.280 0.192 ;
    END
  END sid[2]
  PIN sid[3]
    DIRECTION INPUT ;
    USE SIGNAL ;
    PORT
      LAYER M3 ;
        RECT 64.581 0.000 64.605 0.192 ;
    END
  END sid[3]
  PIN eps[0]
    DIRECTION INPUT ;
    USE SIGNAL ;
    PORT
      LAYER M5 ;
        RECT 72.912 0.000 72.936 0.192 ;
    END
  END eps[0]
  PIN eps[1]
    DIRECTION INPUT ;
    USE SIGNAL ;
    PORT
      LAYER M3 ;
        RECT 81.213 0.000 81.237 0.192 ;
    END
  END eps[1]
  PIN eps[2]
    DIRECTION INPUT ;
    USE SIGNAL ;
    PORT
      LAYER M5 ;
        RECT 89.568 0.000 89.592 0.192 ;
    END
  END eps[2]
  PIN eps[3]
    DIRECTION INPUT ;
    USE SIGNAL ;
    PORT
      LAYER M3 ;
        RECT 97.881 0.000 97.905 0.192 ;
    END
  END eps[3]
  PIN eps[4]
    DIRECTION INPUT ;
    USE SIGNAL ;
    PORT
      LAYER M5 ;
        RECT 106.176 0.000 106.200 0.192 ;
    END
  END eps[4]
  PIN eps[5]
    DIRECTION INPUT ;
    USE SIGNAL ;
    PORT
      LAYER M3 ;
        RECT 114.513 0.000 114.537 0.192 ;
    END
  END eps[5]
  PIN eps[6]
    DIRECTION INPUT ;
    USE SIGNAL ;
    PORT
      LAYER M5 ;
        RECT 122.832 0.000 122.856 0.192 ;
    END
  END eps[6]
  PIN eps[7]
    DIRECTION INPUT ;
    USE SIGNAL ;
    PORT
      LAYER M3 ;
        RECT 131.181 0.000 131.205 0.192 ;
    END
  END eps[7]
  PIN eps[8]
    DIRECTION INPUT ;
    USE SIGNAL ;
    PORT
      LAYER M5 ;
        RECT 139.488 0.000 139.512 0.192 ;
    END
  END eps[8]
  PIN eps[9]
    DIRECTION INPUT ;
    USE SIGNAL ;
    PORT
      LAYER M3 ;
        RECT 147.813 0.000 147.837 0.192 ;
    END
  END eps[9]
  PIN eps[10]
    DIRECTION INPUT ;
    USE SIGNAL ;
    PORT
      LAYER M5 ;
        RECT 156.144 0.000 156.168 0.192 ;
    END
  END eps[10]
  PIN eps[11]
    DIRECTION INPUT ;
    USE SIGNAL ;
    PORT
      LAYER M3 ;
        RECT 164.481 0.000 164.505 0.192 ;
    END
  END eps[11]
  PIN eps[12]
    DIRECTION INPUT ;
    USE SIGNAL ;
    PORT
      LAYER M5 ;
        RECT 172.800 0.000 172.824 0.192 ;
    END
  END eps[12]
  PIN eps[13]
    DIRECTION INPUT ;
    USE SIGNAL ;
    PORT
      LAYER M3 ;
        RECT 181.113 0.000 181.137 0.192 ;
    END
  END eps[13]
  PIN eps[14]
    DIRECTION INPUT ;
    USE SIGNAL ;
    PORT
      LAYER M5 ;
        RECT 189.456 0.000 189.480 0.192 ;
    END
  END eps[14]
  PIN eps[15]
    DIRECTION INPUT ;
    USE SIGNAL ;
    PORT
      LAYER M3 ;
        RECT 197.745 0.000 197.769 0.192 ;
    END
  END eps[15]
  PIN eps[16]
    DIRECTION INPUT ;
    USE SIGNAL ;
    PORT
      LAYER M5 ;
        RECT 206.064 0.000 206.088 0.192 ;
    END
  END eps[16]
  PIN eps[17]
    DIRECTION INPUT ;
    USE SIGNAL ;
    PORT
      LAYER M3 ;
        RECT 214.413 0.000 214.437 0.192 ;
    END
  END eps[17]
  PIN eps[18]
    DIRECTION INPUT ;
    USE SIGNAL ;
    PORT
      LAYER M5 ;
        RECT 222.720 0.000 222.744 0.192 ;
    END
  END eps[18]
  PIN eps[19]
    DIRECTION INPUT ;
    USE SIGNAL ;
    PORT
      LAYER M3 ;
        RECT 231.045 0.000 231.069 0.192 ;
    END
  END eps[19]
  PIN eps[20]
    DIRECTION INPUT ;
    USE SIGNAL ;
    PORT
      LAYER M5 ;
        RECT 239.376 0.000 239.400 0.192 ;
    END
  END eps[20]
  PIN eps[21]
    DIRECTION INPUT ;
    USE SIGNAL ;
    PORT
      LAYER M3 ;
        RECT 247.713 0.000 247.737 0.192 ;
    END
  END eps[21]
  PIN eps[22]
    DIRECTION INPUT ;
    USE SIGNAL ;
    PORT
      LAYER M5 ;
        RECT 256.032 0.000 256.056 0.192 ;
    END
  END eps[22]
  PIN eps[23]
    DIRECTION INPUT ;
    USE SIGNAL ;
    PORT
      LAYER M3 ;
        RECT 264.345 0.000 264.369 0.192 ;
    END
  END eps[23]
  PIN eps[24]
    DIRECTION INPUT ;
    USE SIGNAL ;
    PORT
      LAYER M5 ;
        RECT 272.688 0.000 272.712 0.192 ;
    END
  END eps[24]
  PIN eps[25]
    DIRECTION INPUT ;
    USE SIGNAL ;
    PORT
      LAYER M3 ;
        RECT 281.013 0.000 281.037 0.192 ;
    END
  END eps[25]
  PIN eps[26]
    DIRECTION INPUT ;
    USE SIGNAL ;
    PORT
      LAYER M5 ;
        RECT 289.344 0.000 289.368 0.192 ;
    END
  END eps[26]
  PIN eps[27]
    DIRECTION INPUT ;
    USE SIGNAL ;
    PORT
      LAYER M3 ;
        RECT 297.645 0.000 297.669 0.192 ;
    END
  END eps[27]
  PIN eps[28]
    DIRECTION INPUT ;
    USE SIGNAL ;
    PORT
      LAYER M5 ;
        RECT 305.952 0.000 305.976 0.192 ;
    END
  END eps[28]
  PIN eps[29]
    DIRECTION INPUT ;
    USE SIGNAL ;
    PORT
      LAYER M3 ;
        RECT 314.277 0.000 314.301 0.192 ;
    END
  END eps[29]
  PIN eps[30]
    DIRECTION INPUT ;
    USE SIGNAL ;
    PORT
      LAYER M5 ;
        RECT 322.608 0.000 322.632 0.192 ;
    END
  END eps[30]
  PIN eps[31]
    DIRECTION INPUT ;
    USE SIGNAL ;
    PORT
      LAYER M3 ;
        RECT 330.945 0.000 330.969 0.192 ;
    END
  END eps[31]
  PIN fault
    DIRECTION OUTPUT ;
    USE SIGNAL ;
    PORT
      LAYER M5 ;
        RECT 339.264 0.000 339.288 0.192 ;
    END
  END fault
  PIN VDD
    DIRECTION INOUT ;
    USE POWER ;
    PORT
      LAYER M5 ;
        RECT 2.460 0.500 2.580 345.100 ;
        RECT 7.860 0.500 7.980 345.100 ;
        RECT 13.260 0.500 13.380 345.100 ;
        RECT 18.660 0.500 18.780 345.100 ;
        RECT 24.060 0.500 24.180 345.100 ;
        RECT 29.460 0.500 29.580 345.100 ;
        RECT 34.860 0.500 34.980 345.100 ;
        RECT 40.260 0.500 40.380 345.100 ;
        RECT 45.660 0.500 45.780 345.100 ;
        RECT 51.060 0.500 51.180 345.100 ;
        RECT 56.460 0.500 56.580 345.100 ;
        RECT 61.860 0.500 61.980 345.100 ;
        RECT 67.260 0.500 67.380 345.100 ;
        RECT 72.660 0.500 72.780 345.100 ;
        RECT 78.060 0.500 78.180 345.100 ;
        RECT 83.460 0.500 83.580 345.100 ;
        RECT 88.860 0.500 88.980 345.100 ;
        RECT 94.260 0.500 94.380 345.100 ;
        RECT 99.660 0.500 99.780 345.100 ;
        RECT 105.060 0.500 105.180 345.100 ;
        RECT 110.460 0.500 110.580 345.100 ;
        RECT 115.860 0.500 115.980 345.100 ;
        RECT 121.260 0.500 121.380 345.100 ;
        RECT 126.660 0.500 126.780 345.100 ;
        RECT 132.060 0.500 132.180 345.100 ;
        RECT 137.460 0.500 137.580 345.100 ;
        RECT 142.860 0.500 142.980 345.100 ;
        RECT 148.260 0.500 148.380 345.100 ;
        RECT 153.660 0.500 153.780 345.100 ;
        RECT 159.060 0.500 159.180 345.100 ;
        RECT 164.460 0.500 164.580 345.100 ;
        RECT 169.860 0.500 169.980 345.100 ;
        RECT 175.260 0.500 175.380 345.100 ;
        RECT 180.660 0.500 180.780 345.100 ;
        RECT 186.060 0.500 186.180 345.100 ;
        RECT 191.460 0.500 191.580 345.100 ;
        RECT 196.860 0.500 196.980 345.100 ;
        RECT 202.260 0.500 202.380 345.100 ;
        RECT 207.660 0.500 207.780 345.100 ;
        RECT 213.060 0.500 213.180 345.100 ;
        RECT 218.460 0.500 218.580 345.100 ;
        RECT 223.860 0.500 223.980 345.100 ;
        RECT 229.260 0.500 229.380 345.100 ;
        RECT 234.660 0.500 234.780 345.100 ;
        RECT 240.060 0.500 240.180 345.100 ;
        RECT 245.460 0.500 245.580 345.100 ;
        RECT 250.860 0.500 250.980 345.100 ;
        RECT 256.260 0.500 256.380 345.100 ;
        RECT 261.660 0.500 261.780 345.100 ;
        RECT 267.060 0.500 267.180 345.100 ;
        RECT 272.460 0.500 272.580 345.100 ;
        RECT 277.860 0.500 277.980 345.100 ;
        RECT 283.260 0.500 283.380 345.100 ;
        RECT 288.660 0.500 288.780 345.100 ;
        RECT 294.060 0.500 294.180 345.100 ;
        RECT 299.460 0.500 299.580 345.100 ;
        RECT 304.860 0.500 304.980 345.100 ;
        RECT 310.260 0.500 310.380 345.100 ;
        RECT 315.660 0.500 315.780 345.100 ;
        RECT 321.060 0.500 321.180 345.100 ;
        RECT 326.460 0.500 326.580 345.100 ;
        RECT 331.860 0.500 331.980 345.100 ;
        RECT 337.260 0.500 337.380 345.100 ;
        RECT 342.660 0.500 342.780 345.100 ;
    END
  END VDD
  PIN VSS
    DIRECTION INOUT ;
    USE GROUND ;
    PORT
      LAYER M5 ;
        RECT 2.652 0.500 2.772 345.100 ;
        RECT 8.052 0.500 8.172 345.100 ;
        RECT 13.452 0.500 13.572 345.100 ;
        RECT 18.852 0.500 18.972 345.100 ;
        RECT 24.252 0.500 24.372 345.100 ;
        RECT 29.652 0.500 29.772 345.100 ;
        RECT 35.052 0.500 35.172 345.100 ;
        RECT 40.452 0.500 40.572 345.100 ;
        RECT 45.852 0.500 45.972 345.100 ;
        RECT 51.252 0.500 51.372 345.100 ;
        RECT 56.652 0.500 56.772 345.100 ;
        RECT 62.052 0.500 62.172 345.100 ;
        RECT 67.452 0.500 67.572 345.100 ;
        RECT 72.852 0.500 72.972 345.100 ;
        RECT 78.252 0.500 78.372 345.100 ;
        RECT 83.652 0.500 83.772 345.100 ;
        RECT 89.052 0.500 89.172 345.100 ;
        RECT 94.452 0.500 94.572 345.100 ;
        RECT 99.852 0.500 99.972 345.100 ;
        RECT 105.252 0.500 105.372 345.100 ;
        RECT 110.652 0.500 110.772 345.100 ;
        RECT 116.052 0.500 116.172 345.100 ;
        RECT 121.452 0.500 121.572 345.100 ;
        RECT 126.852 0.500 126.972 345.100 ;
        RECT 132.252 0.500 132.372 345.100 ;
        RECT 137.652 0.500 137.772 345.100 ;
        RECT 143.052 0.500 143.172 345.100 ;
        RECT 148.452 0.500 148.572 345.100 ;
        RECT 153.852 0.500 153.972 345.100 ;
        RECT 159.252 0.500 159.372 345.100 ;
        RECT 164.652 0.500 164.772 345.100 ;
        RECT 170.052 0.500 170.172 345.100 ;
        RECT 175.452 0.500 175.572 345.100 ;
        RECT 180.852 0.500 180.972 345.100 ;
        RECT 186.252 0.500 186.372 345.100 ;
        RECT 191.652 0.500 191.772 345.100 ;
        RECT 197.052 0.500 197.172 345.100 ;
        RECT 202.452 0.500 202.572 345.100 ;
        RECT 207.852 0.500 207.972 345.100 ;
        RECT 213.252 0.500 213.372 345.100 ;
        RECT 218.652 0.500 218.772 345.100 ;
        RECT 224.052 0.500 224.172 345.100 ;
        RECT 229.452 0.500 229.572 345.100 ;
        RECT 234.852 0.500 234.972 345.100 ;
        RECT 240.252 0.500 240.372 345.100 ;
        RECT 245.652 0.500 245.772 345.100 ;
        RECT 251.052 0.500 251.172 345.100 ;
        RECT 256.452 0.500 256.572 345.100 ;
        RECT 261.852 0.500 261.972 345.100 ;
        RECT 267.252 0.500 267.372 345.100 ;
        RECT 272.652 0.500 272.772 345.100 ;
        RECT 278.052 0.500 278.172 345.100 ;
        RECT 283.452 0.500 283.572 345.100 ;
        RECT 288.852 0.500 288.972 345.100 ;
        RECT 294.252 0.500 294.372 345.100 ;
        RECT 299.652 0.500 299.772 345.100 ;
        RECT 305.052 0.500 305.172 345.100 ;
        RECT 310.452 0.500 310.572 345.100 ;
        RECT 315.852 0.500 315.972 345.100 ;
        RECT 321.252 0.500 321.372 345.100 ;
        RECT 326.652 0.500 326.772 345.100 ;
        RECT 332.052 0.500 332.172 345.100 ;
        RECT 337.452 0.500 337.572 345.100 ;
        RECT 342.852 0.500 342.972 345.100 ;
    END
  END VSS
  OBS
    LAYER M1 ;
      RECT 0.500 0.500 345.100 345.100 ;
    LAYER M2 ;
      RECT 0.500 0.500 345.100 345.100 ;
    LAYER M3 ;
      RECT 10.800 10.800 334.800 334.800 ;
    LAYER M4 ;
      RECT 10.800 10.800 334.800 334.800 ;
    LAYER M5 ;
      RECT 10.800 10.800 13.260 334.800 ;
      RECT 13.380 10.800 13.452 334.800 ;
      RECT 13.572 10.800 18.660 334.800 ;
      RECT 18.780 10.800 18.852 334.800 ;
      RECT 18.972 10.800 24.060 334.800 ;
      RECT 24.180 10.800 24.252 334.800 ;
      RECT 24.372 10.800 29.460 334.800 ;
      RECT 29.580 10.800 29.652 334.800 ;
      RECT 29.772 10.800 34.860 334.800 ;
      RECT 34.980 10.800 35.052 334.800 ;
      RECT 35.172 10.800 40.260 334.800 ;
      RECT 40.380 10.800 40.452 334.800 ;
      RECT 40.572 10.800 45.660 334.800 ;
      RECT 45.780 10.800 45.852 334.800 ;
      RECT 45.972 10.800 51.060 334.800 ;
      RECT 51.180 10.800 51.252 334.800 ;
      RECT 51.372 10.800 56.460 334.800 ;
      RECT 56.580 10.800 56.652 334.800 ;
      RECT 56.772 10.800 61.860 334.800 ;
      RECT 61.980 10.800 62.052 334.800 ;
      RECT 62.172 10.800 67.260 334.800 ;
      RECT 67.380 10.800 67.452 334.800 ;
      RECT 67.572 10.800 72.660 334.800 ;
      RECT 72.780 10.800 72.852 334.800 ;
      RECT 72.972 10.800 78.060 334.800 ;
      RECT 78.180 10.800 78.252 334.800 ;
      RECT 78.372 10.800 83.460 334.800 ;
      RECT 83.580 10.800 83.652 334.800 ;
      RECT 83.772 10.800 88.860 334.800 ;
      RECT 88.980 10.800 89.052 334.800 ;
      RECT 89.172 10.800 94.260 334.800 ;
      RECT 94.380 10.800 94.452 334.800 ;
      RECT 94.572 10.800 99.660 334.800 ;
      RECT 99.780 10.800 99.852 334.800 ;
      RECT 99.972 10.800 105.060 334.800 ;
      RECT 105.180 10.800 105.252 334.800 ;
      RECT 105.372 10.800 110.460 334.800 ;
      RECT 110.580 10.800 110.652 334.800 ;
      RECT 110.772 10.800 115.860 334.800 ;
      RECT 115.980 10.800 116.052 334.800 ;
      RECT 116.172 10.800 121.260 334.800 ;
      RECT 121.380 10.800 121.452 334.800 ;
      RECT 121.572 10.800 126.660 334.800 ;
      RECT 126.780 10.800 126.852 334.800 ;
      RECT 126.972 10.800 132.060 334.800 ;
      RECT 132.180 10.800 132.252 334.800 ;
      RECT 132.372 10.800 137.460 334.800 ;
      RECT 137.580 10.800 137.652 334.800 ;
      RECT 137.772 10.800 142.860 334.800 ;
      RECT 142.980 10.800 143.052 334.800 ;
      RECT 143.172 10.800 148.260 334.800 ;
      RECT 148.380 10.800 148.452 334.800 ;
      RECT 148.572 10.800 153.660 334.800 ;
      RECT 153.780 10.800 153.852 334.800 ;
      RECT 153.972 10.800 159.060 334.800 ;
      RECT 159.180 10.800 159.252 334.800 ;
      RECT 159.372 10.800 164.460 334.800 ;
      RECT 164.580 10.800 164.652 334.800 ;
      RECT 164.772 10.800 169.860 334.800 ;
      RECT 169.980 10.800 170.052 334.800 ;
      RECT 170.172 10.800 175.260 334.800 ;
      RECT 175.380 10.800 175.452 334.800 ;
      RECT 175.572 10.800 180.660 334.800 ;
      RECT 180.780 10.800 180.852 334.800 ;
      RECT 180.972 10.800 186.060 334.800 ;
      RECT 186.180 10.800 186.252 334.800 ;
      RECT 186.372 10.800 191.460 334.800 ;
      RECT 191.580 10.800 191.652 334.800 ;
      RECT 191.772 10.800 196.860 334.800 ;
      RECT 196.980 10.800 197.052 334.800 ;
      RECT 197.172 10.800 202.260 334.800 ;
      RECT 202.380 10.800 202.452 334.800 ;
      RECT 202.572 10.800 207.660 334.800 ;
      RECT 207.780 10.800 207.852 334.800 ;
      RECT 207.972 10.800 213.060 334.800 ;
      RECT 213.180 10.800 213.252 334.800 ;
      RECT 213.372 10.800 218.460 334.800 ;
      RECT 218.580 10.800 218.652 334.800 ;
      RECT 218.772 10.800 223.860 334.800 ;
      RECT 223.980 10.800 224.052 334.800 ;
      RECT 224.172 10.800 229.260 334.800 ;
      RECT 229.380 10.800 229.452 334.800 ;
      RECT 229.572 10.800 234.660 334.800 ;
      RECT 234.780 10.800 234.852 334.800 ;
      RECT 234.972 10.800 240.060 334.800 ;
      RECT 240.180 10.800 240.252 334.800 ;
      RECT 240.372 10.800 245.460 334.800 ;
      RECT 245.580 10.800 245.652 334.800 ;
      RECT 245.772 10.800 250.860 334.800 ;
      RECT 250.980 10.800 251.052 334.800 ;
      RECT 251.172 10.800 256.260 334.800 ;
      RECT 256.380 10.800 256.452 334.800 ;
      RECT 256.572 10.800 261.660 334.800 ;
      RECT 261.780 10.800 261.852 334.800 ;
      RECT 261.972 10.800 267.060 334.800 ;
      RECT 267.180 10.800 267.252 334.800 ;
      RECT 267.372 10.800 272.460 334.800 ;
      RECT 272.580 10.800 272.652 334.800 ;
      RECT 272.772 10.800 277.860 334.800 ;
      RECT 277.980 10.800 278.052 334.800 ;
      RECT 278.172 10.800 283.260 334.800 ;
      RECT 283.380 10.800 283.452 334.800 ;
      RECT 283.572 10.800 288.660 334.800 ;
      RECT 288.780 10.800 288.852 334.800 ;
      RECT 288.972 10.800 294.060 334.800 ;
      RECT 294.180 10.800 294.252 334.800 ;
      RECT 294.372 10.800 299.460 334.800 ;
      RECT 299.580 10.800 299.652 334.800 ;
      RECT 299.772 10.800 304.860 334.800 ;
      RECT 304.980 10.800 305.052 334.800 ;
      RECT 305.172 10.800 310.260 334.800 ;
      RECT 310.380 10.800 310.452 334.800 ;
      RECT 310.572 10.800 315.660 334.800 ;
      RECT 315.780 10.800 315.852 334.800 ;
      RECT 315.972 10.800 321.060 334.800 ;
      RECT 321.180 10.800 321.252 334.800 ;
      RECT 321.372 10.800 326.460 334.800 ;
      RECT 326.580 10.800 326.652 334.800 ;
      RECT 326.772 10.800 331.860 334.800 ;
      RECT 331.980 10.800 332.052 334.800 ;
      RECT 332.172 10.800 334.800 334.800 ;
  END
END ot_s81dv_xfin
END LIBRARY
